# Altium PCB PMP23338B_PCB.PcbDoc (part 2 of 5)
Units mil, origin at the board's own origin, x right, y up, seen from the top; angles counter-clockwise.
Board outline 5708.66 x 4330.71 mil, 6 copper layers (Top Layer, Signal Layer 1, Signal Layer 2, Signal Layer 3, Signal Layer 4, Bottom Layer), stack 65.8 mil thick; 209 components, 108 nets, 629 pads, 390 vias.

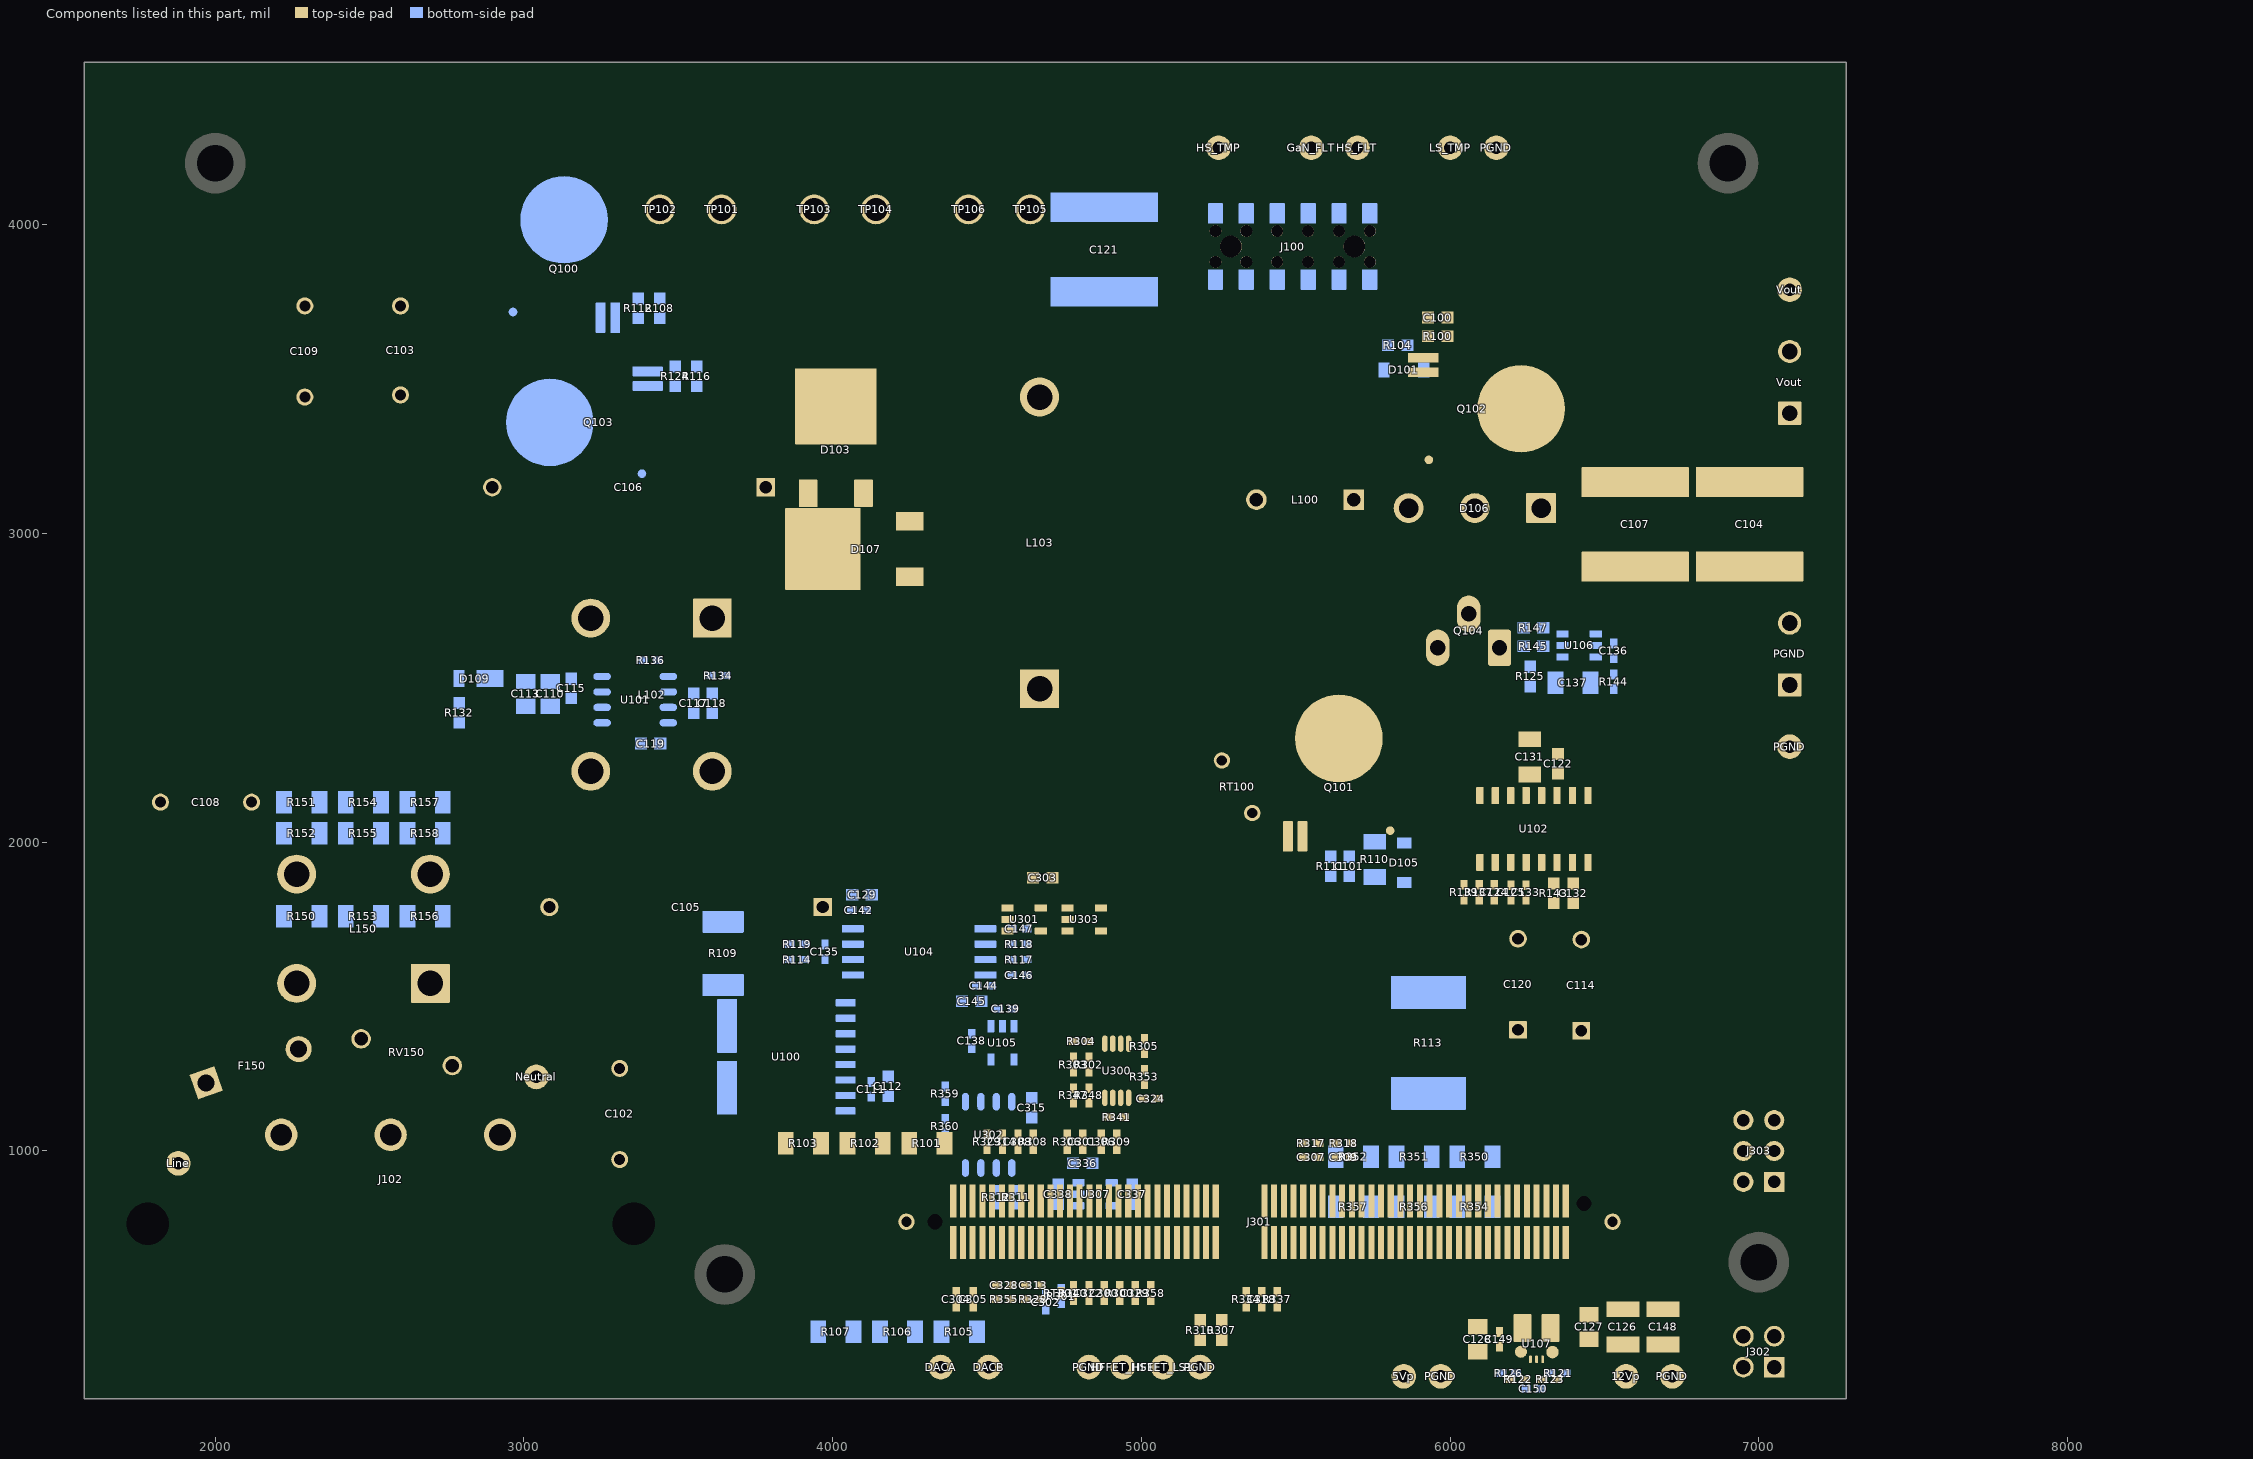
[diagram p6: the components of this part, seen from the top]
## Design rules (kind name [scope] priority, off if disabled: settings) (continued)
PolygonConnect PolygonConnect_38 [All vs IsNamedPolygon('SWNODE') Or  IsNamedPolygon('D403_2') Or  IsNamedPolygon('D403_2') Or  IsNamedPolygon('PGND') Or  IsNamedPolygon('BOTTOM_LAYER_NETC106_2_P030') Or  IsNamedPolygon('C102_1') Or  IsNamedPolygon('SGND') Or  IsNamedPolygon('TOP_LAYER_54V1_P046') Or  IsNamedPolygon('TOP_LAYER_54V2_P048') Or  IsNamedPolygon('TOP_LAYER_54V2_P048') Or  IsNamedPolygon('C108_1') Or  IsNamedPolygon('C108_1') Or  IsNamedPolygon('C108_1') Or  IsNamedPolygon('C108_1') Or  IsNamedPolygon('C108_1') Or  IsNamedPolygon('C108_1') Or  IsNamedPolygon('PGND') Or  IsNamedPolygon('ZCD') Or  IsNamedPolygon('Line') Or  IsNamedPolygon('5Vp') Or  IsNamedPolygon('12Vp') Or  IsNamedPolygon('T200_4') Or  IsNamedPolygon('T200_6') Or  IsNamedPolygon('SWNODE3') Or  IsNamedPolygon('T200_4') Or  IsNamedPolygon('T200_6') Or  IsNamedPolygon('SWNODE4') Or  IsNamedPolygon('VSR') Or  IsNamedPolygon('Iout_SNS') Or  IsNamedPolygon('SIGNAL_LAYER_2_VBB_P094') Or  IsNamedPolygon('Vbulk1') Or  IsNamedPolygon('VBB') Or  IsNamedPolygon('SIGNAL_LAYER_1_VBULK1_P106') Or  IsNamedPolygon('Line') Or  IsNamedPolygon('Line') Or  IsNamedPolygon('Line') Or  IsNamedPolygon('D404_2') Or  IsNamedPolygon('VBB') Or  IsNamedPolygon('D400_2') Or  IsNamedPolygon('SGND') Or  IsNamedPolygon('PGND') Or  IsNamedPolygon('TOP_LAYER_12VS_P126') Or  IsNamedPolygon('BOTTOM_LAYER_54V1_P128') Or  IsNamedPolygon('LEG3_HS_DRV') Or  IsNamedPolygon('LEG4_LS_DRV') Or  IsNamedPolygon('LEG4_HS_DRV') Or  IsNamedPolygon('SWNODE4') Or  IsNamedPolygon('SWNODE3') Or  IsNamedPolygon('T200_6') Or  IsNamedPolygon('T200_4') Or  IsNamedPolygon('VBB') Or  IsNamedPolygon('5Vs') Or  IsNamedPolygon('SGND') Or  IsNamedPolygon('Iout_SNS') Or  IsNamedPolygon('SGND') Or  IsNamedPolygon('SWNODE3') Or  IsNamedPolygon('SWNODE3') Or  IsNamedPolygon('SWNODE3') Or  IsNamedPolygon('SWNODE3') Or  IsNamedPolygon('SGND') Or  IsNamedPolygon('SGND') Or  IsNamedPolygon('SGND') Or  IsNamedPolygon('SWNODE4') Or  IsNamedPolygon('SWNODE4') Or  IsNamedPolygon('SWNODE4') Or  IsNamedPolygon('VSR') Or  IsNamedPolygon('SWNODE3') Or  IsNamedPolygon('SGND') Or  IsNamedPolygon('SGND') Or  IsNamedPolygon('SGND') Or  IsNamedPolygon('SGND') Or  IsNamedPolygon('SGND') Or  IsNamedPolygon('SGND') Or  IsNamedPolygon('BOTTOM_LAYER_54V1_P128') Or  IsNamedPolygon('SGND') Or  IsNamedPolygon('VSR') Or  IsNamedPolygon('C102_1') Or  IsNamedPolygon('C102_1') Or  IsNamedPolygon('C102_1') Or  IsNamedPolygon('C102_1') Or  IsNamedPolygon('C102_1') Or  IsNamedPolygon('ZCD') Or  IsNamedPolygon('PGND') Or  IsNamedPolygon('PGND') Or  IsNamedPolygon('Vbulk1') Or  IsNamedPolygon('VBB') Or  IsNamedPolygon('Vbulk1') Or  IsNamedPolygon('Vbulk1') Or  IsNamedPolygon('ZCD') Or  IsNamedPolygon('Neutral') Or  IsNamedPolygon('Neutral')] p22: connectstyle=Direct reliefconductorwidth=10 reliefentries=4 polygonreliefangle="90 Angle" airgapwidth=10
PolygonConnect PolygonConnect_37 [All vs IsNamedPolygon('SGND') Or  IsNamedPolygon('SWNODE4') Or  IsNamedPolygon('5Vp') Or  IsNamedPolygon('SWNODE4') Or  IsNamedPolygon('VBB') Or  IsNamedPolygon('Line') Or  IsNamedPolygon('SGND') Or  IsNamedPolygon('SIGNAL_LAYER_2_C102_1_P032') Or  IsNamedPolygon('TOP_LAYER_54V2_P048') Or  IsNamedPolygon('ZCD') Or  IsNamedPolygon('PGND') Or  IsNamedPolygon('SIGNAL_LAYER_2_VBB_P094') Or  IsNamedPolygon('Line') Or  IsNamedPolygon('Line') Or  IsNamedPolygon('D404_2') Or  IsNamedPolygon('PGND') Or  IsNamedPolygon('SIGNAL_LAYER_1_ZCD_P108') Or  IsNamedPolygon('SWNODE3') Or  IsNamedPolygon('SIGNAL_LAYER_4_C102_1_P038') Or  IsNamedPolygon('SWNODE3') Or  IsNamedPolygon('LEG4_HS_DRV') Or  IsNamedPolygon('SWNODE4') Or  IsNamedPolygon('5Vs') Or  IsNamedPolygon('VBB') Or  IsNamedPolygon('TOP_LAYER_54V2_P048') Or  IsNamedPolygon('C102_1') Or  IsNamedPolygon('LEG4_LS_DRV') Or  IsNamedPolygon('T200_4') Or  IsNamedPolygon('SWNODE3') Or  IsNamedPolygon('Line') Or  IsNamedPolygon('SGND') Or  IsNamedPolygon('SGND') Or  IsNamedPolygon('SWNODE4') Or  IsNamedPolygon('12Vp') Or  IsNamedPolygon('BOTTOM_LAYER_NETC106_2_P030') Or  IsNamedPolygon('T200_4') Or  IsNamedPolygon('Vbulk1') Or  IsNamedPolygon('C108_1') Or  IsNamedPolygon('BOTTOM_LAYER_54V1_P128') Or  IsNamedPolygon('BOTTOM_LAYER_54V1_P128') Or  IsNamedPolygon('SWNODE') Or  IsNamedPolygon('Iout_SNS') Or  IsNamedPolygon('VSR') Or  IsNamedPolygon('D400_2') Or  IsNamedPolygon('D403_2') Or  IsNamedPolygon('SWNODE3') Or  IsNamedPolygon('T200_6') Or  IsNamedPolygon('SWNODE3') Or  IsNamedPolygon('C108_1') Or  IsNamedPolygon('PGND') Or  IsNamedPolygon('BOTTOM_LAYER_VBULK1_P096') Or  IsNamedPolygon('BOTTOM_LAYER_54V1_P128') Or  IsNamedPolygon('TOP_LAYER_12VS_P126') Or  IsNamedPolygon('SIGNAL_LAYER_1_VBULK1_P106') Or  IsNamedPolygon('T200_4') Or  IsNamedPolygon('SGND') Or  IsNamedPolygon('C108_1') Or  IsNamedPolygon('SWNODE3') Or  IsNamedPolygon('T200_6') Or  IsNamedPolygon('T200_6') Or  IsNamedPolygon('T200_6') Or  IsNamedPolygon('SGND') Or  IsNamedPolygon('C108_1') Or  IsNamedPolygon('SGND') Or  IsNamedPolygon('VBB') Or  IsNamedPolygon('T200_4') Or  IsNamedPolygon('LEG3_HS_DRV') Or  IsNamedPolygon('C108_1') Or  IsNamedPolygon('D403_2') Or  IsNamedPolygon('Iout_SNS') Or  IsNamedPolygon('C108_1') Or  IsNamedPolygon('SWNODE4')] p23: connectstyle=Direct reliefconductorwidth=10 reliefentries=4 polygonreliefangle="90 Angle" airgapwidth=10
PolygonConnect PolygonConnect_36 [All vs IsNamedPolygon('PGND') Or  IsNamedPolygon('BOTTOM_LAYER_54V1_P128') Or  IsNamedPolygon('SGND') Or  IsNamedPolygon('LEG4_LS_DRV') Or  IsNamedPolygon('TOP_LAYER_12VS_P126') Or  IsNamedPolygon('LEG4_HS_DRV') Or  IsNamedPolygon('LEG3_HS_DRV') Or  IsNamedPolygon('SGND') Or  IsNamedPolygon('C108_1') Or  IsNamedPolygon('12Vp') Or  IsNamedPolygon('D403_2') Or  IsNamedPolygon('SIGNAL_LAYER_1_ZCD_P108') Or  IsNamedPolygon('C108_1') Or  IsNamedPolygon('BOTTOM_LAYER_VBULK1_P096') Or  IsNamedPolygon('SWNODE') Or  IsNamedPolygon('T200_4') Or  IsNamedPolygon('D400_2') Or  IsNamedPolygon('C102_1') Or  IsNamedPolygon('Line') Or  IsNamedPolygon('VBB') Or  IsNamedPolygon('Line') Or  IsNamedPolygon('TOP_LAYER_54V2_P048') Or  IsNamedPolygon('BOTTOM_LAYER_NETC106_2_P030') Or  IsNamedPolygon('SIGNAL_LAYER_1_VBULK1_P106') Or  IsNamedPolygon('Line') Or  IsNamedPolygon('5Vp') Or  IsNamedPolygon('BOTTOM_LAYER_54V1_P128') Or  IsNamedPolygon('D404_2') Or  IsNamedPolygon('C108_1') Or  IsNamedPolygon('VSR') Or  IsNamedPolygon('T200_6') Or  IsNamedPolygon('VBB') Or  IsNamedPolygon('C108_1') Or  IsNamedPolygon('SIGNAL_LAYER_2_C102_1_P032') Or  IsNamedPolygon('SGND') Or  IsNamedPolygon('PGND') Or  IsNamedPolygon('SIGNAL_LAYER_4_C102_1_P038') Or  IsNamedPolygon('Vbulk1') Or  IsNamedPolygon('TOP_LAYER_54V2_P048') Or  IsNamedPolygon('Iout_SNS') Or  IsNamedPolygon('PGND') Or  IsNamedPolygon('T200_4') Or  IsNamedPolygon('ZCD') Or  IsNamedPolygon('Line') Or  IsNamedPolygon('C108_1') Or  IsNamedPolygon('D403_2') Or  IsNamedPolygon('SIGNAL_LAYER_2_VBB_P094') Or  IsNamedPolygon('SGND') Or  IsNamedPolygon('C108_1') Or  IsNamedPolygon('SIGNAL_LAYER_1_IOUT_SNS_P044') Or  IsNamedPolygon('BOTTOM_LAYER_54V1_P128') Or  IsNamedPolygon('T200_6')] p24: connectstyle=Direct reliefconductorwidth=10 reliefentries=4 polygonreliefangle="90 Angle" airgapwidth=10
PolygonConnect PolygonConnect_35 [All vs IsNamedPolygon('SWNODE') Or  IsNamedPolygon('D403_2') Or  IsNamedPolygon('D403_2') Or  IsNamedPolygon('PGND') Or  IsNamedPolygon('BOTTOM_LAYER_NETC106_2_P030') Or  IsNamedPolygon('SIGNAL_LAYER_2_C102_1_P032') Or  IsNamedPolygon('C102_1') Or  IsNamedPolygon('SIGNAL_LAYER_4_C102_1_P038') Or  IsNamedPolygon('SGND') Or  IsNamedPolygon('SIGNAL_LAYER_1_IOUT_SNS_P044') Or  IsNamedPolygon('BOTTOM_LAYER_54V1_P128') Or  IsNamedPolygon('TOP_LAYER_54V2_P048') Or  IsNamedPolygon('BOTTOM_LAYER_54V1_P128') Or  IsNamedPolygon('TOP_LAYER_54V2_P048') Or  IsNamedPolygon('C108_1') Or  IsNamedPolygon('C108_1') Or  IsNamedPolygon('C108_1') Or  IsNamedPolygon('C108_1') Or  IsNamedPolygon('C108_1') Or  IsNamedPolygon('C108_1') Or  IsNamedPolygon('PGND') Or  IsNamedPolygon('ZCD') Or  IsNamedPolygon('Line') Or  IsNamedPolygon('5Vp') Or  IsNamedPolygon('12Vp') Or  IsNamedPolygon('T200_4') Or  IsNamedPolygon('T200_6') Or  IsNamedPolygon('SGND') Or  IsNamedPolygon('T200_4') Or  IsNamedPolygon('T200_6') Or  IsNamedPolygon('SGND') Or  IsNamedPolygon('VSR') Or  IsNamedPolygon('Iout_SNS') Or  IsNamedPolygon('SIGNAL_LAYER_2_VBB_P094') Or  IsNamedPolygon('BOTTOM_LAYER_VBULK1_P096') Or  IsNamedPolygon('Vbulk1') Or  IsNamedPolygon('VBB') Or  IsNamedPolygon('SIGNAL_LAYER_1_VBULK1_P106') Or  IsNamedPolygon('SIGNAL_LAYER_1_ZCD_P108') Or  IsNamedPolygon('Line') Or  IsNamedPolygon('Line') Or  IsNamedPolygon('Line') Or  IsNamedPolygon('D404_2') Or  IsNamedPolygon('VBB') Or  IsNamedPolygon('D400_2') Or  IsNamedPolygon('SGND') Or  IsNamedPolygon('PGND') Or  IsNamedPolygon('TOP_LAYER_12VS_P126') Or  IsNamedPolygon('BOTTOM_LAYER_54V1_P128') Or  IsNamedPolygon('LEG3_HS_DRV')] p25: connectstyle=Direct reliefconductorwidth=10 reliefentries=4 polygonreliefangle="90 Angle" airgapwidth=10
PolygonConnect PolygonConnect_34 [All vs IsNamedPolygon('SWNODE') Or  IsNamedPolygon('D403_2') Or  IsNamedPolygon('D403_2') Or  IsNamedPolygon('PGND') Or  IsNamedPolygon('BOTTOM_LAYER_NETC106_2_P030') Or  IsNamedPolygon('SIGNAL_LAYER_2_C102_1_P032') Or  IsNamedPolygon('C102_1') Or  IsNamedPolygon('SIGNAL_LAYER_4_C102_1_P038') Or  IsNamedPolygon('SGND') Or  IsNamedPolygon('SIGNAL_LAYER_1_IOUT_SNS_P044') Or  IsNamedPolygon('BOTTOM_LAYER_54V1_P128') Or  IsNamedPolygon('TOP_LAYER_54V2_P048') Or  IsNamedPolygon('BOTTOM_LAYER_54V1_P128') Or  IsNamedPolygon('TOP_LAYER_54V2_P048') Or  IsNamedPolygon('C108_1') Or  IsNamedPolygon('C108_1') Or  IsNamedPolygon('C108_1') Or  IsNamedPolygon('C108_1') Or  IsNamedPolygon('C108_1') Or  IsNamedPolygon('C108_1') Or  IsNamedPolygon('PGND') Or  IsNamedPolygon('ZCD') Or  IsNamedPolygon('Line') Or  IsNamedPolygon('5Vp') Or  IsNamedPolygon('12Vp') Or  IsNamedPolygon('T200_4') Or  IsNamedPolygon('T200_6') Or  IsNamedPolygon('SGND') Or  IsNamedPolygon('T200_4') Or  IsNamedPolygon('T200_6') Or  IsNamedPolygon('SGND') Or  IsNamedPolygon('VSR') Or  IsNamedPolygon('Iout_SNS') Or  IsNamedPolygon('SIGNAL_LAYER_2_VBB_P094') Or  IsNamedPolygon('BOTTOM_LAYER_VBULK1_P096') Or  IsNamedPolygon('Vbulk1') Or  IsNamedPolygon('VBB') Or  IsNamedPolygon('SIGNAL_LAYER_1_VBULK1_P106') Or  IsNamedPolygon('SIGNAL_LAYER_1_ZCD_P108') Or  IsNamedPolygon('Line') Or  IsNamedPolygon('Line') Or  IsNamedPolygon('Line') Or  IsNamedPolygon('D404_2') Or  IsNamedPolygon('VBB') Or  IsNamedPolygon('D400_2') Or  IsNamedPolygon('SGND')] p26: connectstyle=Direct reliefconductorwidth=10 reliefentries=4 polygonreliefangle="90 Angle" airgapwidth=10
PolygonConnect PolygonConnect_33 [All vs IsNamedPolygon('SIGNAL_LAYER_1_VBULK1_P106')] p27: connectstyle=Direct reliefconductorwidth=10 reliefentries=4 polygonreliefangle="90 Angle" airgapwidth=10
PolygonConnect PolygonConnect_32 [All vs IsNamedPolygon('SIGNAL_LAYER_1_VBULK1_P106')] p28: connectstyle=Direct reliefconductorwidth=10 reliefentries=4 polygonreliefangle="90 Angle" airgapwidth=10
PolygonConnect PolygonConnect_31 [All vs IsNamedPolygon('SIGNAL_LAYER_1_VBULK1_P106')] p29: connectstyle=Direct reliefconductorwidth=10 reliefentries=4 polygonreliefangle="90 Angle" airgapwidth=10
PolygonConnect PolygonConnect_30 [All vs IsNamedPolygon('VBB')] p30: connectstyle=Direct reliefconductorwidth=10 reliefentries=4 polygonreliefangle="90 Angle" airgapwidth=10
PolygonConnect PolygonConnect_29 [All vs IsNamedPolygon('SGND')] p31: connectstyle=Direct reliefconductorwidth=10 reliefentries=4 polygonreliefangle="90 Angle" airgapwidth=10
PolygonConnect PolygonConnect_28 [All vs IsNamedPolygon('Vbulk1')] p32: connectstyle=Direct reliefconductorwidth=10 reliefentries=4 polygonreliefangle="90 Angle" airgapwidth=10
PolygonConnect PolygonConnect_27 [All vs IsNamedPolygon('BOTTOM_LAYER_VBULK1_P096')] p33: connectstyle=Direct reliefconductorwidth=10 reliefentries=4 polygonreliefangle="90 Angle" airgapwidth=10
PolygonConnect PolygonConnect_26 [All vs IsNamedPolygon('SIGNAL_LAYER_2_VBB_P094')] p34: connectstyle=Direct reliefconductorwidth=10 reliefentries=4 polygonreliefangle="90 Angle" airgapwidth=10
PolygonConnect PolygonConnect_25 [All vs IsNamedPolygon('C108_1')] p35: connectstyle=Direct reliefconductorwidth=10 reliefentries=4 polygonreliefangle="90 Angle" airgapwidth=10
PolygonConnect PolygonConnect_24 [All vs IsNamedPolygon('BOTTOM_LAYER_EARTH_P100')] p36: connectstyle=Direct reliefconductorwidth=10 reliefentries=4 polygonreliefangle="90 Angle" airgapwidth=10
PolygonConnect PolygonConnect_23 [All vs IsNamedPolygon('BOTTOM_LAYER_54V1_P128')] p37: connectstyle=Direct reliefconductorwidth=10 reliefentries=4 polygonreliefangle="90 Angle" airgapwidth=10
PolygonConnect PolygonConnect_22 [All vs IsNamedPolygon('BOTTOM_LAYER_VBULK1_P096')] p38: connectstyle=Direct reliefconductorwidth=10 reliefentries=4 polygonreliefangle="90 Angle" airgapwidth=10
PolygonConnect PolygonConnect_21 [All vs IsNamedPolygon('SIGNAL_LAYER_2_VBB_P094')] p39: connectstyle=Direct reliefconductorwidth=10 reliefentries=4 polygonreliefangle="90 Angle" airgapwidth=10
PolygonConnect PolygonConnect_20 [All vs IsNamedPolygon('Iout_SNS')] p40: connectstyle=Direct reliefconductorwidth=10 reliefentries=4 polygonreliefangle="90 Angle" airgapwidth=10
PolygonConnect PolygonConnect_19 [All vs IsNamedPolygon('C108_1') Or  IsNamedPolygon('BOTTOM_LAYER_NETC106_2_P030') Or  IsNamedPolygon('D403_2') Or  IsNamedPolygon('C102_1') Or  IsNamedPolygon('SWNODE') Or  IsNamedPolygon('D403_2') Or  IsNamedPolygon('SIGNAL_LAYER_4_C102_1_P038') Or  IsNamedPolygon('PGND') Or  IsNamedPolygon('SIGNAL_LAYER_2_C102_1_P032') Or  IsNamedPolygon('SIGNAL_LAYER_1_IOUT_SNS_P044') Or  IsNamedPolygon('SGND') Or  IsNamedPolygon('C108_1') Or  IsNamedPolygon('BOTTOM_LAYER_54V1_P128') Or  IsNamedPolygon('C108_1') Or  IsNamedPolygon('C108_1') Or  IsNamedPolygon('TOP_LAYER_54V2_P048') Or  IsNamedPolygon('BOTTOM_LAYER_54V1_P128') Or  IsNamedPolygon('TOP_LAYER_54V2_P048') Or  IsNamedPolygon('C108_1') Or  IsNamedPolygon('C108_1') Or  IsNamedPolygon('12Vp') Or  IsNamedPolygon('5Vp') Or  IsNamedPolygon('Line') Or  IsNamedPolygon('T200_4') Or  IsNamedPolygon('SGND') Or  IsNamedPolygon('VSR') Or  IsNamedPolygon('ZCD') Or  IsNamedPolygon('PGND') Or  IsNamedPolygon('T200_6') Or  IsNamedPolygon('Neutral') Or  IsNamedPolygon('T200_4') Or  IsNamedPolygon('SGND') Or  IsNamedPolygon('T200_6')] p41: connectstyle=Direct reliefconductorwidth=10 reliefentries=4 polygonreliefangle="90 Angle" airgapwidth=10
PolygonConnect PolygonConnect_18 [All vs IsNamedPolygon('SWNODE') Or  IsNamedPolygon('D403_2') Or  IsNamedPolygon('D403_2') Or  IsNamedPolygon('PGND') Or  IsNamedPolygon('BOTTOM_LAYER_NETC106_2_P030') Or  IsNamedPolygon('SIGNAL_LAYER_2_C102_1_P032') Or  IsNamedPolygon('C102_1') Or  IsNamedPolygon('SIGNAL_LAYER_4_C102_1_P038') Or  IsNamedPolygon('SGND') Or  IsNamedPolygon('SIGNAL_LAYER_1_IOUT_SNS_P044') Or  IsNamedPolygon('BOTTOM_LAYER_54V1_P128') Or  IsNamedPolygon('TOP_LAYER_54V2_P048') Or  IsNamedPolygon('BOTTOM_LAYER_54V1_P128') Or  IsNamedPolygon('TOP_LAYER_54V2_P048') Or  IsNamedPolygon('C108_1') Or  IsNamedPolygon('C108_1') Or  IsNamedPolygon('C108_1') Or  IsNamedPolygon('C108_1') Or  IsNamedPolygon('C108_1') Or  IsNamedPolygon('C108_1') Or  IsNamedPolygon('Neutral') Or  IsNamedPolygon('PGND') Or  IsNamedPolygon('ZCD') Or  IsNamedPolygon('Line') Or  IsNamedPolygon('5Vp') Or  IsNamedPolygon('12Vp') Or  IsNamedPolygon('T200_4') Or  IsNamedPolygon('T200_6') Or  IsNamedPolygon('SGND') Or  IsNamedPolygon('T200_4') Or  IsNamedPolygon('T200_6') Or  IsNamedPolygon('SGND')] p42: connectstyle=Direct reliefconductorwidth=10 reliefentries=4 polygonreliefangle="90 Angle" airgapwidth=10
PolygonConnect PolygonConnect_17 [All vs IsNamedPolygon('12Vp') Or  IsNamedPolygon('T200_4') Or  IsNamedPolygon('T200_6') Or  IsNamedPolygon('SGND') Or  IsNamedPolygon('TOP_LAYER_54V2_P048') Or  IsNamedPolygon('SIGNAL_LAYER_1_IOUT_SNS_P044') Or  IsNamedPolygon('BOTTOM_LAYER_54V1_P128') Or  IsNamedPolygon('SGND') Or  IsNamedPolygon('C102_1') Or  IsNamedPolygon('SIGNAL_LAYER_4_C102_1_P038') Or  IsNamedPolygon('Neutral') Or  IsNamedPolygon('C108_1') Or  IsNamedPolygon('C108_1') Or  IsNamedPolygon('C108_1') Or  IsNamedPolygon('BOTTOM_LAYER_54V1_P128') Or  IsNamedPolygon('TOP_LAYER_54V2_P048') Or  IsNamedPolygon('SIGNAL_LAYER_2_C102_1_P032') Or  IsNamedPolygon('SWNODE') Or  IsNamedPolygon('C108_1') Or  IsNamedPolygon('C108_1') Or  IsNamedPolygon('C108_1') Or  IsNamedPolygon('D403_2') Or  IsNamedPolygon('BOTTOM_LAYER_NETC106_2_P030') Or  IsNamedPolygon('PGND') Or  IsNamedPolygon('D403_2') Or  IsNamedPolygon('5Vp') Or  IsNamedPolygon('PGND') Or  IsNamedPolygon('ZCD') Or  IsNamedPolygon('Line')] p43: connectstyle=Direct reliefconductorwidth=10 reliefentries=4 polygonreliefangle="90 Angle" airgapwidth=10
PolygonConnect PolygonConnect_16 [All vs IsNamedPolygon('D403_2') Or  IsNamedPolygon('C102_1') Or  IsNamedPolygon('C108_1') Or  IsNamedPolygon('SWNODE') Or  IsNamedPolygon('BOTTOM_LAYER_54V1_P128') Or  IsNamedPolygon('SGND') Or  IsNamedPolygon('Line') Or  IsNamedPolygon('ZCD') Or  IsNamedPolygon('SIGNAL_LAYER_1_IOUT_SNS_P044') Or  IsNamedPolygon('Neutral') Or  IsNamedPolygon('PGND') Or  IsNamedPolygon('12Vp') Or  IsNamedPolygon('C108_1') Or  IsNamedPolygon('C108_1') Or  IsNamedPolygon('TOP_LAYER_54V2_P048') Or  IsNamedPolygon('C108_1') Or  IsNamedPolygon('TOP_LAYER_54V2_P048') Or  IsNamedPolygon('T200_4') Or  IsNamedPolygon('T200_6') Or  IsNamedPolygon('D403_2') Or  IsNamedPolygon('C108_1') Or  IsNamedPolygon('C108_1') Or  IsNamedPolygon('SIGNAL_LAYER_4_C102_1_P038') Or  IsNamedPolygon('SIGNAL_LAYER_2_C102_1_P032') Or  IsNamedPolygon('PGND') Or  IsNamedPolygon('BOTTOM_LAYER_NETC106_2_P030') Or  IsNamedPolygon('5Vp') Or  IsNamedPolygon('BOTTOM_LAYER_54V1_P128')] p44: connectstyle=Direct reliefconductorwidth=10 reliefentries=4 polygonreliefangle="90 Angle" airgapwidth=10
PolygonConnect PolygonConnect_15 [All vs IsNamedPolygon('SWNODE') Or  IsNamedPolygon('D403_2') Or  IsNamedPolygon('D403_2') Or  IsNamedPolygon('SIGNAL_LAYER_1_PGND_P018') Or  IsNamedPolygon('PGND') Or  IsNamedPolygon('BOTTOM_LAYER_NETC106_2_P030') Or  IsNamedPolygon('SIGNAL_LAYER_2_C102_1_P032') Or  IsNamedPolygon('C102_1') Or  IsNamedPolygon('SIGNAL_LAYER_4_C102_1_P038') Or  IsNamedPolygon('SGND') Or  IsNamedPolygon('SIGNAL_LAYER_1_IOUT_SNS_P044') Or  IsNamedPolygon('BOTTOM_LAYER_54V1_P128') Or  IsNamedPolygon('TOP_LAYER_54V2_P048') Or  IsNamedPolygon('BOTTOM_LAYER_54V1_P128') Or  IsNamedPolygon('TOP_LAYER_54V2_P048') Or  IsNamedPolygon('C108_1') Or  IsNamedPolygon('C108_1') Or  IsNamedPolygon('C108_1') Or  IsNamedPolygon('C108_1') Or  IsNamedPolygon('C108_1') Or  IsNamedPolygon('C108_1') Or  IsNamedPolygon('Neutral') Or  IsNamedPolygon('PGND') Or  IsNamedPolygon('ZCD') Or  IsNamedPolygon('Line') Or  IsNamedPolygon('5Vp') Or  IsNamedPolygon('12Vp')] p45: connectstyle=Direct reliefconductorwidth=10 reliefentries=4 polygonreliefangle="90 Angle" airgapwidth=10
PolygonConnect PolygonConnect_14 [All vs IsNamedPolygon('TOP_LAYER_54V2_P048') Or  IsNamedPolygon('C108_1') Or  IsNamedPolygon('C108_1') Or  IsNamedPolygon('SIGNAL_LAYER_4_C102_1_P038') Or  IsNamedPolygon('C102_1') Or  IsNamedPolygon('SIGNAL_LAYER_2_C102_1_P032') Or  IsNamedPolygon('SIGNAL_LAYER_1_PGND_P018') Or  IsNamedPolygon('SIGNAL_LAYER_1_IOUT_SNS_P044') Or  IsNamedPolygon('SGND') Or  IsNamedPolygon('C108_1') Or  IsNamedPolygon('ZCD') Or  IsNamedPolygon('PGND') Or  IsNamedPolygon('TOP_LAYER_54V2_P048') Or  IsNamedPolygon('BOTTOM_LAYER_NETC106_2_P030') Or  IsNamedPolygon('PGND') Or  IsNamedPolygon('C108_1') Or  IsNamedPolygon('C108_1') Or  IsNamedPolygon('D403_2') Or  IsNamedPolygon('Line') Or  IsNamedPolygon('C108_1') Or  IsNamedPolygon('Neutral') Or  IsNamedPolygon('SWNODE') Or  IsNamedPolygon('D403_2') Or  IsNamedPolygon('BOTTOM_LAYER_54V1_P128') Or  IsNamedPolygon('BOTTOM_LAYER_54V1_P128')] p46: connectstyle=Direct reliefconductorwidth=10 reliefentries=4 polygonreliefangle="90 Angle" airgapwidth=10
PolygonConnect PolygonConnect_13 [All vs IsNamedPolygon('PGND') Or  IsNamedPolygon('D403_2') Or  IsNamedPolygon('SIGNAL_LAYER_1_PGND_P018') Or  IsNamedPolygon('D403_2') Or  IsNamedPolygon('SWNODE') Or  IsNamedPolygon('SGND') Or  IsNamedPolygon('BOTTOM_LAYER_54V1_P128') Or  IsNamedPolygon('C108_1') Or  IsNamedPolygon('SIGNAL_LAYER_4_C102_1_P038') Or  IsNamedPolygon('C108_1') Or  IsNamedPolygon('TOP_LAYER_54V2_P048') Or  IsNamedPolygon('TOP_LAYER_54V2_P048') Or  IsNamedPolygon('C108_1') Or  IsNamedPolygon('C108_1') Or  IsNamedPolygon('C108_1') Or  IsNamedPolygon('BOTTOM_LAYER_NETC106_2_P030') Or  IsNamedPolygon('SIGNAL_LAYER_1_IOUT_SNS_P044') Or  IsNamedPolygon('C108_1') Or  IsNamedPolygon('C102_1') Or  IsNamedPolygon('SIGNAL_LAYER_2_C102_1_P032') Or  IsNamedPolygon('BOTTOM_LAYER_54V1_P128')] p47: connectstyle=Direct reliefconductorwidth=10 reliefentries=4 polygonreliefangle="90 Angle" airgapwidth=10
PolygonConnect PolygonConnect_12 [All vs IsNamedPolygon('TOP_LAYER_54V2_P048')] p48: connectstyle=Direct reliefconductorwidth=10 reliefentries=4 polygonreliefangle="90 Angle" airgapwidth=10
PolygonConnect PolygonConnect_11 [All vs IsNamedPolygon('BOTTOM_LAYER_54V1_P128')] p49: connectstyle=Direct reliefconductorwidth=10 reliefentries=4 polygonreliefangle="90 Angle" airgapwidth=10
PolygonConnect PolygonConnect_10 [All vs IsNamedPolygon('SIGNAL_LAYER_1_IOUT_SNS_P044')] p50: thpad.connectstyle=Direct thpad.reliefconductorwidth=10 thpad.reliefentries=4 thpad.polygonreliefangle="90 Angle" thpad.airgapwidth=10 smdpad.connectstyle=Relief smdpad.reliefconductorwidth=10 smdpad.reliefentries=4 smdpad.polygonreliefangle="90 Angle" smdpad.airgapwidth=10 via.connectstyle=Direct via.reliefconductorwidth=10 via.reliefentries=4 via.polygonreliefangle="90 Angle" via.airgapwidth=10
PolygonConnect PolygonConnect_9 [All vs IsNamedPolygon('SGND')] p51: thpad.connectstyle=Direct thpad.reliefconductorwidth=10 thpad.reliefentries=4 thpad.polygonreliefangle="90 Angle" thpad.airgapwidth=10 smdpad.connectstyle=Relief smdpad.reliefconductorwidth=10 smdpad.reliefentries=4 smdpad.polygonreliefangle="90 Angle" smdpad.airgapwidth=10 via.connectstyle=Direct via.reliefconductorwidth=10 via.reliefentries=4 via.polygonreliefangle="90 Angle" via.airgapwidth=10
PolygonConnect PolygonConnect_8 [All vs IsNamedPolygon('SGND')] p52: thpad.connectstyle=Direct thpad.reliefconductorwidth=10 thpad.reliefentries=4 thpad.polygonreliefangle="90 Angle" thpad.airgapwidth=10 smdpad.connectstyle=Relief smdpad.reliefconductorwidth=10 smdpad.reliefentries=4 smdpad.polygonreliefangle="90 Angle" smdpad.airgapwidth=10 via.connectstyle=Direct via.reliefconductorwidth=10 via.reliefentries=4 via.polygonreliefangle="90 Angle" via.airgapwidth=10
PolygonConnect PolygonConnect_7 [All vs IsNamedPolygon('SGND')] p53: thpad.connectstyle=Relief thpad.reliefconductorwidth=0 thpad.reliefentries=4 thpad.polygonreliefangle="90 Angle" thpad.airgapwidth=0 smdpad.connectstyle=Relief smdpad.reliefconductorwidth=10 smdpad.reliefentries=4 smdpad.polygonreliefangle="90 Angle" smdpad.airgapwidth=10 via.connectstyle=Relief via.reliefconductorwidth=10 via.reliefentries=4 via.polygonreliefangle="90 Angle" via.airgapwidth=10
PolygonConnect PolygonConnect_6 [All vs IsNamedPolygon('SGND')] p54: thpad.connectstyle=Direct thpad.reliefconductorwidth=10 thpad.reliefentries=4 thpad.polygonreliefangle="90 Angle" thpad.airgapwidth=10 smdpad.connectstyle=Relief smdpad.reliefconductorwidth=10 smdpad.reliefentries=4 smdpad.polygonreliefangle="90 Angle" smdpad.airgapwidth=10 via.connectstyle=Relief via.reliefconductorwidth=10 via.reliefentries=4 via.polygonreliefangle="90 Angle" via.airgapwidth=10
PolygonConnect PolygonConnect_5 [All vs IsNamedPolygon('SGND')] p55: thpad.connectstyle=Direct thpad.reliefconductorwidth=10 thpad.reliefentries=4 thpad.polygonreliefangle="90 Angle" thpad.airgapwidth=10 smdpad.connectstyle=Relief smdpad.reliefconductorwidth=10 smdpad.reliefentries=4 smdpad.polygonreliefangle="90 Angle" smdpad.airgapwidth=10 via.connectstyle=Relief via.reliefconductorwidth=10 via.reliefentries=4 via.polygonreliefangle="90 Angle" via.airgapwidth=10
PolygonConnect PolygonConnect_4 [All vs IsNamedPolygon('SIGNAL_LAYER_1_PGND_P018') Or  IsNamedPolygon('SWNODE') Or  IsNamedPolygon('D403_2') Or  IsNamedPolygon('SIGNAL_LAYER_4_C102_1_P038') Or  IsNamedPolygon('D403_2') Or  IsNamedPolygon('BOTTOM_LAYER_NETC106_2_P030') Or  IsNamedPolygon('C102_1') Or  IsNamedPolygon('PGND') Or  IsNamedPolygon('SIGNAL_LAYER_2_C102_1_P032')] p56: connectstyle=Direct reliefconductorwidth=10 reliefentries=4 polygonreliefangle="90 Angle" airgapwidth=10
PolygonConnect PolygonConnect_3 [All vs IsNamedPolygon('SWNODE') Or  IsNamedPolygon('D403_2') Or  IsNamedPolygon('Neutral') Or  IsNamedPolygon('C106_2') Or  IsNamedPolygon('D403_2') Or  IsNamedPolygon('Neutral') Or  IsNamedPolygon('Neutral')] p57: connectstyle=Direct reliefconductorwidth=10 reliefentries=4 polygonreliefangle="90 Angle" airgapwidth=10
PolygonConnect PolygonConnect_2 [All vs IsNamedPolygon('Neutral') Or  IsNamedPolygon('Neutral') Or  IsNamedPolygon('C106_2') Or  IsNamedPolygon('SWNODE') Or  IsNamedPolygon('Neutral')] p58: connectstyle=Direct reliefconductorwidth=10 reliefentries=4 polygonreliefangle="90 Angle" airgapwidth=10
PolygonConnect PolygonConnect_1 [All vs IsNamedPolygon('Neutral') Or  IsNamedPolygon('Neutral')] p59: connectstyle=Direct reliefconductorwidth=10 reliefentries=4 polygonreliefangle="90 Angle" airgapwidth=10
PolygonConnect [All] p60: connectstyle=Direct reliefconductorwidth=10 reliefentries=4 polygonreliefangle="90 Angle" airgapwidth=10
RoutingVias ThermalPadVias [IsVia and InAnyComponent] p1: holewidth=7.87 width=19.68 viastyle="Through Hole" minholewidth=7.87 minwidth=19.68 maxholewidth=12.99 maxwidth=23.62
RoutingVias [All] p2: holewidth=16 width=34 viastyle="Through Hole" minholewidth=7.87 minwidth=20 maxholewidth=40 maxwidth=65
SilkToBoardRegionClearance [Not ((IsComment or IsDesignator) And (Hide <> 'False')) and not InRegion(1000,500,4000,800)] p1:
SilkToSilkClearance SilkToSilkClearance_Pb-FreeLogo [(HasFootprint('Pb-Free_Overlay_Medium') OR HasFootprint('Pb-Free_Overlay_Small')) vs (HasFootprint('Pb-Free_Overlay_Medium') OR HasFootprint('Pb-Free_Overlay_Small'))] p1: silktosilkclearance=0
SilkToSilkClearance [All] p2: silktosilkclearance=4
SilkToSolderMaskClearance SilkToComponentPadClearance [(IsPad or IsFill or IsRegion) and InAnycomponent] p1: minsilkscreentomaskgap=5 clearancetoexposedcopper=TRUE
SilkToSolderMaskClearance "Silk to Solder Mask Opening" [All] p2: minsilkscreentomaskgap=4 clearancetoexposedcopper=FALSE
SolderMaskExpansion [All] p1: expansion=1.97 istentingtop=FALSE
Width [All] p1: maxlimit=100 minlimit=6 preferedwidth=10 checkconnectedcopper=TRUE
13 further rules are at their usual default settings.

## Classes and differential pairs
component class PMP23338B_Controller: 12Vp C300 C301 C302 C303 C304 C305 C306 C307 C308 C309 C313 C314 C315 C318 C322 C324 C328 C329 C336 C337 C338 DACA DACB HFFET_HS1 HFFET_LS1 J301 J302 J303 J305 J306 PGND R300 R301 R302 R303 R304 R305 R306 R307 R308 R309 R310 R311 R312 R317 R318 R328 R329 R334 R337 R340 R341 R347 R348 R350 R351 R352 R353 R354 R355 R356 R357 R358 R359 R360 RT301 U300 U301 U302 U303 U307
net class HV: 5Vs 12V1 +BRDG_N AINN AINP BB_BYPAS DRV_Relay Line NetC100_1 NetC101_2 NetC102_1 NetC103_1 NetC105_2 NetC110_1 NetC135_1 NetC135_2 NetD106_1 NetF150_1 NetF150_2 NetJ102_2 NetQ100_1 NetR350_1 NetR354_1 SWNODE VBB Vbulk Vbulk1
net class MV: NetR101_2 NetR102_2 NetR105_2 NetR106_2 NetR351_1 NetR356_1
component class PMP23338B_PFC: 5Vp !PCB100 C100 C101 C102 C103 C104 C105 C106 C107 C108 C109 C110 C111 C112 C113 C114 C115 C117 C118 C119 C120 C121 C122 C124 C125 C126 C127 C128 C129 C131 C132 C133 C135 C136 C137 C138 C139 C142 C144 C145 C146 C147 C148 C149 C150 D101 D103 D105 D106 D107 D109 F150 GaN_FLT HS_FLT HS_TMP J100 J102 L100 L102 L103 L150 Line LOGO100 LOGO101 Logo102 Logo103 LS_TMP Neutral PGND Q100 Q101 Q102 Q103 Q104 Q? R100 R101 R102 R103 R104 R105 R106 R107 R108 R109 R110 R111 R112 R113 R114 R116 R117 R118 R119 R121 R122 R123 R124 R125 R126 R132 R134 R136 R137 R139 R143 R144 R145 R147 R150 R151 R152 R153 R154 R155 R156 R157 R158 RT100 RV150 TP101 TP102 TP103 TP104 TP105 TP106 U100 U101 U102 U104 U105 U106 U107 Vout
component class Header: J302 J303

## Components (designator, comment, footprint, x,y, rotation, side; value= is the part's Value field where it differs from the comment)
5Vp "5000" Keystone5000 5850,270 r0 top
12Vp "5000" Keystone5000 6570,270 r90 top
C100 "06033C104JAT2A" 0603 5960,3700 r0 top value=0.1uF
C101 "06033C104JAT2A" 0603 5673.15,1921.89 r270 bottom value=0.1uF
C102 "DE6E3KJ222MN3A" E_900x700x900#1 3310,1120 r270 top value=2200pF
C103 "DE6E3KJ222MN3A" E_900x700x900#2 2600,3590 r90 top value=2200pF
C104 "B58031U5105M062" FP-B58031U5105M062_SMD2-MFG 6970,3030 r90 top value=1µF
C105 "B32923H3474K000" B32923_16.5mm_10.5 3525,1790 r180 top value=0.47uF
C106 "B32923H3155K000" B32923_29.5mm 3340,3150 r180 top value=1.5uF
C107 "B58031U5105M062" FP-B58031U5105M062_SMD2-MFG 6600,3030 r90 top value=1µF
C108 "DE6E3KJ222MN3A" E_900x700x900#1 1970,2130 r0 top value=2200pF
C109 "DE6E3KJ222MN3A" E_900x700x900#1 2290,3590 r270 top value=2200pF
C110 "0805YD106MAT2A" 0805_HV 3084.65,2480.79 r270 bottom value=10uF
C111 "GRM155R70J104KA01D" 0402 4125,1200 r90 bottom value=0.1uF
C112 "GRM185R60J105KE26D" 0603 4180,1210 r90 bottom value=1uF
C113 "0805YD106MAT2A" 0805_HV 3005.91,2480.79 r270 bottom value=10uF
C114 "450HXW180MEFR16X50" FP-450HXW180MEFR16X50_RADIAL-MFG 6425,1537.36 r90 top value=180µF
C115 "C1608X7R1E105K080AB" 0603 3153.54,2498.5 r90 bottom value=1uF
C117 "06035A102KAT2A" 0603 3550,2450 r270 bottom value=1000pF
C118 "06035A102KAT2A" 0603 3610,2450 r270 bottom value=1000pF
C119 "C0603X103K5RACTU" 0603 3410,2320 r0 bottom value=0.01uF
C120 "450HXW180MEFR16X50" FP-450HXW180MEFR16X50_RADIAL-MFG 6220,1540 r90 top value=180µF
C121 "B58031U5105M062" FP-B58031U5105M062_SMD2-MFG 4880,3920 r270 bottom value=1µF
C122 "06033C104JAT2A" 0603 6349.52,2254.44 r270 top value=0.1uF
C124 "0402YC101KAT2A" 0402 6143.46,1838.43 r270 top value=100pF
C125 "0402YC101KAT2A" 0402 6197.6,1837.44 r270 top value=100pF
C126 "GRM32ER61C476KE15L" 1210_270 6560,430 r270 top value=47uF
C127 "C0805C105K3RACTU" 0805_HV 6450,430 r90 top value=1uF
C128 "CL21A226KQQNNNE" 0805_HV 6090,390 r270 top value=22uF
C129 "GCM188R70J225KE22D" 0603 4095,1830 r180 bottom value=2.2uF
C131 "C3216X7R1E105K085AA" 1206 6257.72,2276.42 r90 top value=1uF
C132 "GRM188R71E102KA01D" 0603 6398.39,1834.49 r270 top value=1000pF
C133 "0402YC104KAT2A" 0402 6245.83,1837.44 r270 top value=0.1uF
C135 "GRM155R60J103KA01D" 0402 3975,1645 r90 bottom value=0.01uF
C136 "0402YC101KAT2A" 0402 6530,2620 r90 bottom value=100pF
C137 "C3216X7R1E105K085AA" 1206 6398.03,2517.48 r0 bottom value=1uF
C138 "GRM155R70J104KA01D" 0402 4450,1356.38 r90 bottom value=0.1uF
C139 "GRM155R70J104KA01D" 0402 4560,1460 r180 bottom value=0.1uF
C142 "550L104KCAT" 0402_065 4085,1780 r180 bottom value=0.1uF
C144 "550L104KCAT" 0402_065 4490,1535 r180 bottom value=0.1uF
C145 "GCM188R70J225KE22D" 0603 4450,1485 r180 bottom value=2.2uF
C146 "C0402C100C8GACTU" 0402 4605,1570 r0 bottom value=10pF
C147 "C0402C100C8GACTU" 0402 4605,1720 r0 bottom value=10pF
C148 "GRM32ER61C476KE15L" 1210_270 6690,430 r90 top value=47uF
C149 "550L104KCAT" 0402_065 6160,390 r270 top value=0.1uF
C150 "C0402C103K4RACTU" 0402 6270,230 r180 bottom value=0.01uF
C300 "GRM155R60J104KA01D" 0402 4880,540 r90 top value=0.1uF
C301 "04025U100CAT2A" 0402 4810,1030 r90 top value=10pF
C302 "GRM155R60J104KA01D" 0402 4690,510 r90 bottom value=0.1uF
C303 "C1608X7R1E105K080AB" 0603 4680,1885 r0 top value=1uF
C304 "04025U100CAT2A" 0402 4400,520 r270 top value=10pF
C305 "04025U100CAT2A" 0402 4455,520 r270 top value=10pF
C306 "04025U100CAT2A" 0402 4870,1030 r90 top value=10pF
C307 "C0402C100C8GACTU" 0402 5550,980 r180 top value=10pF
C308 "GRM155R61H472KA01D" 0402 4600,1030 r90 top value=4700pF
C309 "C0402C100C8GACTU" 0402 5655,980 r0 top value=10pF
C313 "CGA2B2X7R1H471K050BA" 0402 4650,565 r0 top value=470pF
C314 "CGA2B2X7R1H471K050BA" 0402 4550,1030 r90 top value=470pF
C315 "C1608X7R1E105K080AB" 0603 4645,1140 r270 bottom value=1uF
C318 "GRM155R70J103KA01D" 0402 5390,520 r270 top value=0.01uF
C322 "CGA2B2X7R1H471K050BA" 0402 4830,540 r270 top value=470pF
C324 "CC0402MRX5R6BB105" 0402 5030,1170 r0 top value=1uF
C328 "CGA2B2X7R1H471K050BA" 0402 4555,565 r180 top value=470pF
C329 "CGA2B2X7R1H471K050BA" 0402 4980,540 r270 top value=470pF
C336 "06033C104JAT2A" 0603 4810,960 r0 bottom value=0.1uF
C337 "06033C104JAT2A" 0603 4970,860 r270 bottom value=0.1uF
C338 "06033C104JAT2A" 0603 4730,860 r270 bottom value=0.1uF
D101 "MBR140SFT1G" SOD-123FL 5850,3530 r0 bottom value=40V
D103 "VS-15EVL06-M3/I" "FP-VS-15AWL06FN-M3_D-PAK (TO-252AA)-MFG" 4010,3310 r0 top
D105 "MBR140SFT1G" SOD-123FL 5851.3,1933.7 r270 bottom value=40V
D106 "FFA60UA60DN" FP-FFA60UA60DN_SC-65-MFG 6080,3070 r270 top
D107 "VS-15EVL06-M3/I" "FP-VS-15AWL06FN-M3_D-PAK (TO-252AA)-MFG" 4070,2950 r90 top
D109 "DFLR1600-7" PowerDI123 2840,2530 r180 bottom value=600V
DACA "5003" Keystone5003 4350,300 r90 top
DACB "5003" Keystone5003 4505,300 r90 top
F150 "0525025.MXEP_vm" FP-0525025.MXEP_vm_AXIAL-MFG 1970.61,1221.03 r20 top
GaN_FLT "5003" Keystone5003 5550,4250 r90 top
HFFET_HS1 "5004" Keystone5004 4940,300 r90 top
HFFET_LS1 "5004" Keystone5004 5070,300 r90 top
HS_FLT "5003" Keystone5003 5700,4250 r90 top
HS_TMP "5003" Keystone5003 5250,4250 r90 top
J100 "HLE-106-02-G-DV-BE-A" FP-HLE-106-02-G-DV-BE-A_HDR12-MFG 5490,3930 r180 bottom locked
J102 "703W-00/54" CONN_QUALTEK-703W-0054 2567.91,657.48 r180 top
J301 "HSEC8-160-01-L-DV-A-BL" controlCARD-120HSEC 5310,770 r0 top
J302 "PBC02DAAN" Sullins_PxC02DAAN 7000,350 r180 top locked
J303 "PBC03DAAN" Sullins_PBC03DAAN 7000,1000 r180 top locked
L100 "PAL6598.223NL" FP-PAL6281.104NL_PTH_20MM5_11MM0-MFG 5530,3110 r270 top value=22uH
L102 "PAC6596NL" FP-PAC6270NL_PTH_TRANSFORMER_30MM0_19MM0-MFG 3413.15,2478.03 r180 top
L103 "PAL6585.254NL" FP-PAL6269NL_PTH_32MM0_27MM8-MFG 4670,2970 r180 top value=250uH
L150 "PAC6597NL" FP-PAC6280NL_PTH_25MM0_12MM5-MFG 2480,1720 r0 top value=8.3mH
Line "L" Keystone5000 1880,960 r90 top value=Red
LOGO100 "CAUTION HOT SURFACE" IEC_HotSurface_Small 2080,3160 r0 top
LOGO101 "DANGER HIGH VOLTAGE" IEC_HighVoltage_Small 2080,2870 r0 top
Logo102 "FCC disclaimer" FCC_disclaimer 2530,3130 r270 top
Logo103 "WEEE logo" WEEE_Minimum 2080,2600 r0 top
LS_TMP "5003" Keystone5003 6000,4250 r90 top
Neutral "N" Keystone5001 3040,1240 r90 top value=Black
PGND "5001" Keystone5001 5970,270 r90 top
PGND "N" Keystone5001 7100,2310 r90 top value=Black
PGND "1715721" PhoenixContact_1715721 7100,2610 r90 top
PGND "5001" Keystone5001 4830,300 r90 top
PGND "5001" Keystone5001 5190,300 r90 top
PGND "5001" Keystone5001 6720,270 r180 top
PGND "5001" Keystone5001 6150,4250 r90 top
Q100 "IPT60R022S7XTMA1" FP-IPT60R080G7XTMA1_HSOF-8-MFG 3130,3910 r180 bottom
Q101 "IPT60R022S7XTMA1" FP-IPT60R080G7XTMA1_HSOF-8-MFG 5640,2230 r0 top
Q102 "IPT60R022S7XTMA1" FP-IPT60R080G7XTMA1_HSOF-8-MFG 6123.5,3404.33 r270 top
Q103 "IPT60R022S7XTMA1" FP-IPT60R080G7XTMA1_HSOF-8-MFG 3190,3360 r270 bottom
Q104 "IPP60R060P7XKSA1" TO-220AB 6060,2630 r180 top
R100 "CRCW060310K0FKEA" 0603 5960,3640 r180 top value=10.0k
R101 "RC1206FR-07348KL" 1206 4305,1025 r180 top value=348k
R102 "RC1206FR-07348KL" 1206 4105,1025 r180 top value=348k
R103 "RC1206FR-07348KL" 1206 3905,1025 r180 top value=348k
R104 "CRCW06035R11FKEA" 0603 5830,3610 r180 bottom value=5.11
R105 "RC1206FR-07348KL" 1206 4410,415 r180 bottom value=348k
R106 "RC1206FR-07348KL" 1206 4210,415 r180 bottom value=348k
R107 "RC1206FR-07348KL" 1206 4010,415 r180 bottom value=348k
R108 "CRCW060310R0FKEA" 0603 3440,3730 r90 bottom value=10.0
R109 "CSS2H-2512K-2L30F" FP-CSS2H-2512K-2L30F_2512-MFG 3645,1640 r90 bottom value=2.3m
R110 "CRCW12065R11FKEA" 1206 5755.83,1944.53 r270 bottom value=5.11
R111 "CRCW060310K0FKEA" 0603 5614.09,1921.89 r90 bottom value=10.0k
R112 "CRCW060310K0FKEA" 0603 3370,3730 r90 bottom value=10.0k
R113 "WSLP39212L500FEA" FP-WSLP3921L1000FEA_3921-MFG 5930,1350 r90 bottom value=2.5m
R114 "CRCW040210R0JNED" 0402 3885,1620 r0 bottom value=10
R116 "CRCW060310R0FKEA" 0603 3560,3510 r90 bottom value=10.0
R117 "CRCW04020000Z0ED" 0402 4605,1620 r0 bottom value=0
R118 "CRCW040249R9FKED" 0402 4605,1670 r0 bottom value=49.9
R119 "CRCW040210R0JNED" 0402 3885,1670 r0 bottom value=10
R121 "CRCW040249K9FKED" 0402 6350,280 r0 bottom value=49.9k
R122 "RC0402FR-07220KL" 0402 6220,260 r180 top value=220k
R123 "CRCW040230K0FKED" 0402 6323.62,260 r180 top value=30.0k
R124 "CRCW060310K0FKEA" 0603 3490,3510 r90 bottom value=10.0k
R125 "CRCW060310K0FKEA" 0603 6260.24,2537.17 r90 bottom value=10.0k
R126 "CRCW040230K0FKED" 0402 6190,280 r0 bottom value=30.0k
R132 "CRCW0603200RFKEA" 0603 2790,2420 r270 bottom value=200
R134 "CRCW04021K00JNED" 0402 3630,2540 r180 bottom value=1.0k
R136 "CRCW04021K00JNED" 0402 3410,2590 r180 bottom value=1.0k
R137 "CRCW04020000Z0ED" 0402 6094.25,1838.43 r90 top value=0
R139 "CRCW04020000Z0ED" 0402 6045.04,1838.43 r90 top value=0
R143 "CRCW06030000Z0EA" 0603 6336.38,1834.49 r90 top value=0
R144 "CRCW04020000Z0ED" 0402 6530,2520 r90 bottom value=0
R145 "CRCW060310R0JNEAHP" 0603 6270.08,2635.59 r0 bottom value=10
R147 "CRCW06030000Z0EA" 0603 6270.08,2694.65 r180 bottom value=0
R150 "CRCW1206330KJNEA" 1206 2280,1760 r180 bottom value=330k
R151 "CRCW1206330KJNEA" 1206 2280,2130 r180 bottom value=330k
R152 "CRCW1206330KJNEA" 1206 2280,2030 r180 bottom value=330k
R153 "CRCW1206330KJNEA" 1206 2480,1760 r180 bottom value=330k
R154 "CRCW1206330KJNEA" 1206 2480,2130 r180 bottom value=330k
R155 "CRCW1206330KJNEA" 1206 2480,2030 r180 bottom value=330k
R156 "CRCW1206330KJNEA" 1206 2680,1760 r180 bottom value=330k
R157 "CRCW1206330KJNEA" 1206 2680,2130 r180 bottom value=330k
R158 "CRCW1206330KJNEA" 1206 2680,2030 r180 bottom value=330k
R300 "CRCW040210K0JNED" 0402 4930,540 r90 top value=10k
R301 "CRCW040210K0JNED" 0402 4740,530 r90 bottom value=10k
R302 "CRCW040278K7FKED" 0402 4830,1280 r270 top value=78.7k
R303 "ERJPA2F1002X" 0402 4780,1280 r90 top value=10.0k
R304 "CRCW040278K7FKED" 0402 4805,1355 r0 top value=78.7k
R305 "ERJPA2F1002X" 0402 5010,1340 r90 top value=10.0k
R306 "CRCW040256R2FKED" 0402 4760,1030 r90 top value=56.2
R307 "CRCW060310K0FKEA" 0603 5260,420 r90 top value=10.0k
R308 "CRCW040233R2FKED" 0402 4650,1030 r270 top value=33.2
R309 "CRCW040256R2FKED" 0402 4920,1030 r270 top value=56.2
R310 "CRCW060310K0FKEA" 0603 5190,420 r90 top value=10.0k
R311 "CRCW040212K7FKED" 0402 4595,850 r90 bottom value=12.7k
R312 "ERJ-2RKF1002X" 0402 4530,850 r270 bottom value=10.0k
R317 "CRCW040246R4FKED" 0402 5550,1025 r180 top value=46.4
R318 "CRCW04020000Z0ED" 0402 5655,1025 r0 top value=0
R328 "CRCW04027K50FKED" 0402 4650,520 r180 top value=7.50k
R329 "CRCW04027K50FKED" 0402 4500,1030 r270 top value=7.50k
R334 "CRCW04024K99FKED" 0402 5340,520 r90 top value=4.99k
R337 "CRCW04029K31FKED" 0402 5440,520 r90 top value=9.31k
R340 "CRCW040210K0FKED" 0402 4780,540 r90 top value=10.0k
R341 "CRCW04021M00FKED" 0402 4920,1110 r0 top value=1.00Meg
R347 "ERJPA2F1002X" 0402 4780,1180 r270 top value=10.0k
R348 "CRCW04021M00FKED" 0402 4830,1180 r90 top value=1.00Meg
R350 "RC1206FR-07348KL" 1206 6080.16,981.26 r0 bottom value=348k
R351 "RC1206FR-07348KL" 1206 5883.31,981.26 r0 bottom value=348k
R352 "RC1206FR-07348KL" 1206 5686.46,981.26 r0 bottom value=348k
R353 "ERJPA2F1002X" 0402 5010,1240 r270 top value=10.0k
R354 "RC1206FR-07348KL" 1206 6080.16,819.29 r0 bottom value=348k
R355 "CRCW04027K50FKED" 0402 4555,520 r0 top value=7.50k
R356 "RC1206FR-07348KL" 1206 5883.31,819.29 r0 bottom value=348k
R357 "RC1206FR-07348KL" 1206 5686.46,819.29 r0 bottom value=348k
R358 "CRCW04027K50FKED" 0402 5030,540 r90 top value=7.50k
R359 "ERJ-2RKF1002X" 0402 4365,1185 r90 bottom value=10.0k
R360 "ERJ-2RKF1002X" 0402 4365,1080 r90 bottom value=10.0k
RT100 "B59751B0120A070" TDK_B751 5310,2180 r210 top value="50 ohm"
RT301 "TMP6131DECR" DEC0002A 4740,540 r90 top
RV150 "S10K275E2" VAR_S10K275E2 2620,1320 r0 top
TP101 "Suggest using a net name here" Mill-Max_0312-0-15-15-34-27-10-0 3640,4050 r0 top locked
TP102 "Suggest using a net name here" Mill-Max_0312-0-15-15-34-27-10-0 3440,4050 r0 top locked
TP103 "Suggest using a net name here" Mill-Max_0312-0-15-15-34-27-10-0 3940,4050 r0 top locked
TP104 "Suggest using a net name here" Mill-Max_0312-0-15-15-34-27-10-0 4140,4050 r0 top locked
TP105 "Suggest using a net name here" Mill-Max_0312-0-15-15-34-27-10-0 4640,4050 r0 top locked
TP106 "Suggest using a net name here" Mill-Max_0312-0-15-15-34-27-10-0 4440,4050 r0 top locked
U100 "TMCS1133B8A" DVG0010A-MFG 3850,1305 r0 bottom
U101 "UCC27712DR" D0008A_N 3360.24,2462.09 r180 bottom
U102 "UCC21220DR" D0016B 6271.42,2043.15 r90 top
U104 "AMC1306M05DWV" DWV0008A 4280,1645 r0 bottom
U105 "TLV71333PQDBVRQ1" DBV0005A_N 4550,1350 r270 bottom
U106 "UCC27511DBVR" DBV0006A_N 6417.72,2637.56 r0 bottom
U107 "TPSM863252RDX" RDX0007A-MFG 6280,400 r180 top
U300 "LMV797MM/NOPB" DGK0008A_N 4920,1260 r270 top
U301 "SN74LV1T125DBVR" DBV0005A_N 4620,1750 r0 top
U302 "OPA2376AID" D0008A_N 4505,1052.28 r90 bottom
U303 "SN74LV1T125DBVR" DBV0005A_N 4815,1750 r0 top
U307 "REF2033AIDDCR" DDC0005A_N 4850,860 r0 bottom
Vout "L" Keystone5000 7100,3790 r90 top value=Red
Vout "1715721" PhoenixContact_1715721 7100,3490 r90 top

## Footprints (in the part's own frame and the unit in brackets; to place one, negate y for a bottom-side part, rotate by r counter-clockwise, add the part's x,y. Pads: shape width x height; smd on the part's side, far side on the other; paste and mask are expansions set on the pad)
0402 [mm] "0402 from SM-752 data"
  rect 0.8x0.6 smd: 1(-0.6,0) 2(0.6,0)
  silkscreen extent -1.22,-0.52 1.22,0.52, body extent -0.55,-0.3 0.55,0.3, height 0.6
0402_065 [mm] "0402"
  rect 0.8x0.6 smd: 1(-0.6,0) 2(0.6,0)
  silkscreen extent -1.22,-0.52 1.22,0.52, body extent -0.55,-0.3 0.55,0.3, height 0.65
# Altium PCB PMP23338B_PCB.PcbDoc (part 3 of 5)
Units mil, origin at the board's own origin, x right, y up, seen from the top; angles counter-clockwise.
Board outline 5708.66 x 4330.71 mil, 6 copper layers (Top Layer, Signal Layer 1, Signal Layer 2, Signal Layer 3, Signal Layer 4, Bottom Layer), stack 65.8 mil thick; 209 components, 108 nets, 629 pads, 390 vias.

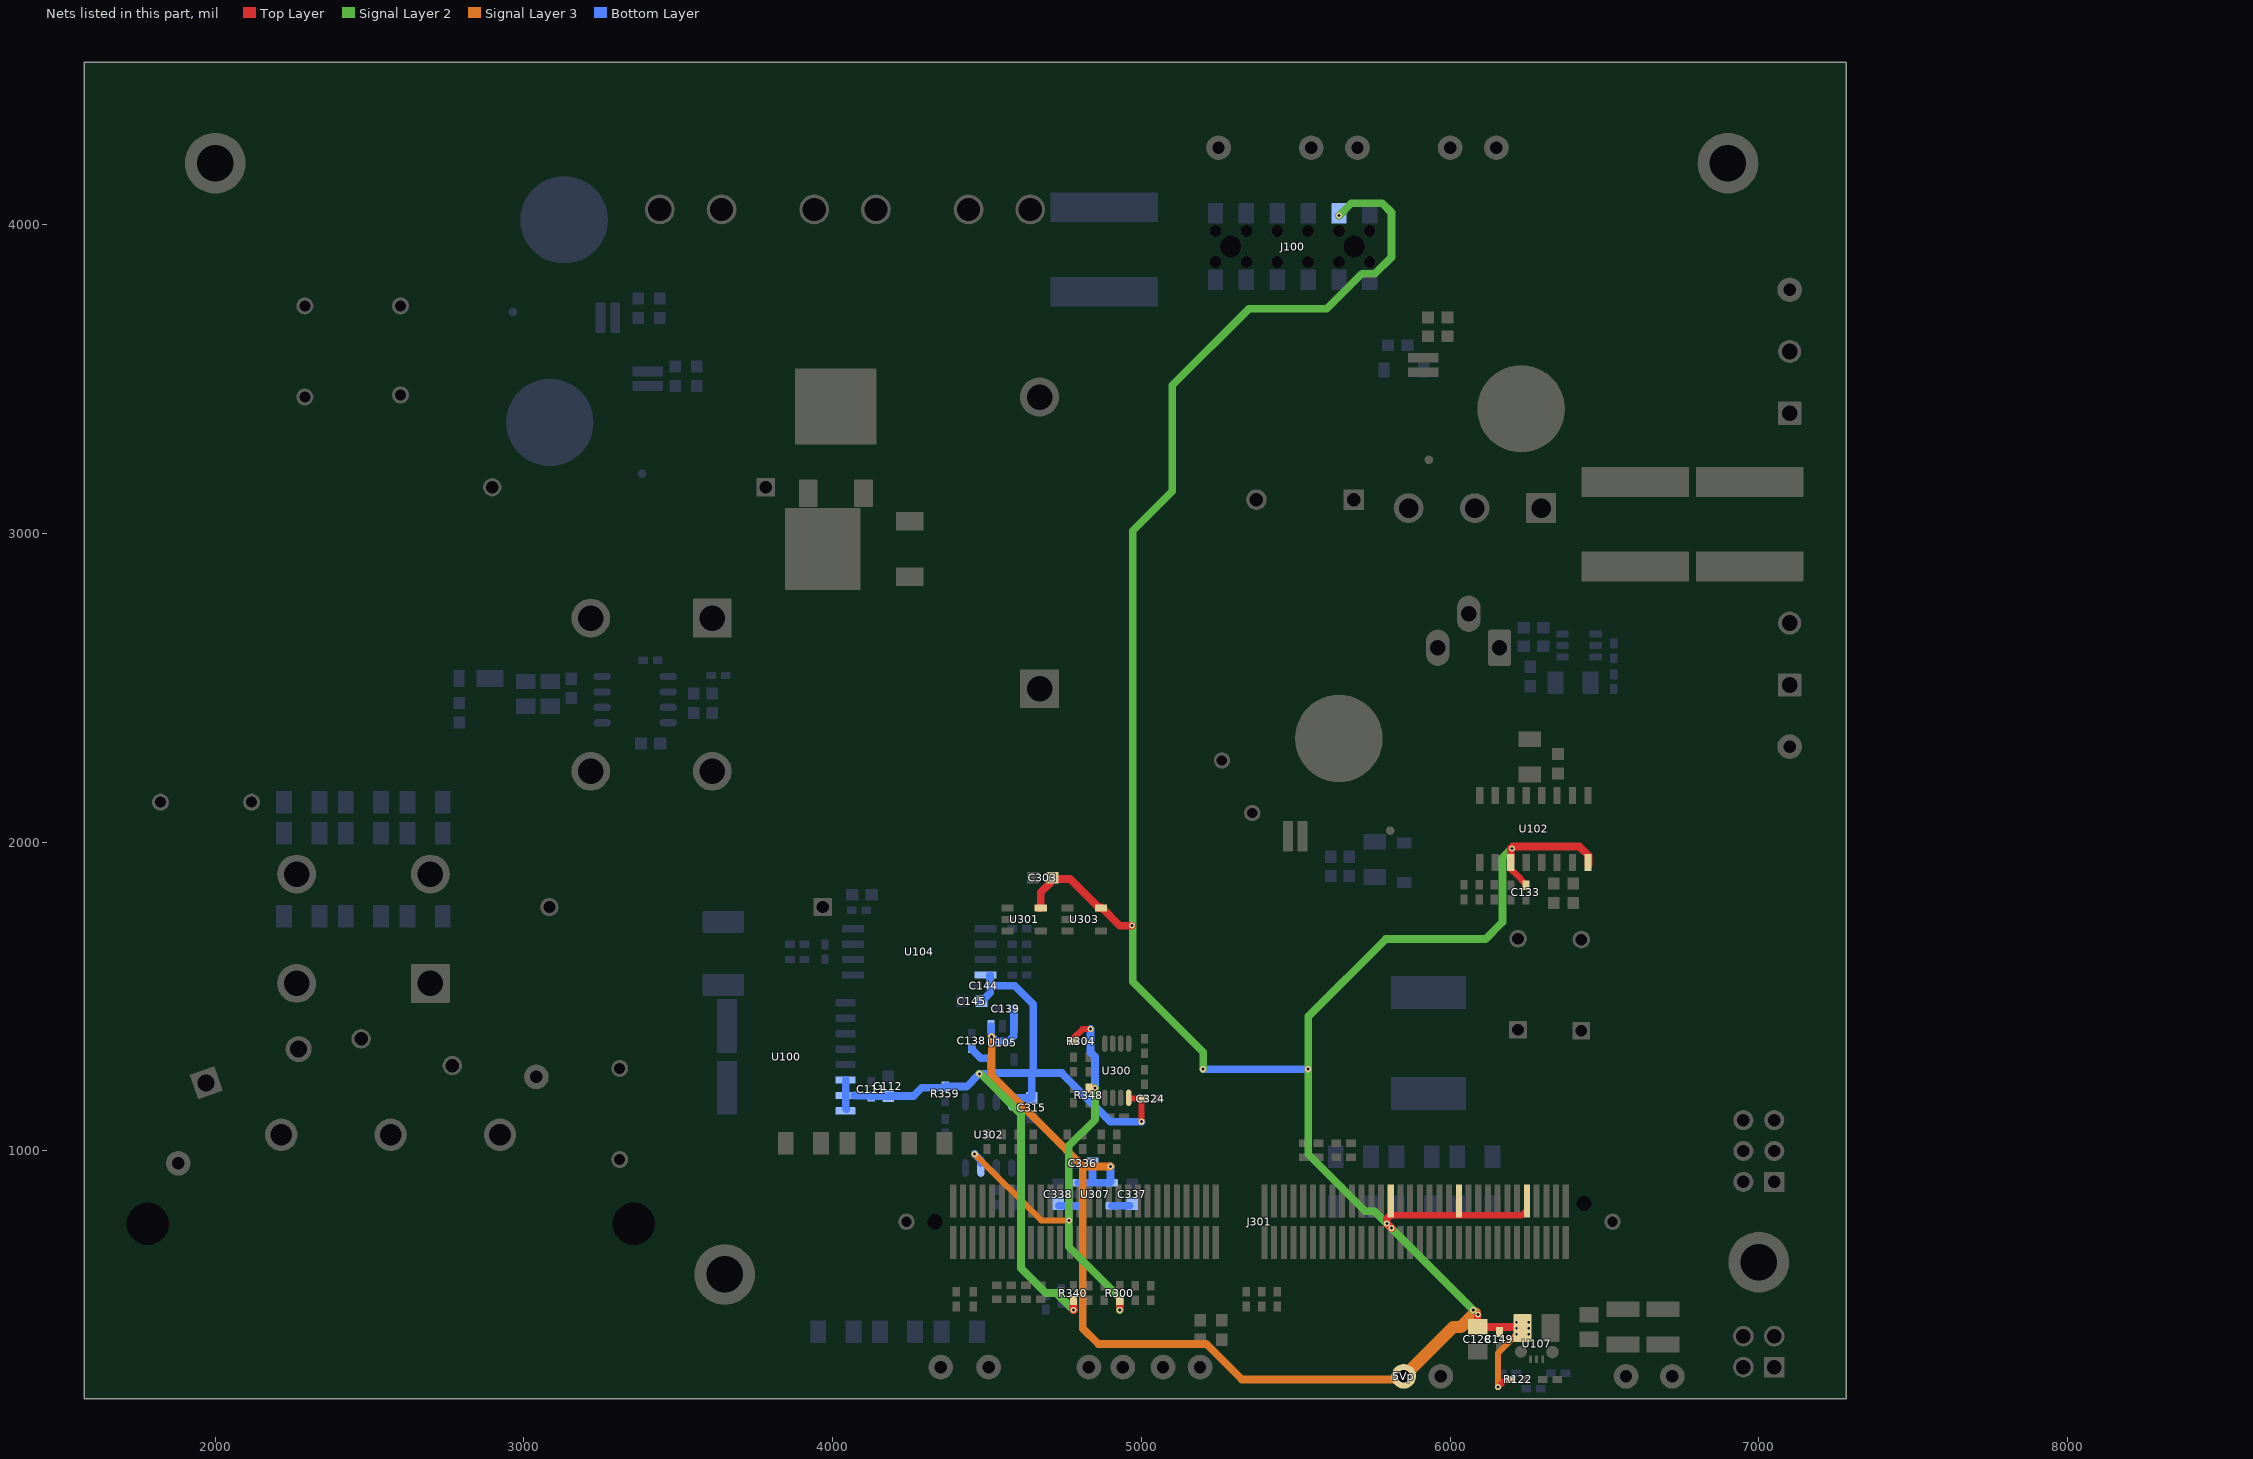
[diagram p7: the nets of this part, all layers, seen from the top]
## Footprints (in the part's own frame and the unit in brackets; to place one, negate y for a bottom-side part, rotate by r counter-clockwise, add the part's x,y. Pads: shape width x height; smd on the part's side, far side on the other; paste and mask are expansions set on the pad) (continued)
0603 [mm] "0603 from SM-752 data"
  rect 1x0.95 smd: 1(-0.8,0) 2(0.8,0)
  silkscreen extent -1.52,-0.69 1.52,0.69, body extent -0.87,-0.47 0.87,0.47, height 1
0805_HV [mil] "0805 with 30mil clearance between pads"
  rect 50x63 smd: 1(-40,0) 2(40,0)
  silkscreen extent -74,-40 74,40, body extent -43,-29 43,29, height 57
1206 [mm] "1206 from SM-752 data"
  rect 1.3x1.85 smd: 1(-1.45,0) 2(1.45,0)
  silkscreen extent -2.4,-1.21 2.4,1.21, body extent -1.7,-0.9 1.7,0.9, height 1.35
1210_270 [mm] "1210"
  rect 1.3x2.7 smd: 1(-1.45,0) 2(1.45,0)
  silkscreen extent -2.32,-1.57 2.32,1.57, body extent -1.7,-1.35 1.7,1.35, height 2.7
B32923_16.5mm_10.5 [mm] "Epcos film capacitors, 22.5mm spacing"
  rect 1.5x1.5 hole 1: 1(-11.25,0)
  round 1.5 hole 1: 2(11.25,0)
  silkscreen extent -13.25,-5.25 13.25,5.25, body extent -13.25,-5.25 13.25,5.25, height 16.5
B32923_29.5mm [mm] "Epcos film capacitors, 22.5mm spacing"
  rect 1.5x1.5 hole 1: 1(-11.25,0)
  round 1.5 hole 1: 2(11.25,0)
  silkscreen extent -13.25,-7.25 13.25,7.25, body extent -13.25,-7.25 13.25,7.25, height 29.5
CONN_QUALTEK-703W-0054 [mil] "AC Receptacle"
  round 105 hole 70: 1(354.33,-395) 2(-354.33,-395) 3(0,-395)
  round 39.37 hole 137.8 unplated: MH1(-787.4,-107.36) MH2(787.4,-107.36)
  silkscreen extent -972,-380 981,452, body extent -972,-477 981,452, height 1130
controlCARD-120HSEC [mm] "Pads are not numbered according to Samtec datasheet."
  rect 0.5x2.724 smd: 1(-23.357,-1.678) 2(-23.357,1.722) 3(-22.557,-1.678) 4(-22.557,1.722) 5(-21.757,-1.678) 6(-21.757,1.722) 7(-20.957,-1.678) 8(-20.957,1.722) 9(-20.157,-1.678) 10(-20.157,1.722) 11(-19.357,-1.678) 12(-19.357,1.722) 13(-18.557,-1.678) 14(-18.557,1.722) 15(-17.757,-1.678) 16(-17.757,1.722) 17(-16.957,-1.678) 18(-16.957,1.722) 19(-16.157,-1.678) 20(-16.157,1.722) 21(-15.357,-1.678) 22(-15.357,1.722) 23(-14.557,-1.678) 24(-14.557,1.722) 25(-13.757,-1.678) 26(-13.757,1.722) 27(-12.957,-1.678) 28(-12.957,1.722) 29(-12.157,-1.678) 30(-12.157,1.722) 31(-11.357,-1.678) 32(-11.357,1.722) 33(-10.557,-1.678) 34(-10.557,1.722) 35(-9.757,-1.678) 36(-9.757,1.722) 37(-8.957,-1.678) 38(-8.957,1.722) 39(-8.157,-1.678) 40(-8.157,1.722) 41(-7.357,-1.678) 42(-7.357,1.722) 43(-6.557,-1.678) 44(-6.557,1.722) 45(-5.757,-1.678) 46(-5.757,1.722) 47(-4.957,-1.678) 48(-4.957,1.722) 49(-4.157,-1.678) 50(-4.157,1.722) 51(-3.357,-1.678) 52(-3.357,1.722) 53(-2.557,-1.678) 54(-2.557,1.722) 55(-1.757,-1.678) 56(-1.757,1.722) 57(2.243,-1.678) 58(2.243,1.722) 59(3.043,-1.678) 60(3.043,1.722) 61(3.843,-1.678) 62(3.843,1.722) 63(4.643,-1.678) 64(4.643,1.722) 65(5.443,-1.678) 66(5.443,1.722) 67(6.243,-1.678) 68(6.243,1.722) 69(7.043,-1.678) 70(7.043,1.722) 71(7.843,-1.678) 72(7.843,1.722) 73(8.643,-1.678) 74(8.643,1.722) 75(9.443,-1.678) 76(9.443,1.722) 77(10.243,-1.678) 78(10.243,1.722) 79(11.043,-1.678) 80(11.043,1.722) 81(11.843,-1.678) 82(11.843,1.722) 83(12.643,-1.678) 84(12.643,1.722) 85(13.443,-1.678) 86(13.443,1.722) 87(14.243,-1.678) 88(14.243,1.722) 89(15.043,-1.678) 90(15.043,1.722) 91(15.843,-1.678) 92(15.843,1.722) 93(16.643,-1.678) 94(16.643,1.722) 95(17.443,-1.678) 96(17.443,1.722) 97(18.243,-1.678) 98(18.243,1.722) 99(19.043,-1.678) 100(19.043,1.722) 101(19.843,-1.678) 102(19.843,1.722) 103(20.643,-1.678) 104(20.643,1.722) 105(21.443,-1.678) 106(21.443,1.722) 107(22.243,-1.678) 108(22.243,1.722) 109(23.043,-1.678) 110(23.043,1.722) 111(23.843,-1.678) 112(23.843,1.722) 113(24.643,-1.678) 114(24.643,1.722) 115(25.443,-1.678) 116(25.443,1.722) 117(26.243,-1.678) 118(26.243,1.722) 119(27.043,-1.678) 120(27.043,1.722)
  round 0.025 hole 1.27 unplated mask+0.876: 181(-24.857,0.022) 182(28.543,1.522)
  round 1.348 hole 0.84: 185(-27.207,0.022) 186(30.893,0.022)
  silkscreen extent -32.11,-3.86 35.8,3.9, body extent -31.75,-3.48 35.3,3.52, height 12.35
D0008A_N [mm] "SOIC, 8-Leads, Body 4.9x3.9mm, Pitch 1.27mm, IPC Medium Density"
  oval 1.45x0.6 smd: 1(-2.725,1.905) 2(-2.725,0.635) 3(-2.725,-0.635) 4(-2.725,-1.905) 5(2.725,-1.905) 6(2.725,-0.635) 7(2.725,0.635) 8(2.725,1.905)
  silkscreen extent -3.3,-2.5 0.9,2.5, body extent -3,-2.45 3,2.45, height 1.63
D0016B [mm] "SOIC-16"
  rrect17% 1.4x0.6 smd: 1(-2.75,4.445) 2(-2.75,3.175) 3(-2.75,1.905) 4(-2.75,0.635) 5(-2.75,-0.635) 6(-2.75,-1.905) 7(-2.75,-3.175) 8(-2.75,-4.445) 9(2.75,-4.445) 10(2.75,-3.175) 11(2.75,-1.905) 12(2.75,-0.635) 13(2.75,0.635) 14(2.75,1.905) 15(2.75,3.175) 16(2.75,4.445)
  body extent -3.01,-4.95 3.01,4.95, height 1.75
DBV0005A_N [mm] "SOT23, 5-Leads, Body 2.9x1.6mm, Pitch 0.95mm, Lead Span 2.8mm, IPC Medium Density"
  rrect17% 1x0.6 smd: 1(-1.375,0.95) 2(-1.375,0) 3(-1.375,-0.95) 4(1.375,-0.95) 5(1.375,0.95)
  silkscreen extent -1.63,-1.55 0.38,1.55, body extent -1.42,-1.46 1.42,1.46, height 1.09
DBV0006A_N [mm] "SOT23, 6-Leads, Body 2.9x1.6mm, Pitch 0.95mm, Lead Span 2.8mm, IPC Medium Density"
  rrect17% 1x0.6 smd: 1(-1.375,0.95) 2(-1.375,0) 3(-1.375,-0.95) 4(1.375,-0.95) 5(1.375,0) 6(1.375,0.95)
  silkscreen extent -1.68,-1.55 0.5,1.55, body extent -1.42,-1.46 1.42,1.46, height 1.12
DDC0005A_N [mm]
  rrect17% 1x0.6 smd: 1(-1.375,0.95) 2(-1.375,0) 3(-1.375,-0.95) 4(1.375,-0.95) 5(1.375,0.95)
  silkscreen extent -1.25,-1.52 0.88,1.57, body extent -1.41,-1.45 1.41,1.45, height 1.1
DEC0002A [mm] "X1SON-2"
  rrect57% 0.35x0.6 smd paste-0.5 mask-0.05: 1(-0.325,0) 2(0.325,0)
  rrect33% 0.3x0.5 on Top Paste: 1S(-0.35,0) 2S(0.35,0)
  body extent -0.5,-0.3 0.5,0.3, height 0.5
DGK0008A_N [mm] "TSOP, 8-Leads, Body 3x3mm, Pitch 0.65mm, IPC Medium Density"
  oval 1.35x0.45 smd: 1(-2.225,0.975) 2(-2.225,0.325) 3(-2.225,-0.325) 4(-2.225,-0.975) 5(2.225,-0.975) 6(2.225,-0.325) 7(2.225,0.325) 8(2.225,0.975)
  silkscreen extent -2.75,-1.55 0.95,1.55, body extent -2.45,-1.5 2.45,1.5, height 0.96
DVG0010A-MFG [mm]
  rrect6% 1.65x4.41 smd paste+0 mask+0: 1(-4.875,2.54) 2(-4.875,-2.54)
  rrect17% 1.65x0.6 smd paste+0 mask+0: 3(4.875,-4.445) 4(4.875,-3.175) 5(4.875,-1.905) 6(4.875,-0.635) 7(4.875,0.635) 8(4.875,1.905) 9(4.875,3.175) 10(4.875,4.445)
  silkscreen extent -6.37,-5.25 3.67,5.25, body extent -5.15,-5.15 5.15,5.15, height 2.65
DWV0008A [mm] "SOIC, 8-Leads, Body 5.95x7.6mm (max), Pitch 1.27mm"
  rrect17% 1.8x0.6 smd: 1(-5.45,1.905) 2(-5.45,0.635) 3(-5.45,-0.635) 4(-5.45,-1.905) 5(5.45,-1.905) 6(5.45,-0.635) 7(5.45,0.635) 8(5.45,1.905)
  silkscreen extent -6.25,-2.95 2.98,2.95, body extent -5.77,-2.92 5.77,2.93, height 2.67
E_900x700x900#1 [mm] "TH, 2- Leads, Body 9x7mm, Pin Spacing 7.5mm"
  round 1.4 hole 0.9: 1(-3.75,0) 2(3.75,0)
  silkscreen extent -4.5,-3.5 4.5,3.5, body extent -4.49,-3.5 4.49,3.5, height 11.96
E_900x700x900#2 [mm] "TH, 2- Leads, Body 9x7mm, Pin Spacing 7.5mm"
  round 1.4 hole 0.9: 1(-3.575,0) 2(3.75,0)
  silkscreen extent -4.5,-3.5 4.5,3.5, body extent -4.49,-3.5 4.49,3.5, height 11.96
FCC_disclaimer [mil]
FP-450HXW180MEFR16X50_RADIAL-MFG [mm]
  rrect7% 1.45x1.45 hole 0.95 paste-1000 mask+0: 1(-3.75,0)
  round 1.45 hole 0.95 paste-1000 mask+0: 2(3.75,0)
  silkscreen extent -8.25,-8.25 8.25,8.25, body extent -8,-52 8,4, height 16.38
FP-0525025.MXEP_vm_AXIAL-MFG [mm]
  rrect5% 2.15x2.15 hole 1.4 paste-1000 mask+0: 1(0,0)
  round 2.15 hole 1.4 paste-1000 mask+0: 2(8.092,0)
  silkscreen extent -3.64,-3.64 3.64,3.64, body extent -3.49,-3.49 8.69,3.49, height 34.52
FP-B58031U5105M062_SMD2-MFG [mm]
  rrect4% 2.45x8.85 smd paste+0 mask+0: 1(-3.475,0) 2(3.475,0)
  silkscreen extent -1.88,-4.18 1.88,4.18, body extent -4.8,-4.52 4.8,4.52, height 0.25
FP-CSS2H-2512K-2L30F_2512-MFG [mm]
  rrect6% 1.8x3.4 smd paste+0 mask+0: 1(-2.6,0) 2(2.6,0)
  silkscreen extent -1.33,-1.63 1.33,1.63, body extent -3.25,-1.53 3.25,1.53, height 1.09
FP-FFA60UA60DN_SC-65-MFG [mm]
  rrect4% 2.45x2.45 hole 1.6 paste-1000 mask+0: 1(-0.325,5.45)
  round 2.45 hole 1.6 paste-1000 mask+0: 2(-0.325,0) 3(-0.325,-5.45)
  silkscreen extent -2.5,-8.1 2.5,8.83, body extent -2.6,-8.2 2.6,8.2, height 0.25
FP-HLE-106-02-G-DV-BE-A_HDR12-MFG [mm]
  rrect8% 1.27x1.68 smd paste+0 mask+0: 1(6.35,-2.72) 2(6.35,2.72) 3(3.81,-2.72) 4(3.81,2.72) 5(1.27,-2.72) 6(1.27,2.72) 7(-1.27,-2.72) 8(-1.27,2.72) 9(-3.81,-2.72) 10(-3.81,2.72) 11(-6.35,-2.72) 12(-6.35,2.72)
  round 0.97 hole 0.97 unplated paste-1000 mask+0: ""(-6.35,-1.27) ""(-6.35,1.27) ""(-3.81,-1.27) ""(-3.81,1.27) ""(-1.27,-1.27) ""(-1.27,1.27) ""(1.27,-1.27) ""(1.27,1.27) ""(3.81,-1.27) ""(3.81,1.27) ""(6.35,-1.27) ""(6.35,1.27)
  round 1.78 hole 1.78 unplated paste-1000 mask+0: ""(-5.08,0) ""(5.08,0)
  silkscreen extent -7.72,-4.4 7.72,2.61, body extent -7.62,-3.29 7.62,3.29, height 3.79
FP-IPT60R080G7XTMA1_HSOF-8-MFG [mm]
  rrect13% 0.8x2.5 smd paste-1000 mask+0: 1(-4.2,-5.35) 2(-3,-5.35)
  round 0.709 smd paste-1000 mask+0: 3-4-5-6-7-8(4.206,-4.881)
  round 7.2 smd paste-1000 mask+0: 9(0,2.7)
  Top Layer region: -4.85,-1.3 4.85,-1.3 4.85,2.4 4.35,2.4 4.35,5.2 5.05,5.2 5.05,6.7 -5.05,6.7 -5.05,5.2 -4.35,5.2 -4.35,2.4 -4.85,2.4
  Top Layer region: -2.2,-4.1 4.6,-4.1 4.6,-6.6 3.8,-6.6 3.8,-4.6 3.4,-4.6 3.4,-6.6 2.6,-6.6 2.6,-4.6 2.2,-4.6 2.2,-6.6 1.4,-6.6 1.4,-4.6 1,-4.6 1,-6.6 0.2,-6.6 0.2,-4.6 -0.2,-4.6 -0.2,-6.6 -1,-6.6 -1,-4.6 -1.4,-4.6 -1.4,-6.6 -2.2,-6.6 -2.2,-4.1
  body extent -4.95,-5.79 4.95,5.89, height 2.31
FP-PAC6270NL_PTH_TRANSFORMER_30MM0_19MM0-MFG [mm]
  rrect3% 3.2x3.2 hole 2.1 paste-1000 mask+0: 1(-5,-6.3)
  round 3.2 hole 2.1 paste-1000 mask+0: 2(5,-6.3) 3(5,6.3) 4(-5,6.3)
  silkscreen extent -15,-10.12 15,9.5, body extent -15.1,-9.6 15.1,9.6, height 0.25
FP-PAC6280NL_PTH_25MM0_12MM5-MFG [mm]
  rrect4% 3.2x3.2 hole 2.1 paste-1000 mask+0: 1(5.5,-4.5)
  round 3.2 hole 2.1 paste-1000 mask+0: 2(-5.5,-4.5) 3(-5.5,4.5) 4(5.5,4.5)
  silkscreen extent -12.5,-7 12.5,6.25, body extent -12.6,-6.35 12.6,6.35, height 0.25
FP-PAL6269NL_PTH_32MM0_27MM8-MFG [mm]
  rrect4% 3.2x3.2 hole 2.1 paste-1000 mask+0: 1(0,12)
  round 3.2 hole 2.1 paste-1000 mask+0: 2(0,-12)
  silkscreen extent -16,-13.9 16,14.67, body extent -16.1,-14 16.1,14, height 0.25
FP-PAL6281.104NL_PTH_20MM5_11MM0-MFG [mm]
  rrect6% 1.7x1.7 hole 1.1 paste-1000 mask+0: 1(0,4)
  round 1.7 hole 1.1 paste-1000 mask+0: 2(0,-4)
  silkscreen extent -10.25,-5.5 10.25,6.13, body extent -10.35,-5.6 10.35,5.6, height 0.25
"FP-VS-15AWL06FN-M3_D-PAK (TO-252AA)-MFG" [mm]
  rrect7% 1.524x2.28 smd paste+0 mask+0: 1(-2.28,-4.56) 3(2.28,-4.56)
  rrect2% 6.74x6.23 smd paste+0 mask+0: 4(0,2.585)
  body extent -3.27,-4.98 3.27,4.93, height 2.53
FP-WSLP3921L1000FEA_3921-MFG [mm]
  rrect4% 2.7x6.2 smd paste+0 mask+0: 1(-4.15,0) 2(4.15,0)
  silkscreen extent -2.42,-2.79 2.42,2.79, body extent -5,-2.6 5,2.6, height 0.88
IEC_HighVoltage_Small [mil]
  silkscreen extent -107,-88 107,97
IEC_HotSurface_Small [mil]
  silkscreen extent -107,-93 107,92
Keystone5000 [mil] "For Keystone 500x miniature loop terminals"
  round 80 hole 40: 1(0,0)
  silkscreen extent -52,-52 52,52, body extent -49,-49 49,49, height 182
Keystone5001 [mil] "For Keystone 500x miniature loop terminals"
  round 80 hole 40: 1(0,0)
  silkscreen extent -52,-52 52,52, body extent -49,-49 49,49, height 182
Keystone5003 [mil] "For Keystone 500x miniature loop terminals"
  round 80 hole 40: 1(0,0)
  silkscreen extent -52,-52 52,52, body extent -49,-49 49,49, height 182
Keystone5004 [mil] "For Keystone 500x miniature loop terminals"
  round 80 hole 40: 1(0,0)
  silkscreen extent -52,-52 52,52, body extent -49,-49 49,49, height 182
Mill-Max_0312-0-15-15-34-27-10-0 [mm] "Pin Receptacle, .032-.046\" .075\" Dia, Gold, TH"
  round 2.45 hole 1.905: 1(0,0)
  silkscreen extent -1.52,-1.52 1.52,1.52, body extent -1.15,-1.15 1.16,1.15, height 0.46
PhoenixContact_1715721 [mm] "Phoenix Contact 1715721 used on LM3445 design from Longmont"
  rrect5% 1.905x1.905 hole 1.3: 1(-2.54,0)
  round 1.9 hole 1.3: 2(2.54,0)
  silkscreen extent -5.82,-5.25 5.08,5.2, body extent -5.82,-4.6 5.08,5.2, height 14.2
PowerDI123 [mm] "Diodes Inc recommended land pattern, document number DS30628 Rev. 6-2"
  rect 2.2x1.4 smd: 1(-1.275,0)
  rect 0.9x1.4 smd: 2(1.275,0)
  silkscreen extent -3.1,-1.09 1.76,1.09, body extent -2.37,-0.96 1.53,0.97, height 1
RDX0007A-MFG [mm]
  round 1.025 smd paste-1000 mask-1000: 1(-1.312,1.312)
  rrect13% 1.5x2.3 smd paste-1000 mask-1000: 2(-1.15,-0.675) 3(1.15,-0.675)
  round 0.991 smd paste-1000 mask-1000: 4(1.281,1.276)
  rrect45% 0.22x0.6 smd paste+0 mask-1000: 5(0.5,1.9) 6(0,1.9) 7(-0.5,1.9)
  Top Layer region: 1.9,1.8 1.892,1.838 1.871,1.871 1.838,1.892 1.8,1.9 1.8,1.9 0.925,1.9 0.887,1.892 0.854,1.871 0.833,1.838 0.825,1.8 0.825,1.8 0.825,1.634 0.818,1.596 0.796,1.563 0.796,1.563 0.507,1.274 0.474,1.252 0.436,1.245 0.436,1.245 0.39,1.245 0.352,1.237 0.319,1.216 0.298,1.183 0.29,1.145 0.29,1.145 0.29,0.825 0.298,0.787 0.319,0.754 0.352,0.733 0.39,0.725 0.39,0.725 1.8,0.725 1.838,0.733 1.871,0.754 1.892,0.787 1.9,0.825 1.9,0.825
  Top Layer region: -1.9,1.8 -1.887,1.85 -1.85,1.887 -1.8,1.9 -1.8,1.9 -0.925,1.9 -0.887,1.892 -0.854,1.871 -0.833,1.838 -0.825,1.8 -0.825,1.8 -0.825,1.634 -0.818,1.596 -0.796,1.563 -0.796,1.563 -0.507,1.274 -0.474,1.252 -0.436,1.245 -0.436,1.245 -0.39,1.245 -0.34,1.232 -0.303,1.195 -0.29,1.145 -0.29,1.145 -0.29,0.825 -0.298,0.787 -0.319,0.754 -0.352,0.733 -0.39,0.725 -0.39,0.725 -1.8,0.725 -1.838,0.733 -1.871,0.754 -1.892,0.787 -1.9,0.825 -1.9,0.825
  Keep-Out Layer region: -0.2,0.675 0.2,0.675 0.2,1.295 -0.2,1.295
  silkscreen extent -2.53,-2.17 2.07,2.37, body extent -2,-2.1 2,2.3, height 0.25
SOD-123FL [mm] "Copied from SOD-123"
  rect 0.915x1.22 smd: 1(-1.637,0) 2(1.637,0)
  silkscreen extent -2.74,-1.16 1.68,1.16, body extent -1.9,-0.9 1.9,0.9, height 1
Sullins_PBC03DAAN [mm] "Sullins 100mil, 2x3, 230 mil above insulator"
  rect 1.65x1.65 hole 1.016: 1(-1.27,2.54)
  round 1.65 hole 1.016: 2(1.27,2.54) 3(-1.27,0) 4(1.27,0) 5(-1.27,-2.54) 6(1.27,-2.54)
  silkscreen extent -2.67,-3.81 2.54,4.58, body extent -2.54,-3.81 2.54,3.81, height 8.38
Sullins_PxC02DAAN [mm] "Header, 2.54mm, 2x2, TH"
  rect 1.7x1.7 hole 1.2: 1(-1.27,1.27)
  round 1.7 hole 1.2: 2(1.27,1.27) 3(-1.27,-1.27) 4(1.27,-1.27)
  silkscreen extent -2.61,-2.8 2.61,3.2, body extent -2.61,-2.8 2.61,2.8, height 8.58
TDK_B751 [mm] "TH, 2-Leads, Dia 12.5mm, Pin Spacing 5mm"
  round 1.35 hole 0.85: 1(0,2.5) 2(0,-2.5)
  silkscreen extent -3.5,-6.25 3.5,6.25, body extent -3.48,-6.2 3.48,6.25, height 16.49
TO-220AB [mil] "Copied from Altium's version of TO3B"
  rrect25% 76x118.11 hole 50: 1(-100,0)
  oval 76x118.11 hole 50: 2(0,-110) 3(100,0)
  silkscreen extent -221,-59 221,126, body extent -221,-59 221,126, height 765
VAR_S10K275E2 [mm] "EPCOS"
  round 1.6 hole 1.1: 1(-3.75,1.1) 2(3.75,-1.1)
  silkscreen extent -6,-2.7 6,2.7, body extent -5.98,-2.7 5.98,2.7, height 14.99
WEEE_Minimum [mil] "WEEElie bin"
  silkscreen extent -95,-172 99,104

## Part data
5Vp 12Vp: "Test Point, Miniature, Red, TH", Color=Red, Manufacturer=Keystone, Supplier Part Number 1=36-5000-ND
C100 C101 C122 C336 C337 C338: "CAP, CERM, 0.1uF, 25V, +/-5%, X7R, 0603", Cap_Case=0603, Manufacturer=AVX, Supplier Part Number 1=478-3713-1-ND, TempCo=X7R, Tolerance_%=5, Value1="0.05 ohm", Value2=25V, ValueDisplayed=0.1µF
C102 C103 C108 C109: "CAP, CERM, 2200 pF, 300 V, +/- 20%, E, TH, 2- Leads, Body 9x7mm, Pin Spacing 7.5mm", Cap_Case=9x7x9mm, Manufacturer=MuRata, Supplier Part Number 1=DE6E3KJ222MN3A-ND, TempCo=E, Tolerance_%=20, Value1=Unknown, Value2=300V, ValueDisplayed=2200pF
C104 C107 C121: library part CMP-0091050-1, "TDK 1µF Multilayer Ceramic Capacitor MLCC 500V dc ±20% SMD", Digikey Part Number=495-75234-1-ND, Manufacturer=TDK, Mouser Part Number=871-B58031U5105M062, Operating Temperature Range="-40°C to +150°C", Tolerance_%=20%, ValueDisplayed=1uF
C105: library part CMP-0012429-3, "CAP FILM 0.47UF 10% 630VDC RAD", Manufacturer=TDK, Tolerance_%=20%, Value1=Unknown, Value2=305VAC, ValueDisplayed=0.47uF
C106: library part CMP-0012424-1, "CAP FILM 1.5UF 10% 630VDC RADIAL", Manufacturer=TDK, Tolerance_%=20%, Value1=Unknown, Value2=305VAC, ValueDisplayed=1.5uF
C110 C113: "CAP, CERM, 10uF, 16V, +/-20%, X5R, 0805", Cap_Case=0805, Manufacturer=AVX, Supplier Part Number 1=1582704, TempCo=X5R, Tolerance_%=20, Value1=Unknown, Value2=16V, ValueDisplayed=10uF
C111 C138 C139: "CAP, CERM, 0.1uF, 6.3V, +/-10%, X7R, 0402", Cap_Case=0402, Manufacturer=MuRata, Supplier Part Number 1=GRM155R70J104KA01D-ND, TempCo=X7R, Tolerance_%=10, Value1=Unknown, Value2=6.3V, ValueDisplayed=0.1uF
C112: "CAP, CERM, 1uF, 6.3V, +/-10%, X5R, 0603", Cap_Case=0603, Manufacturer=MuRata, Supplier Part Number 1=81-GRM185R60J105KE26, TempCo=X5R, Tolerance_%=10, Value1=Unknown, Value2=6.3V, ValueDisplayed=1µF
C114 C120: library part CMP-0098127-1, "180 µF 450 V Aluminum Electrolytic Capacitors Radial, Can 3000 Hrs @ 105°C", Digikey Part Number=1189-450HXW180MEFR16X50-ND, Leakage Current=853.8uA, Manufacturer=Rubycon, Mouser Part Number=232-450HXW180MEFR16X, Operating Temperature Range="-40°C to +105°C", Tolerance_%=20%, ValueDisplayed=180uF
C115 C303: "CAP, CERM, 1uF, 25V, +/-10%, X7R, 0603", Cap_Case=0603, Manufacturer=TDK, Supplier Part Number 1=445-5956-1-ND, TempCo=X7R, Tolerance_%=10, Value1=Unknown, Value2=25V, ValueDisplayed=1uF
C117 C118: "CAP, CERM, 1000 pF, 50 V, +/- 10%, C0G/NP0, 0603", Cap_Case=0603, Manufacturer=AVX, Supplier Part Number 1=478-3718-1-ND, TempCo=C0G/NP0, Tolerance_%=10, Value1="0.048 ohm", Value2=50V, ValueDisplayed=1000pF
C119: "CAP, CERM, 0.01uF, 50V, +/-10%, X7R, 0603", Cap_Case=0603, Manufacturer=Kemet, Supplier Part Number 1=399-5346-1-ND, TempCo=X7R, Tolerance_%=10, Value1=Unknown, Value2=50V, ValueDisplayed=0.01µF
C124 C125 C136: "CAP, CERM, 100 pF, 16 V,+/- 10%, X7R, 0402", Cap_Case=0402, Manufacturer=AVX, Supplier Part Number 1=478-7887-1-ND, TempCo=X7R, Tolerance_%=10, Value2=16V, ValueDisplayed=100pF
C126: "CAP, CERM, 47 µF, 16 V, +/- 10%, X5R, 1210", Cap_Case=1210, Manufacturer=MuRata, Supplier Part Number 1=GRM32ER61C476KE15L-ND, TempCo=X5R, Tolerance_%=10, Value1=Unknown, ValueDisplayed=47µF
C127: library part CMP-0007728-2, "CAP, CERM, 1 uF, 25 V, +/- 10%, X7R, 0805", Cap_Case=0805, Manufacturer=Kemet, Supplier Part Number 1=399-8004-1-ND, TempCo=X7R, Tolerance_%=10%, Value1=Unknown, Value2=25V, ValueDisplayed=1uF
C128: library part CMP-0007989-2, "CAP, CERM, 22 uF, 6.3 V, +/- 10%, X5R, 0805", Cap_Case=0805, Manufacturer="Samsung Electro-Mechanics", TempCo=X5R, Tolerance_%=10%, Value1=Unknown, Value2=6.3V, ValueDisplayed=22uF
C129 C145: library part CMP-0007134-5, "CAP, CERM, 2.2 uF, 6.3 V, +/- 10%, X7R, AEC-Q200 Grade 1, 0603", Cap_Case=0603, Manufacturer=MuRata, Supplier Part Number 1=490-5316-1-ND, TempCo=X7R, Tolerance_%=10%, Value1=Unknown, Value2=6.3V, ValueDisplayed=2.2uF
C131 C137: "CAP, CERM, 1 µF, 25 V,+/- 10%, X7R, 1206", Cap_Case=1206, Manufacturer=TDK, Supplier Part Number 1=445-1592-1-ND, TempCo=X7R, Tolerance_%=10, Value1="0.01 ohm", Value2=25V, ValueDisplayed=1µF
C132: library part CMP-0007402-1, "CAP, CERM, 1000 pF, 25 V, +/- 10%, X7R, 0603", Cap_Case=0603, Manufacturer=MuRata, Supplier Part Number 1=GRM188R71E102KA01D-ND, TempCo=X7R, Tolerance_%=10%, Value1=Unknown, Value2=25V, ValueDisplayed=1000pF
C133: "CAP, CERM, 0.1 µF, 16 V,+/- 10%, X7R, 0402", Cap_Case=0402, Manufacturer=AVX, Supplier Part Number 1=478-7888-1-ND, TempCo=X7R, Tolerance_%=10, Value2=16V, ValueDisplayed=0.1µF
C135: library part CMP-0006530-2, "CAP, CERM, 0.01 uF, 6.3 V, +/- 10%, X5R, 0402", Cap_Case=0402, Manufacturer=MuRata, Supplier Part Number 1=GRM155R60J103KA01D-ND, TempCo=X5R, Tolerance_%=10%, Value1=Unknown, Value2=6.3V, ValueDisplayed=0.01uF
C142 C144 C149: library part CMP-0006211-1, "CAP, CERM, 0.1 uF, 16 V, +/- 10%, Unknown, 0402", Cap_Case=0402, Manufacturer="AT Ceramics", Supplier Part Number 1=1284-1000-1-ND, TempCo=Unknown, Tolerance_%=10%, Value2=16V, ValueDisplayed=0.1uF
C146 C147 C307 C309: library part CMP-0064914-1, "CAP, CERM, 10 pF, 10 V,+/- 2.5%, C0G/NP0, 0402", Cap_Case=0402, Manufacturer=Kemet, Supplier Part Number 1=399-8939-1-ND, TempCo=C0G/NP0, Tolerance_%=2.5%, Value1=Unknown, Value2=10V, ValueDisplayed=10pF
C148: library part CMP-0009211-1, "CAP, CERM, 47 uF, 16 V, +/- 10%, X5R, 1210", Cap_Case=1210, Manufacturer=MuRata, Supplier Part Number 1=GRM32ER61C476KE15L-ND, TempCo=X5R, Tolerance_%=10%, Value1=Unknown, Value2=16V, ValueDisplayed=47uF
C150: library part CMP-0078218-1, "CAP, CERM, 0.01 µF, 16 V,+/- 10%, X7R, 0402", Cap_Case=0402, Manufacturer=Kemet, Supplier Part Number 1=399-1038-1-ND, TempCo=X7R, Tolerance_%=10%, Value2=16V, ValueDisplayed=0.01µF
C300 C302: "CAP, CERM, 0.1uF, 6.3V, +/-10%, X5R, 0402", Cap_Case=0402, Manufacturer=MuRata, Supplier Part Number 1=GRM155R60J104KA01D-ND, TempCo=X5R, Tolerance_%=10, Value1=Unknown, Value2=6.3V, ValueDisplayed=0.1µF
C301 C304 C305 C306: library part CMP-0064911-2, "CAP, CERM, 10 pF, 50 V,+/- 2.5%, C0G/NP0, AEC-Q200 Grade 1, 0402", Cap_Case=0402, Manufacturer=AVX, Supplier Part Number 1=478-5991-1-ND, TempCo=C0G/NP0, Tolerance_%=2.5%, Value1=Unknown, Value2=50V, ValueDisplayed=10pF
C308: library part CMP-0006616-2, "CAP, CERM, 4700 pF, 50 V, +/- 10%, X5R, 0402", Cap_Case=0402, Manufacturer=MuRata, Supplier Part Number 1=GRM155R61H472KA01D-ND, TempCo=X5R, Tolerance_%=10%, Value1=Unknown, Value2=50V, ValueDisplayed=4700pF
C313 C314 C322 C328 C329: library part CMP-0006320-2, "CAP, CERM, 470 pF, 50 V, +/- 10%, X7R, AEC-Q200 Grade 1, 0402", Cap_Case=0402, Manufacturer=TDK, Supplier Part Number 1=445-6888-1-ND, TempCo=X7R, Tolerance_%=10%, Value1="4.96489 ohm", Value2=50V, ValueDisplayed=470pF
C315: library part CMP-0007040-4, "CAP, CERM, 1 uF, 25 V, +/- 10%, X7R, 0603", Cap_Case=0603, Manufacturer=TDK, Supplier Part Number 1=445-5956-1-ND, TempCo=X7R, Tolerance_%=10%, Value1=Unknown, Value2=25V, ValueDisplayed=1uF
C318: "CAP, CERM, 0.01uF, 6.3V, +/-10%, X7R, 0402", Cap_Case=0402, Manufacturer=MuRata, Supplier Part Number 1=GRM155R70J103KA01D-ND, TempCo=X7R, Tolerance_%=10, Value1=Unknown, Value2=6.3V, ValueDisplayed=0.01uF
C324: library part CMP-0081457-1, "CAP, CERM, 1 µF, 10 V,+/- 20%, X5R, 0402", Cap_Case=0402, Manufacturer="Yageo America", TempCo=X5R, Tolerance_%=20%, Value2=10V, ValueDisplayed=1µF
D101 D105: library part CMP-0028548-2, "Diode, Schottky, 40 V, 1 A, SOD-123FL", Manufacturer="ON Semiconductor", Value1=1A, Value2=0.55V
D103 D107: library part CMP-0086603-1, "DIODE GEN PURPOSE 600V SLIMDPAK", Manufacturer=Vishay
D106: library part CMP-0090872-1, "Diode Array 1 Pair Common Cathode Standard 600V 30A Through Hole TO-3P-3, SC-65-3", Digikey Part Number=FFA60UA60DN-ND, Forward Current=30A, Manufacturer="ON Semiconductor", Max Surge Forward Current=180A, Mouser Part Number=512-FFA60UA60DN, Operating Temperature Range="-65°C to +175°C", Peak Reverse Current=100uA
D109: library part CMP-0076978-2, "Diode, Standard Recovery Rectifier, 600 V, 1 A, PowerDI123", Manufacturer="Diodes Inc.", Value1=1A, Value2=1.1V
DACA DACB: library part CMP-0055140-2, "Test Point, Miniature, Orange, TH", Color=Orange, Manufacturer="Keystone Electronics", Supplier Part Number 1=36-5003-ND
F150: library part CMP-4956-0000-1, "25A AC 450V DC Fuse Cartridge, Ceramic Through Hole 3AB, 3AG, 1/4\" x 1-1/4\" (Axial)", Digikey Part Number=F10249-ND, Fuse Current=25A, Fuse Interrupt Dc Current=10000A, Manufacturer=Littelfuse, Mouser Part Number=576-0525025.MXEP, Operating Temperature Range="-55°C to +125°C"
GaN_FLT HS_FLT HS_TMP LS_TMP: "Test Point, Miniature, Orange, TH", Color=Orange, Manufacturer=Keystone, Supplier Part Number 1=36-5003-ND
HFFET_HS1 HFFET_LS1: library part CMP-0055141-1, "Test Point, Miniature, Yellow, TH", Color=Yellow, Manufacturer=Keystone, Supplier Part Number 1=36-5004-ND
J100: library part CMP-0089984-1, "12 Position Receptacle, Bottom Entry Connector  Surface Mount", Current_A=4.1A, Digikey Part Number=HLE-106-02-G-DV-BE-A-ND, Manufacturer=Samtec, Mouser Part Number=200-HLE10602GDVBEA, Operating Temperature Range="-55°C to +125°C", Voltage_V=400V
J102: "AC Receptacle, 10A 250VAC", Manufacturer="Qualtek Electronics Corporation", Supplier Part Number 1=Q220-ND
J301: library part controlCARD-120HSEC, "C2000 controlCARD-120HSEC connector, SMT", Manufacturer=Samtec
J302: "Header, 2.54mm, 2x2, Gold, TH", Manufacturer="Sullins Connector Solutions", Supplier Part Number 1=S2011E-02-ND
J303: "Header, 100mil, 3x2, Gold, TH", Manufacturer="Sullins Connector Solutions", Supplier Part Number 1=S2011E-03-ND
L100: library part CMP-0091020-1, "Inductor Buck/Boost, Toroid, TH, 22uH 15% 8A", Manufacturer="Pulse Electronics", Operating Temperature Range="-40°C to +125°C", Test Frequency=100kHz, Tolerance_%=15%
L102: library part CMP-0091106-1, "IND, CUR-SENSE, 4MH, 20A, TOR, TH", Manufacturer="Pulse Electronics", Operating Temperature Range="-40°C to +125°C", Voltage_Isolation_Vrms=1500VDC
L103: library part CMP-0091118-1, "Inductor Power 250uH T27 THT", Manufacturer="Pulse Electronics", Operating Temperature Range="-40°C to +125°C", Test Frequency=100kHz, Tolerance_%=15%
L150: library part CMP-0091125-1, "INDUCTOR CUR-SENSE 8.3mH TOR TH", Manufacturer="Pulse Electronics", Operating Temperature Range="-40°C to +125°C", Test Frequency=10kHz, Tolerance_%=30%
Line Vout: library part 5000, "Test Point, Miniature, Red, TH", Manufacturer=Keystone, Supplier Part Number 1=36-5000-ND
LOGO100: library part CMP-0074837-1, "IEC 61010-1 Hot Surface Warning"
LOGO101: library part CMP-0074835-1, "IEC 61010-1 High Voltage Warning"
Logo102: library part CMP-0074847-1, "FCC_disclaimer"
Logo103: library part CMP-0074769-1
Neutral PGND: library part 5001, "Test Point, Miniature, Black, TH", Manufacturer=Keystone, Supplier Part Number 1=36-5001-ND
PGND PGND PGND PGND PGND: "Test Point, Miniature, Black, TH", Color=Black, Manufacturer=Keystone, Supplier Part Number 1=36-5001-ND
PGND Vout: library part CMP-0055471-1, "Terminal Block, 5.08 mm, 2x1, TH", Color=Green, Current_A=17.5A, Manufacturer="Phoenix Contact", Supplier Part Number 1=277-1263-ND, Voltage_V=400V
Q100 Q101 Q102 Q103: library part CMP-0086487-1, "N-Channel 600V 23A (Tc) 390W (Tc) Surface Mount PG-HSOF-8-2", Manufacturer=Infineon
Q104: library part CMP-0001223-3, "MOSFET N-CH 600V 48A TO220-3", Alternate Manufacturer=None, Manufacturer="Infineon Technologies"
R100 R111 R112 R124 R125: "RES, 10.0 k, 1%, 0.1 W, 0603", Manufacturer=Vishay-Dale, Power_W=0.1, Supplier Part Number 1=541-10.0KHCT-ND, TempCo="100 ppm/C", Tolerance_%=1, Value1=1%, Value2=0.1W, Value_Code=10k0, ValueDisplayed=10.0k
R101 R102 R103 R105 R106 R107 R350 R351 R352 R354 R356 R357: library part CMP-0018215-2, "RES, 348 k, 1%, 0.25 W, 1206", Manufacturer="Yageo America", Power_W=250mW, Supplier Part Number 1=311-348KFRCT-ND, TempCo="100 ppm/C", Tolerance_%=1%, Value2=0.25W, Value_Code=348k
R104: "RES, 5.11, 1%, 0.1 W, 0603", Manufacturer=Vishay-Dale, Power_W=0.1, Supplier Part Number 1=541-5.11HHCT-ND, TempCo="100 ppm/C", Tolerance_%=1, Value1=1%, Value2=0.1W, Value_Code=5R11, ValueDisplayed=5.11
R108 R116: "RES, 10.0, 1%, 0.1 W, 0603", Manufacturer=Vishay-Dale, Power_W=0.1, Supplier Part Number 1=541-10.0HCT-ND, TempCo="100 ppm/C", Tolerance_%=1, Value1=1%, Value2=0.1W, Value_Code=10R0, ValueDisplayed=10.0
R109: library part CMP-21571-0000-1, "Res Metal Strip 2512 2.3MilliOhm 1% 5W ±75ppm/°C Molded T/R", Digikey Part Number=118-CSS2H-2512K-2L30FTR-ND, Manufacturer=Bourns, Mouser Part Number=652-CSS2H-2512K2L30F, Operating Temperature Range="-55°C to +170°C", Power_W=5W, TempCo=75ppm/°C, Tolerance_%=1%
R110: "RES, 5.11, 1%, 0.25 W, 1206", Manufacturer=Vishay-Dale, Power_W=0.25, Supplier Part Number 1=541-5.11FFCT-ND, TempCo="100 ppm/C", Tolerance_%=1, Value1=1%, Value2=0.25W, Value_Code=5R11, ValueDisplayed=5.11
R113: library part CMP-0092403-1, "RES 0.0025 OHM 1% 5W 3921", Manufacturer=Vishay, Mouser Part Number=71-WSLP3921L500FEA, Operating Temperature Range="-65°C to +170°C", Power_W=5W, TempCo=350ppm/°C, Tolerance_%=1%
R114 R119: library part CMP-0026827-3, "RES, 10, 5%, 0.063 W, AEC-Q200 Grade 0, 0402", Manufacturer=Vishay-Dale, Power_W=63mW, Supplier Part Number 1=541-10JCT-ND, TempCo="200 ppm/C", Tolerance_%=5%, Value2=0.063W, Value_Code=10R0, ValueDisplayed=10
R117 R318: library part CMP-0026822-3, "RES, 0, 5%, 0.063 W, AEC-Q200 Grade 0, 0402", Manufacturer=Vishay-Dale, Power_W=63mW, Supplier Part Number 1=541-0.0JCT-ND, TempCo="200 ppm/C", Tolerance_%=5%, Value2=0.063W, Value_Code=0000, ValueDisplayed=0
R118: library part CMP-0026404-1, "RES, 49.9, 1%, 0.063 W, 0402", Manufacturer=Vishay-Dale, Power_W=63mW, Supplier Part Number 1=541-49.9LCT-ND, TempCo="100 ppm/C", Tolerance_%=1%, Value2=0.063W, Value_Code=49R9, ValueDisplayed=49.9
R121: library part CMP-0026403-2, "RES, 49.9 k, 1%, 0.063 W, AEC-Q200 Grade 0, 0402", Manufacturer=Vishay-Dale, Power_W=63mW, Supplier Part Number 1=541-49.9KLCT-ND, TempCo="100 ppm/C", Tolerance_%=1%, Value2=0.063W, Value_Code=49k9, ValueDisplayed=49.9k
R122: library part CMP-0026728-1, "RES, 220 k, 1%, 0.0625 W, 0402", Manufacturer="Yageo America", Power_W=62.5mW, Supplier Part Number 1=311-220KLRCT-ND, TempCo="100 ppm/C", Tolerance_%=1%, Value2=0.0625W, Value_Code=220k
R123 R126: library part CMP-0078244-2, "RES, 30.0 k, 1%, 0.063 W, AEC-Q200 Grade 0, 0402", Manufacturer=Vishay-Dale, Power_W=63mW, Supplier Part Number 1=541-30.0KLCT-ND, TempCo="100 ppm/C", Tolerance_%=1%, Value2=0.063W, Value_Code=30k0, ValueDisplayed=30.0k
R132: "RES, 200 ohm, 1%, 0.1W, 0603", Manufacturer=Vishay-Dale, Power_W=0.1, Supplier Part Number 1=541-200HCT-ND, TempCo="100 ppm/C", Tolerance_%=1, Value1=1%, Value2=0.1W, Value_Code=200R
R134 R136: "RES, 1.0k ohm, 5%, 0.063W, 0402", Manufacturer=Vishay-Dale, Power_W=0.063, Supplier Part Number 1=541-1.0KJCT-ND, TempCo="200 ppm/C", Tolerance_%=5, Value1=5%, Value2=0.063W, Value_Code=1k00
R137 R139 R144: "RES, 0, 5%, 0.063 W, 0402", Manufacturer=Vishay-Dale, Power_W=0.063, Supplier Part Number 1=541-0.0JCT-ND, TempCo="200 ppm/C", Tolerance_%=5, Value1=5%, Value2=0.063W, Value_Code=0000, ValueDisplayed=0
R143 R147: "RES, 0, 5%, 0.1 W, 0603", Manufacturer=Vishay-Dale, Power_W=0.1, Supplier Part Number 1=541-0.0GCT-ND, TempCo="200 ppm/C", Tolerance_%=5, Value1=5%, Value2=0.1W, Value_Code=0000, ValueDisplayed=0
R145: "RES, 10, 5%, 0.25 W, 0603", Manufacturer=Vishay-Dale, Power_W=0.25, Supplier Part Number 1=541-10SACT-ND, TempCo="200 ppm/C", Tolerance_%=5, Value1=5%, Value2=0.25W, Value_Code=10R0, ValueDisplayed=10
R150 R151 R152 R153 R154 R155 R156 R157 R158: "RES, 330 k, 5%, 0.25 W, 1206", Manufacturer=Vishay-Dale, Power_W=0.25, Supplier Part Number 1=541-330KECT-ND, TempCo="200 ppm/C", Tolerance_%=5, Value1=5%, Value2=0.25W, Value_Code=330k
R300 R301: "RES, 10k ohm, 5%, 0.063W, 0402", Manufacturer=Vishay-Dale, Power_W=0.063, Supplier Part Number 1=541-10KJCT-ND, TempCo="200 ppm/C", Tolerance_%=5, Value1=5%, Value2=0.063W, Value_Code=10k0
R302 R304: library part CMP-0026551-2, "RES, 78.7 k, 1%, 0.063 W, AEC-Q200 Grade 0, 0402", Manufacturer=Vishay-Dale, Power_W=63mW, Supplier Part Number 1=541-78.7KLCT-ND, TempCo="100 ppm/C", Tolerance_%=1%, Value2=0.063W, Value_Code=78k7, ValueDisplayed=78.7k
R303 R305 R347 R353: library part CMP-0078779-1, "RES, 10.0 k, 1%, 0.2 W, AEC-Q200 Grade 0, 0402", Manufacturer=Panasonic, Power_W=200mW, Supplier Part Number 1=P17230CT-ND, TempCo="100 ppm/C", Tolerance_%=1%, Value2=0.2W, Value_Code=10k0, ValueDisplayed=10.0k
R306 R309: library part CMP-0026454-2, "RES, 56.2, 1%, 0.063 W, AEC-Q200 Grade 0, 0402", Manufacturer=Vishay-Dale, Power_W=63mW, Supplier Part Number 1=541-56.2LCT-ND, TempCo="100 ppm/C", Tolerance_%=1%, Value2=0.063W, Value_Code=56R2, ValueDisplayed=56.2
R307 R310: library part CMP-0021998-4, "RES, 10.0 k, 1%, 0.1 W, AEC-Q200 Grade 0, 0603", Manufacturer=Vishay-Dale, Power_W=100mW, Supplier Part Number 1=541-10.0KHCT-ND, TempCo="100 ppm/C", Tolerance_%=1%, Value2=0.1W, Value_Code=10k0, ValueDisplayed=10.0k
R308: library part CMP-0026299-2, "RES, 33.2, 1%, 0.063 W, AEC-Q200 Grade 0, 0402", Manufacturer=Vishay-Dale, Power_W=63mW, Supplier Part Number 1=541-33.2LCT-ND, TempCo="100 ppm/C", Tolerance_%=1%, Value2=0.063W, Value_Code=33R2, ValueDisplayed=33.2
R311: library part CMP-0025993-3, "RES, 12.7 k, 1%, 0.063 W, AEC-Q200 Grade 0, 0402", Manufacturer=Vishay-Dale, Power_W=63mW, Supplier Part Number 1=541-12.7KLCT-ND, TempCo="100 ppm/C", Tolerance_%=1%, Value2=0.063W, Value_Code=12k7, ValueDisplayed=12.7k
R312 R359 R360: library part CMP-0026658-1, "RES, 10.0 k, 1%, 0.1 W, 0402", Manufacturer=Panasonic, Power_W=100mW, Supplier Part Number 1=P10.0KLCT-ND, TempCo="100 ppm/C", Tolerance_%=1%, Value2=0.1W, Value_Code=10k0, ValueDisplayed=10.0k
R317: library part CMP-0026392-2, "RES, 46.4, 1%, 0.063 W, AEC-Q200 Grade 0, 0402", Manufacturer=Vishay-Dale, Power_W=63mW, Supplier Part Number 1=541-46.4LCT-ND, TempCo="100 ppm/C", Tolerance_%=1%, Value2=0.063W, Value_Code=46R4, ValueDisplayed=46.4
R328 R329 R355 R358: "RES, 7.50 k, 1%, 0.063 W, 0402", Manufacturer=Vishay-Dale, Power_W=0.063, Supplier Part Number 1=541-7.50KLCT-ND, TempCo="100 ppm/C", Tolerance_%=1, Value1=1%, Value2=0.063W, Value_Code=7k50, ValueDisplayed=7.50k
R334: "RES, 4.99 k, 1%, 0.063 W, 0402", Manufacturer=Vishay-Dale, Power_W=0.063, Supplier Part Number 1=541-4.99KLCT-ND, TempCo="100 ppm/C", Tolerance_%=1, Value1=1%, Value2=0.063W, Value_Code=4k99, ValueDisplayed=4.99k
R337: "RES, 9.31 k, 1%, 0.063 W, 0402", Manufacturer=Vishay-Dale, Power_W=0.063, Supplier Part Number 1=541-9.31KLCT-ND, TempCo="100 ppm/C", Tolerance_%=1, Value1=1%, Value2=0.063W, Value_Code=9k31, ValueDisplayed=9.31k
R340: "RES, 10.0 k, 1%, 0.063 W, 0402", Manufacturer=Vishay-Dale, Power_W=0.063, Supplier Part Number 1=541-10.0KLCT-ND, TempCo="100 ppm/C", Tolerance_%=1, Value1=1%, Value2=0.063W, Value_Code=10k0, ValueDisplayed=10.0k
R341 R348: library part CMP-0026100-2, "RES, 1.00 M, 1%, 0.063 W, AEC-Q200 Grade 0, 0402", Manufacturer=Vishay-Dale, Power_W=63mW, Supplier Part Number 1=541-1.00MLCT-ND, TempCo="100 ppm/C", Tolerance_%=1%, Value2=0.063W, Value_Code=1M00, ValueDisplayed=1.00M
RT100: "Thermistor PTC, 50 ohm, 25%, D12.5xH16.5mm", Manufacturer=TDK, Supplier Part Number 1=495-3880-ND, Tolerance_%=25
RT301: library part CMP-0084566-1, "Thermistor, DEC0002A (X1SON-2)", Alternate Manufacturer="Texas Instruments", Alternate PartNumber=TMP6131DECT
RV150: "Varistor 275V RMS 10MM Radial, TH", Manufacturer="EPCOS Inc", Supplier Part Number 1=495-1433-ND
TP101 TP102 TP103 TP104 TP105 TP106: library part 0312-0-15-15-34-27-10-0, "Pin Receptacle, .032-.046\" .075\" Dia, Gold, TH", Manufacturer=Mill-Max, Supplier Part Number 1=0312-015153427100-ND
U100: library part CMP-0097984-1, Manufacturer="Texas Instruments", Operating Temperature Range=to, Part Number=TMCS1133B1QDVGR
U101: library part CMP-0013005-2, "620-V High-Side Low-Side Gate Driver with 2.5A Peak Output and RobustDrive, D0008A (SOIC-8)", Alternate Manufacturer="Texas Instruments", Alternate PartNumber=UCC27712D
U102: library part CMP-0077646-2, "4-A, 6-A, 3.0-kVRMS Isolated Dual-Channel Gate Driver, D0016B (SOIC-16)", Alternate Manufacturer="Texas Instruments", Alternate PartNumber=UCC21220D, Operating Temperature Range="-40 to 125 C", Rating=Catalog
U104: library part CMP-0085668-1, "Small Reinforced Isolated Modulator With +/-50mV Input and CMOS Interface, DWV0008A (SOIC-8)", Alternate Manufacturer="Texas Instruments", Alternate PartNumber=AMC1306M05DWVR, Operating Temperature Range="-40 to 125 C", Rating=Catalog
U105: "Capacitor-Free, 150-mA, Low-Dropout Regulator with Foldback Current Limit for Portable Devices, DBV0005A", Alternate Manufacturer="Texas Instruments"
U106: "Single-Channel High-Speed Low-Side Gate Driver (with 4-A Peak Source and 8-A Peak Sink), DBV0006A", Alternate Manufacturer="Texas Instruments", Alternate PartNumber=UCC27511DBVT
U107: library part CMP-0097277-1, "3V to 16 V Input, 3-A Synchronous Step-Down Voltage Regulator Module, QFN-FCMOD7", Manufacturer="Texas Instruments", Max Supply Voltage=16V, Min Supply Voltage=3V, Nominal Supply Current=120-400uA, Operating Temperature Range="-40°C to +125°C", Output Voltage=0.6-7V, Switching Frequency=1400/2000kHz
U300: library part CMP-0068783-2, "17 MHz, Low Noise, CMOS Input, 1.8V Operational Amplifiers, DGK0008A (VSSOP-8)", Manufacturer="Texas Instruments", Package Reference=DGK0008A
U301 U303: library part CMP-0051320-2, "Single Power Supply, Single BUFFER GATE w/ 3-State Output (active low enable), DBV0005A (SOT-23-5)", F @ Nom Voltage(Max)(Mhz)=50, Generic Part Number=SN74LV1T125, ICC @ Nom Voltage(Max)(mA)=0.01, Manufacturer="Texas Instruments", Operating Temperature Range="-40 to 125 C", Rating=Catalog, tpd @ Nom Voltage(Max)(ns)=14.5,9.5,8.0,6.5, Voltage(Nom)(V)=1.8,2.5,3.3,5.5
U302: library part CMP-0040811-1, "Precision, Low Noise, Low Quiescent Current Operational Amplifier, 2 to 5.5 V, -40 to 125 degC, 8-pin SOIC (D8), Green (RoHS & no Sb/Br)", Manufacturer="Texas Instruments", Total Supply Voltage(Max)(+5V is 5, +/-5V is 10)=5.5, Total Supply Voltage(Min)(+5V is 5, +/-5V is 10)=2
U307: library part CMP-0066190-1, "Low-Drift, Low-Power, Dual-Output VREF and VREF/2 Voltage Reference, DDC0005A (SOT-23-T-5)", Alternate Manufacturer="Texas Instruments", Alternate PartNumber=REF2033AIDDCT

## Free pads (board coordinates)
  round 196.85 hole 118.11: 1(2000,4200) 1(3650,600) 1(6900,4200) 1(7000,640)

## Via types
v1: diameter 20, hole 10, Top Layer to Bottom Layer, 378 vias
v2: diameter 19.68, hole 7.87, Top Layer to Bottom Layer, 12 vias

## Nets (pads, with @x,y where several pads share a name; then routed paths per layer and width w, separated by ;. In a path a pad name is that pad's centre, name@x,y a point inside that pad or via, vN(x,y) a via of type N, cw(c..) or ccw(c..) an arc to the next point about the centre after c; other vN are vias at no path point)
1V65: C338.2 R300.1 R304.1 R348.2 U302.3 U307.1 | length 1677.4
  Top Layer w20: R304.1@4780,1365 4810,1395 v1(4835,1395) ; R348.2@4830,1205 4830.68,1204.32 v1(4849.32,1204.32) ; v1(4930,485) R300.1@4930,515
  Signal Layer 2 w25: v1@4850,1205 4850,1101.72 4765,1016.72 v1(4765,775) 4765,690 4930,525 v1(4930,485)
  Signal Layer 3 w20: v1(4460,990) 4675,775 v1(4765,775)
  Bottom Layer w25: v1(4460,990) 4480,970 U302.3@4480,960 ; C338.2@4732.6,822.6 U307.1@4795.87,822.6 ; v1(4765,775) 4765,820 ; v1(4835,1395) 4835,1320 4850,1305 v1@4850,1205
3V3: C111.1 C112.1 C138.1 C144.1 C145.1 C315.1 C324.1 R340.1 R359.2 U100.8 U100.9 U100.10 U104.8 U105.5 U300.8 U302.8 | length 2916.6
  Top Layer w20: U300.8@4960,1170 C324.1@5006.38,1170 ; v1(5000,1095) C324.1@5000,1165
  Top Layer w25: v1(4780,485) R340.1@4780,515
  Signal Layer 2 w25: v1(4475,1250) 4480,1250 4610,1120 4610,620 4690,540 4725,540 v1(4780,485)
  Bottom Layer w25: U100.9@4041.93,1180 4041.93,1138.07 U100.10@4045,1135 ; U100.9@4041.93,1188.07 U100.8@4041.93,1230 ; U100.9@4070,1180 4121.38,1180 4121.75,1179.63 C111.1@4124.31,1179.63 ; C111.1@4125,1176.38 4125,1176.75 4125.69,1177.44 C112.1@4177.44,1177.44 ; C112.1@4180,1178.5 4262.35,1178.5 4288.85,1205 R359.2@4365,1205 ; R359.2@4365,1208.62 4433.62,1208.62 v1(4475,1250) 4515,1250 4512.6,1252.4 ; C138.1@4450,1332.76 4450,1330.2 4480.2,1300 U105.5@4510,1300 ; C145.1@4481.5,1485 4482.48,1485 4510,1512.52 C144.1@4510,1530 ; U104.8@4509.69,1569.31 4509.69,1535 4590,1535 4650,1475 4650,1255 ; U105.5@4512.6,1295.87 4512.6,1252.4 ; U302.8@4580.69,1171.5 C315.1@4645,1171.5 4645,1252.4 ; 4642.4,1252.4 4512.6,1252.4 ; 4645,1255 4645,1252.4 ; v1(5000,1095) 4900,1095 4742.6,1252.4 4645,1252.4
3V3ref: C337.2 U307.5 | length 58.5
  Bottom Layer w25: U307.5@4904.13,822.6 C337.2@4962.6,822.6
5Vp: 5Vp.1 C128.1 C133.1 C139.1 C149.1 C303.2 C336.2 J100.10 J301.84 J301.98 J301.112 R122.2 U102.3 U102.8 U105.1 U105.3 U107.3 U301.5 U303.5 U307.3 U307.4 | length 11007.3
  Top Layer w20: J301.84@5807.76,837.8 5807.91,837.64 J301.84@5807.91,797.09 ; J301.84@5811.77,791.77 J301.98@6028.23,791.77 ; J301.98@6028.23,837.8 J301.98@6028.23,791.77 ; v1(6155,235) 6180,260 R122.2@6195,260 ; U102.3@6196.42,1934.88 6196.42,1913.43 6212.36,1897.48 ; 6212.57,1897.69 6245.83,1864.44 C133.1@6245.83,1861.06 ; J301.112@6248.7,837.8 6248.7,808.7 6231.77,791.77 J301.98@6028.23,791.77
  Top Layer w25: U301.5@4666.95,1788.09 4667.64,1787.4 U301.5@4674.13,1787.4 4674.13,1838.09 4704.31,1868.27 4704.31,1878.8 4710.51,1885 C303.2@4711.5,1885 C303.2@4715,1885 ; C303.2@4715,1881.36 4768.68,1881.36 4862.64,1787.4 U303.5@4869.13,1787.4 ; U303.5@4870.87,1789.13 4930,1730 v1(4970,1730) ; J301.84@5805,790 5795,780 v1(5795,765) v1(5810,750) ; C128.1@6090,430 U107.3@6240,430 ; C128.1@6090,450 v1(6090,470) ; U102.3@6196.42,1934.88 v1@6196.42,1979.96 ; v1@6202.52,1986.06 6419.06,1986.06 6448.58,1956.54 U102.8@6448.58,1927.01
  Signal Layer 2 w25: v1(5200,1265) 5200.5,1265.5 5200.5,1319.5 4972,1548 4972,3008.75 5100,3136.75 5100,3480 5348.68,3728.68 5600.4,3728.68 5711.72,3840 5715,3840 ; v1(5640,4030) 5680,4070 5780,4070 5810,4040 5810,3895.42 5755.99,3841.41 5715,3841.41 ; v1(6075,485) v1(5810,750) 5755,805 5725.63,805 5540.63,990 5540.63,1435.63 5791.5,1686.5 6114.59,1686.5 6169.5,1741.41 6169.5,1949.5 v1(6200,1980)
  Signal Layer 3 w20: v1(6155,235) 6155,345 v2@6215,405
  Signal Layer 3 w25: v1(4515,1370) 4515,1245 4810,950 ; 4810,700 4810,425 4860,375 5210,375 5325,260 5Vp.1@5845,260 ; 4810,703.03 4810,950 ; v1(4900,950) 4810,950
  Signal Layer 3 w40: 5Vp.1@5850,270 6010,430 6035,430 6080,475
  Bottom Layer w25: U105.1@4512.6,1404.13 4513.29,1403.44 v1@4513.29,1370 ; v1(4515,1370) 4530,1355 4565,1355 ; 4570,1355 4586.71,1371.71 4586.71,1403.44 U105.3@4587.4,1404.13 C139.1@4587.4,1464.11 ; U307.3@4795.87,897.4 U307.4@4897.4,897.4 ; 4841.5,901.5 C336.2@4841.5,960 ; U307.4@4900,900 v1(4900,950) ; v1(5200,1265) v1(5540,1265)
  other v2: 6215.04,406.5 6254.41,406.5 6215.04,426.18 6254.41,426.18 6215.04,445.87 6254.41,445.87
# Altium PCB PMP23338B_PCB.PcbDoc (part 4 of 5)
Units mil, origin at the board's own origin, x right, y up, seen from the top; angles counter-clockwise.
Board outline 5708.66 x 4330.71 mil, 6 copper layers (Top Layer, Signal Layer 1, Signal Layer 2, Signal Layer 3, Signal Layer 4, Bottom Layer), stack 65.8 mil thick; 209 components, 108 nets, 629 pads, 390 vias.

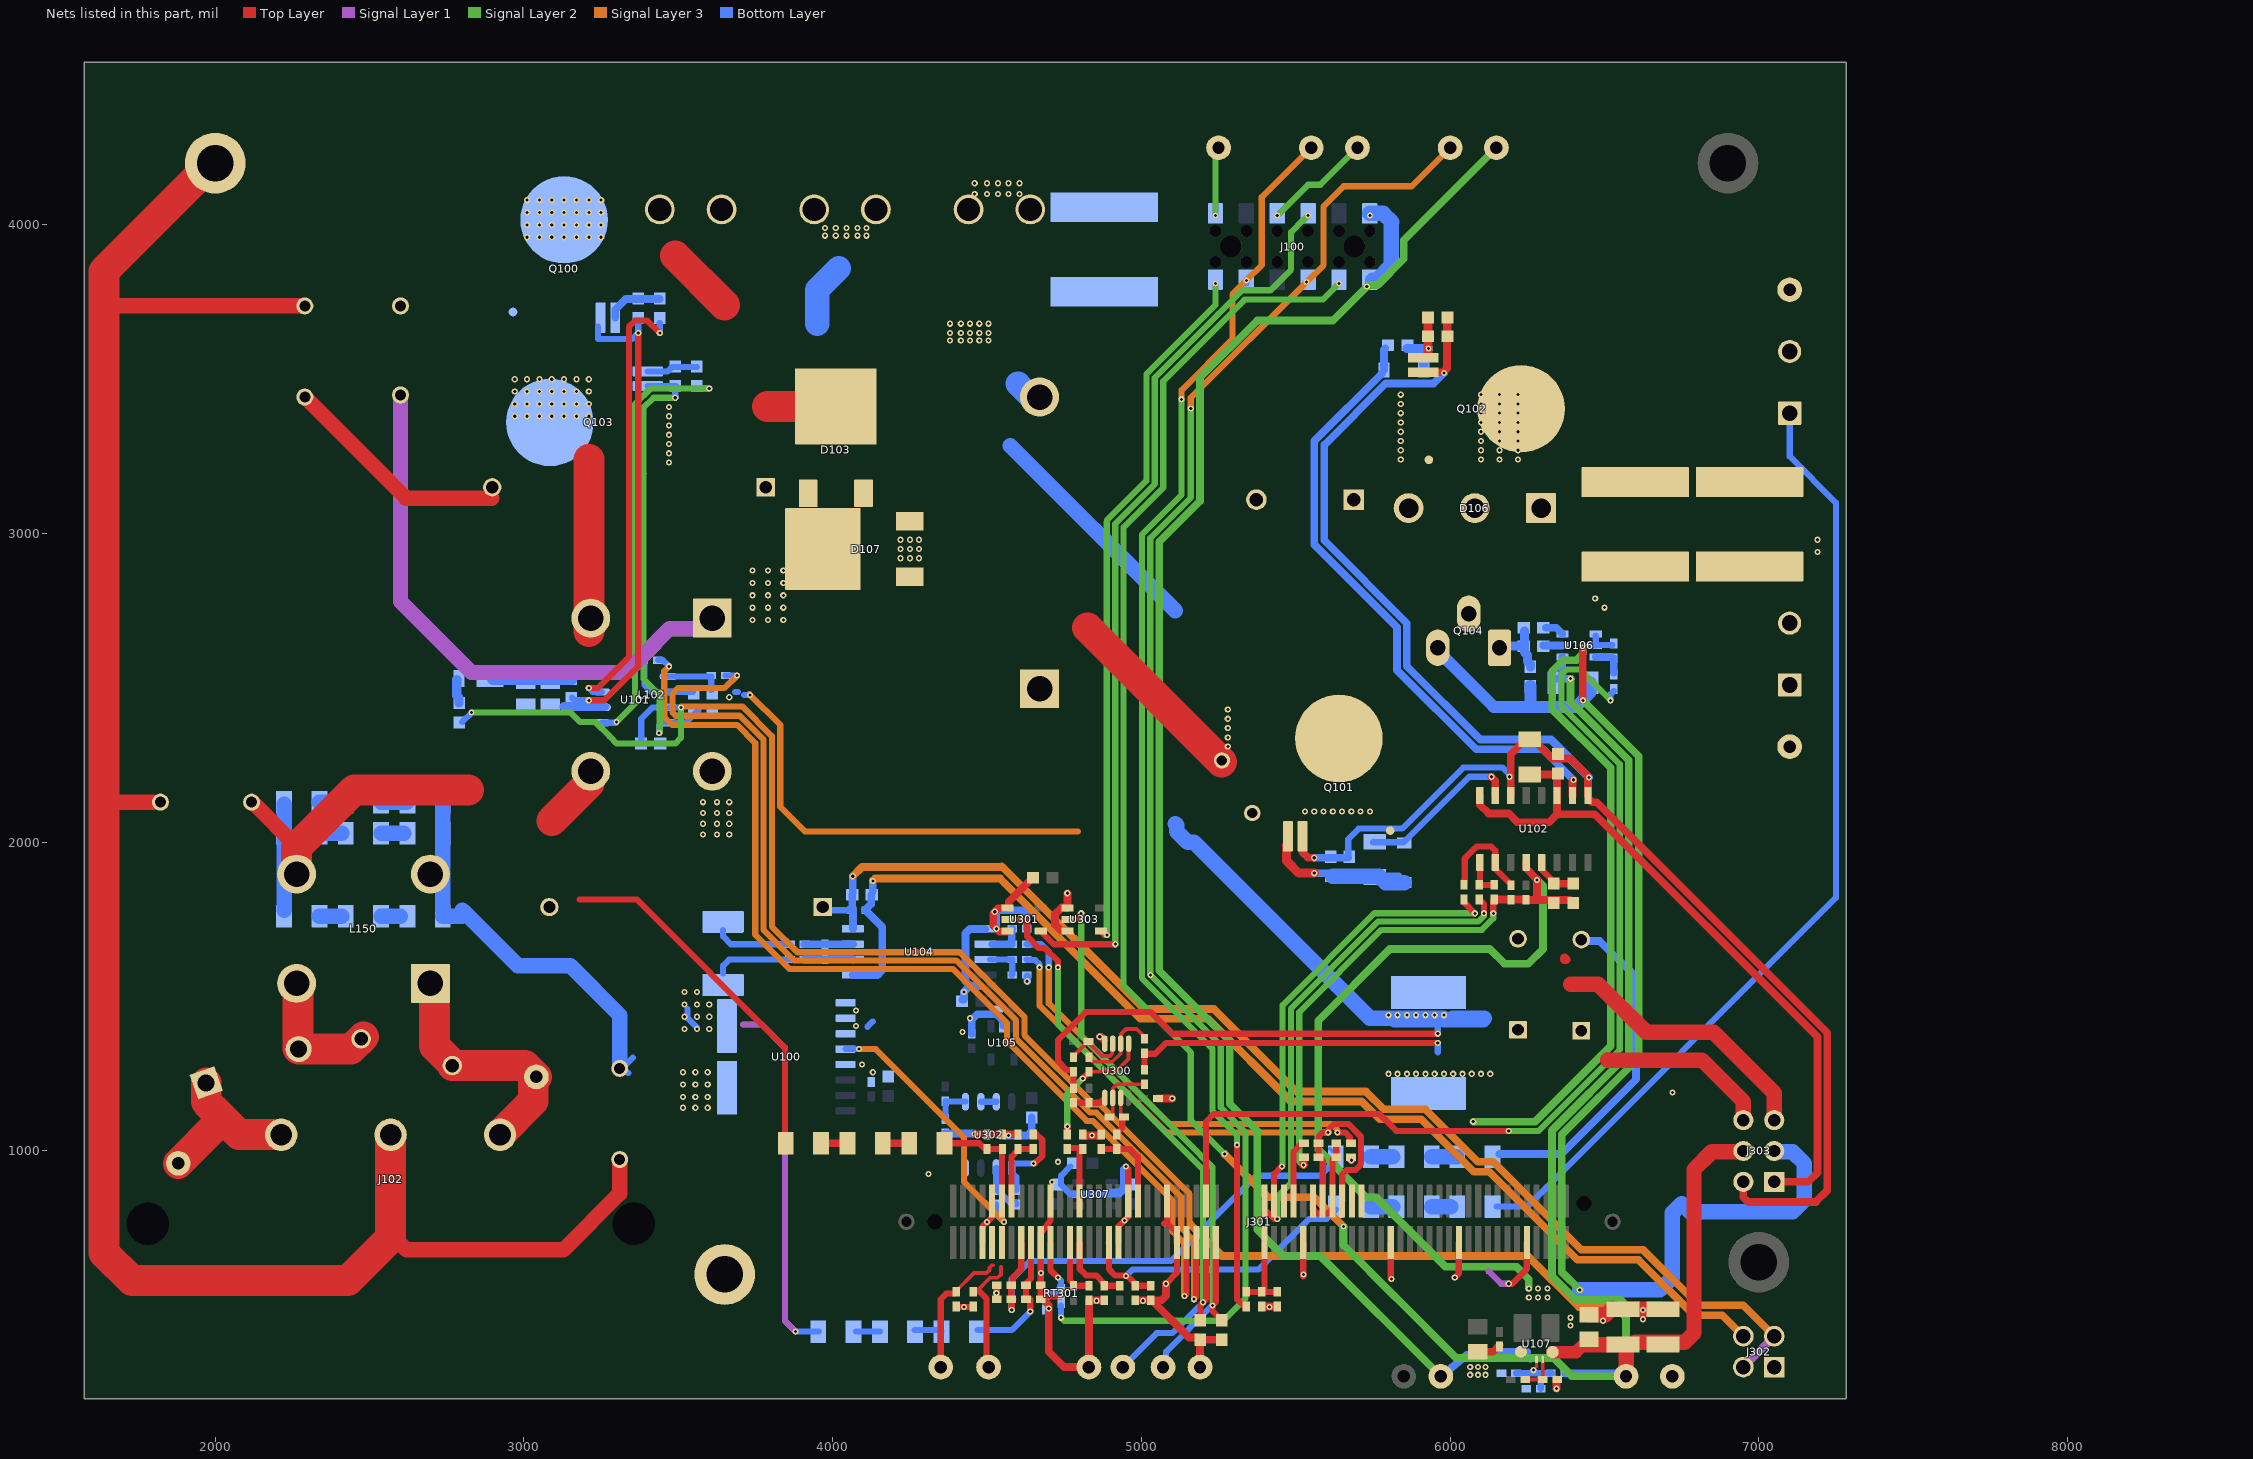
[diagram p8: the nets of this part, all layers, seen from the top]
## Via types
v1: diameter 20, hole 10, Top Layer to Bottom Layer, 378 vias
v2: diameter 19.68, hole 7.87, Top Layer to Bottom Layer, 12 vias

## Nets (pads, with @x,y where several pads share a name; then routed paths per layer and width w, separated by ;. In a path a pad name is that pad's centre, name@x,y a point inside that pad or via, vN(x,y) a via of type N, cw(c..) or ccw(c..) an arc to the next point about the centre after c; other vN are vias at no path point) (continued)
5Vs: C129.1 C142.1 J302.4 U104.1 | length 3849.2
  Signal Layer 3 w25: v1(4130,1875) 4137.37,1882.37 4542.37,1882.37 4996.75,1428 5217,1428 5484.5,1160.5 5714.25,1160.5 5771.75,1103 5906.75,1103 6076.75,933 6126.75,933 6411.75,648 6610,648 6790,468 6882,468 J302.4@6950,400
  Bottom Layer w20: C142.1@4104.69,1780 C142.1@4106.34,1780
  Bottom Layer w25: U104.1@4065.43,1570 4145,1570 4160.87,1585.87 4160.87,1724.13 ; C142.1@4104.69,1780 4125,1800.32 C129.1@4125,1830 ; C142.1@4106.34,1780 4160.67,1725.67 ; C129.1@4130,1840 v1(4130,1875)
12V1: C122.2 C131.1 J303.1 U102.11 U102.16 | length 2273.1
  Top Layer w25: U102.16@6096.42,2151.42 6096.42,2121.69 6124.59,2093.52 6189.59,2093.52 6218.31,2064.8 6320.63,2064.8 6346.42,2090.59 U102.11@6346.42,2151.42 C122.2@6346.42,2218.58 ; C131.1@6252.72,2219.33 C131.1@6257.72,2219.33 C122.2@6344.33,2219.33 ; 6348.72,2091.28 6468.72,2091.28 7190,1370 7190,930 7160,900 J303.1@7050,900 J303.1@7045,905
12Vp: 12Vp.1 C119.1 C126.2 C127.1 C137.1 C148.1 J100.9 J303.4 R121.2 R132.2 U101.3 U106.1 U107.1 | length 14834.6
  Top Layer w40: U107.1@6331.67,348.33 6408.33,348.33 C127.1@6450,390
  Top Layer w50: C127.1@6439.41,373.5 6440,372.91 C126.2@6560,372.91 C126.2@6570,372.91 ; 12Vp.1@6570,270 C126.2@6570,365 ; C126.2@6600,380 C148.1@6700,380 ; C148.1@6710,380 6760,380 6790,410 6790,940 6847.48,997.48 6943.09,997.48 6950,1004.39 J303.4@6950,1005
  Signal Layer 2 w20: v1(2830,2420) 3151.01,2420 3181.01,2390 3230,2390 3277.01,2342.99 3277.24,2342.99 3300.24,2320 3490,2320 3508.46,2338.46 v1(3508.46,2437.09) ; v1(5270,990) 5160,1100 5160,1318.28 5159.14,1319.14 4942.5,1535.78 4942.5,3020.96 5070.5,3148.96 5070.5,3493.82 5330.84,3754.16 ; 5330.68,3754.32 5334.55,3758.18 5588.18,3758.18 v1(5640,3810)
  Signal Layer 2 w25: v1(5655,755) 5655,695 5820,530 ; 5825,525 6020.48,329.52 6335.48,329.52 6395,270 12Vp.1@6570,270 6570,500 6552,518 6406.75,518 6330,594.75 6330,1066.56 6579,1315.56 6579,2265.75 6390,2454.75 v1(6390,2530)
  Signal Layer 3 w20: v1@3508.46,2440 3706.77,2440 3803,2343.77 3803,1727 3886,1644 4411,1644 4415,1640 ; 4415.18,1640.18 4621.09,1434.28 4621.09,1375.28 4844.87,1151.5 4864.87,1151.5 5139.37,877 5140.18,877 5156,861.18 5156,765
  Signal Layer 3 w25: 5158.5,763.22 5260,661.72 5260,660 6251.72,660 6416.72,495 6535,495 6570,460 12Vp.1@6570,270 ; v1(5270,990) 5410,850 5560,850 v1(5655,755)
  Bottom Layer w20: R132.2@2800,2390 v1(2830,2420) ; C119.1@3380,2330 3380,2400 3417.09,2437.09 U101.3@3467.52,2437.09 v1(3508.46,2437.09)
  Bottom Layer w25: v1(5270,990) v1@5271.5,988.5 ; C137.1@6340,2530 C137.1@6351.5,2530 ; U106.1@6363.58,2600.16 6363.58,2542.09 C137.1@6351.5,2530 ; R121.2@6373.62,280 6374.31,279.31 6559.31,279.31 12Vp.1@6560,280 ; v1(6390,2530) C137.1@6351.5,2530
+BRDG_N: R108.1 U101.7 | length 1449.3
  Top Layer w20: v1(3210,2500) 3240,2500 3340,2600 3340,3670 3360,3690 3400,3690 v1(3440,3650)
  Bottom Layer w11.81: U101.7@3250,2487.07 U101.7@3252.95,2487.09
  Bottom Layer w20: v1(3210,2500) 3222.91,2487.09 U101.7@3252.95,2487.09 ; v1(3440,3650) R108.1@3440,3681.81
+BRDG_P: R116.1 U101.5 | length 1403.8
  Signal Layer 2 w20: v1(3300,2390) 3360,2450 3360,3420 3410,3470 v1(3600,3470)
  Bottom Layer w20: U101.5@3252.95,2387.09 3297.09,2387.09 v1(3300,2390) ; R116.1@3560,3470 v1(3600,3470)
AC_CUR_SENSE: R312.2 U100.6 | length 896.7
  Signal Layer 3 w20: v1(4085,1330) 4140,1330 4425,1045 4425,900 v1(4555,770)
  Bottom Layer w20: U100.6@4041.93,1330 v1(4085,1330) ; R312.2@4530,826.38 4530,795 v1(4555,770)
ACL_SENSE: C314.1 J301.12 R101.1 R329.2 | length 366.8
  Top Layer w20: R101.1@4362.09,1025 R101.1@4365,1024.98 ; R101.1@4365,1030 R101.1@4365,1024.98 ; R101.1@4377.68,1006.38 4365,1019.06 R101.1@4365,1024.98 ; R329.2@4495,1005 4475.02,1024.98 R101.1@4365,1024.98 ; R329.2@4500,1006.38 C314.1@4540,1006.38 ; J301.12@4547.91,837.8 C314.1@4547.91,994.53
ACN_SENSE: C313.1 J301.17 R105.1 R328.2 | length 423.6
  Top Layer w20: C313.1@4625,570 4642.4,587.4 J301.17@4642.4,703.94 ; C313.1@4626.38,565 4626.38,521.81 4628.19,520 R328.2@4630,520 ; v1(4640,480) R328.2@4640,520
  Bottom Layer w20: R105.1@4470,420 4580,420 v1(4640,480)
AINN: C105.1 C129.2 C142.2 J302.2 J302.3 L102.4 R109.2 R119.1 U104.4 | length 4542
  Top Layer w25: J302.3@7050,400 J302.3@7050,405
  Signal Layer 1 w25: J302.2@6950,300 J302.3@7050,400
  Signal Layer 2 w25: J302.2@6950,300 7045,395 J302.3@7045,400
  Signal Layer 3 w25: v1(4065,1890) 4095,1920 4550,1920 ; 4547.5,1922.5 5010,1460 5235,1460 5502.5,1192.5 5727.5,1192.5 5785,1135 5920,1135 6090,965 6140,965 6425,680 6625,680 6805,500 6950,500 J302.3@7050,400 J302.2@6950,300
  Bottom Layer w20: R109.2@3645,1715 3645,1695 3670,1670 R119.1@3861.38,1670 ; C105.1@3995,1780 C142.2@4065.31,1780 ; J302.3@7045,400 J302.3@7050,400
  Bottom Layer w25: C142.2@4063.5,1786.5 C129.2@4063.5,1830 ; C129.2@4065,1836.2 v1(4065,1890) ; U104.4@4065.43,1720 C142.2@4065.43,1779.84 ; J302.3@7045,395 J302.3@7045,400
  other v1: 3580,2025 3625,2025 3665,2025 3580,2060 3625,2060 3665,2060 3580,2095 3625,2095 3665,2095 3580,2130 3625,2130 3665,2130
AINP: R107.2 R109.1 R114.1 U100.2 | length 1494.5
  Signal Layer 1 w20: 3710,1410 3770,1410 3845,1335 3845,450 v1(3880,415)
  Bottom Layer w20: 3530,1460 3530,1430 v1@3557.76,1402.24 ; 3645,1575 3645,1600 3665,1620 R114.1@3861.38,1620 ; v1(3880,415) R107.2@3952.91,415 R107.2@3955,415
  other v1: 3520,1395 3560,1395 3600,1395 3520,1435 3560,1435 3600,1435 3520,1475 3560,1475 3600,1475 3520,1515 3560,1515
BB_BYPAS: D101.1 R104.2 U102.10 | length 2007.3
  Top Layer w25: U102.10@6396.42,2151.42 6396.42,2199.65 v1(6399.37,2202.6)
  Bottom Layer w25: D101.1@5780,3520 5560,3300 5560,2964.75 5828,2696.75 5828,2557.43 6084.41,2301.02 6300.94,2301.02 v1(6399.37,2202.6) ; D101.1@5785.53,3530 5785.53,3595.53 R104.2@5790,3600
BB_ONOFF: J301.60 R139.1 | length 1451.2
  Top Layer w20: J301.60@5429.8,837.8 5429.96,837.95 5429.96,924.96 v1(5455,950) ; R139.1@6045.04,1814.8 6045.04,1804.96 v1(6080,1770)
  Signal Layer 2 w20: v1(5455,950) 5457.13,952.13 5457.13,1472.13 5755,1770 v1(6080,1770)
BBDRV: Q104.1 R125.2 R145.1 R147.2 | length 187.3
  Bottom Layer w29.53: Q104.1@6175.59,2635.59 R145.1@6238.58,2635.59 ; R147.2@6240.55,2684.8 6240.55,2615.91 6250.39,2606.06 6250.39,2586.38 6260.24,2576.54 R125.2@6260.24,2568.66
BBFET: J301.54 R144.1 | length 3274.1
  Top Layer w20: J301.54@5209.33,837.8 5209.33,1094.33 5235,1120 5770,1120 5825,1065 v1(6190,1065)
  Signal Layer 2 w20: v1(6190,1065) 6286.72,1065 6549.5,1327.78 6549.5,2253.53 6360.5,2442.53 6360.5,2542.22 6378.28,2560 6420,2560 v1(6520,2460)
  Bottom Layer w20: v1(6520,2460) 6520,2480 R144.1@6530,2490
Bulk_OK: J301.62
CLKIN: C307.1 J301.70 J301.74 R117.2 R317.1 | length 1917.4
  Top Layer w20: R317.1@5573.62,1021.38 C307.1@5573.62,980 5577.56,980 5587.28,970.28 J301.70@5587.28,837.8 J301.70@5587.44,837.64 ; R317.1@5575,1030 5575,1048.28 5586.72,1060 v1(5605,1060) 5605,1068.18 5623.82,1087 5671.18,1087 5711.37,1046.81 5711.37,961.15 5710,959.78 5710,955 5693.42,938.42 5664.89,938.42 5650.43,923.96 5650.43,837.95 J301.74@5650.28,837.8
  Signal Layer 3 w20: v1@4670,1590 4670,1470 5080,1060 v1(5605,1060)
  Bottom Layer w20: R117.2@4628.62,1620 4630.43,1618.19 4656.81,1618.19 4670,1605 v1(4670,1595)
DOUT: R118.2 R318.2 | length 1427.8
  Top Layer w20: v1(5635,1060) 5660,1060 5675,1045 R318.2@5675,1025
  Signal Layer 3 w20: v1(4700,1595) 4700,1478.18 5091.18,1087 5616.18,1087 5635,1068.18 v1(5635,1060)
  Bottom Layer w20: R118.2@4628.62,1670 4675,1670 4700,1645 v1(4700,1595)
DRV_Relay: D105.1 R110.1 U102.15 | length 537.9
  Top Layer w25: v1(6133.62,2212.44) 6146.42,2199.65 U102.15@6146.42,2151.42
  Bottom Layer w20: R110.1@5750,2000 5850,2000 6062.44,2212.44 v1(6133.62,2212.44)
GaN_Fault: GaN_FLT.1 J100.3 R334.1 | length 4133
  Top Layer w20: v1(5310,1020) 5310,520 R334.1@5335,495
  Signal Layer 2 w20: v1(5130,3435) 5129.5,3124.53 5001.5,2996.53 5001.5,1560.22 5230,1331.72 5230,1130 5310,1050 v1(5310,1020)
  Signal Layer 3 w20: v1(5130,3435) 5130,3465 5295,3630 5295,3775 v1(5340,3820) 5390,3870 5390,4090 GaN_FLT.1@5550,4250
  Bottom Layer w20: J100.3@5340,3810 v1(5340,3820) J100.3@5340,3822.91
GaN_TMP: J100.7 LS_TMP.1 R301.1 | length 5057.1
  Signal Layer 2 w20: v1(4740,460) 4750,450 5265,450 5337,522 5337,1061.18 5257,1141.18 5257,1342.9 5028.5,1571.4 5028.5,2985.34 5160,3116.84 v1(5160,3405)
  Signal Layer 3 w20: v1(5160,3405) 5160,3440 v1(5535,3815) 5590,3870 5590,4060 5655,4125 5875,4125 5995,4245 LS_TMP.1@6000,4245
  Bottom Layer w20: v1(4740,460) R301.1@4740,500 ; v1(5030,1570) v1@5030,1571.18
HFFET_HS: J100.8 U301.4 | length 2931.6
  Top Layer w20: U301.4@4674.13,1712.6 4716.73,1670 v1@4915,1670
  Signal Layer 2 w20: v1(4915.5,1670) 4915.5,3032.15 5043.5,3160.15 5043.5,3505 5249.09,3710.59 5249.09,3710.91 5326.68,3788.5 5418.5,3788.5 5485,3855 5485,3976.05 5525.05,4016.09 5526.09,4016.09 v1(5540,4030)
HFFET_HS1: HFFET_HS1.1 J301.53 R310.2 U301.2 | length 2125.2
  Top Layer w20: U301.2@4565.87,1750 4630,1750 4630,1695 4667.5,1657.5 4687.5,1657.5 4730,1615 v1(4730,1595) ; R310.2@5195,450 5191.18,453.82 5191.18,501.18 v1(5200,510) 5209.33,519.33 J301.53@5209.33,703.94
  Signal Layer 2 w20: 4730,1410 v1@4730,1590 ; 4732.5,1407.5 5200,940 v1(5200,510)
  Bottom Layer w20: HFFET_HS1.1@4960,320 5050,410 5100,410 v1(5200,510)
HFFET_LS: J100.1 U303.4 | length 2291.9
  Top Layer w20: U303.4@4859.13,1712.6 4867.01,1712.6 4879.61,1700 v1(4888,1700) v1@4890,1700
  Signal Layer 2 w20: v1(4888,1700) 4888,3038 4888.5,3038.5 4888.5,3043.33 5016.5,3171.33 5016.5,3516.5 5240,3740 v1(5240,3810)
HFFET_LS1: HFFET_LS1.1 J301.55 R307.2 U303.2 | length 2041.4
  Top Layer w20: U303.2@4760.87,1750 4762.68,1751.81 4786.81,1751.81 v1(4805,1770) ; J301.55@5240.83,703.94 5240.83,510.83 v1(5230,500) 5230,482.48 5260,452.48 R307.2@5260,451.5 R307.2@5260,450
  Signal Layer 2 w20: v1(4805,1770) 4805,1373.18 5151.59,1026.59 5230,948.18 v1(5230,500)
  Bottom Layer w20: HFFET_LS1.1@5080,290 5080,350 v1(5230,500)
IAC_SNS1: C308.1 J301.14 R308.2 | length 226.5
  Top Layer w20: J301.14@4579.57,837.64 J301.14@4579.41,837.8 4579.41,981.85 4600,1002.44 4600,1005 4601.38,1006.38 R308.2@4650,1006.38
IAC_SNS2: R302.2 R306.2 U300.1 | length 424.4
  Top Layer w12: v1(4810,1235) v1@4812.56,1235 ; R302.2@4830,1252.44 R302.2@4830,1256.38 ; R302.2@4830,1260 4833.62,1256.38 4916.38,1256.38 4958.39,1298.39 4958.39,1338.39 U300.1@4960,1340 ; U300.1@4957.29,1346.5 U300.1@4958.39,1347.6
  Top Layer w20: R306.2@4760,1053.62 v1(4760,1080) ; v1(4810,1235) R302.2@4827.44,1252.44
  Signal Layer 2 w20: v1(4760,1080) 4760,1185 v1(4810,1235)
LFFET_HS: J301.49 R136.1 | length 3410
  Top Layer w20: v1(5140,530) 5146.34,536.34 J301.49@5146.34,703.94
  Signal Layer 3 w20: v1(3470,2570) 3454.46,2554.46 3454.46,2405.54 3480,2380 3690.4,2380 3749,2321.4 3749,1701 3860,1590 4389,1590 4389.5,1589.5 ; 4390,1589 4565,1414 4565,1355 4822.5,1097.5 4842.5,1097.5 5100,840 5100,740 5137.72,702.28 5137.72,532.28 v1(5140,530)
  Bottom Layer w20: R136.1@3433.62,2590 3450,2590 v1(3470,2570)
LFFET_LS: J301.51 R134.1 | length 3555
  Top Layer w20: v1(5170,520) 5177.83,527.83 J301.51@5177.83,703.94
  Signal Layer 3 w20: v1(3690,2540) 3650,2500 3500,2500 3481.46,2481.46 3481.46,2420 3491.46,2410 3698.59,2410 3776,2332.59 3776,1715.82 3874.82,1617 4399.82,1617 ; 4401.18,1616 4594.09,1423.09 4594.09,1364.09 4833.68,1124.5 4853.68,1124.5 5127,851.18 5127,850 ; 5129,750 5129,850 ; 5130,750 5170,710 v1(5170,520)
  Bottom Layer w20: R134.1@3653.62,2540 v1(3690,2540)
Line: C106.2 C109.2 C110.2 C113.2 C115.1 L102.2 Q100.2 Q100.3-4-5-6-7-8 Q103.9 R112.1 U101.6 | length 3032.7
  Top Layer w20: v1(3210,2460) 3260,2460 3370,2570 v1(3370,3650)
  Top Layer w50: C109.2@2290,3442.36 2617.36,3115 2895,3115
  Top Layer w100: L102.2@3210.63,2683.07 3210.63,3240.63
  Bottom Layer w20: C115.1@3155.51,2468.98 3164.49,2460 v1(3210,2460) 3232.91,2437.09 U101.6@3252.95,2437.09 ; Q100.2@3240,3670 3240,3630 3350,3630 v1(3370,3650) R112.1@3370,3680
  Bottom Layer w29.53: 3130,2440 U101.6@3260,2440
  other v1: 2970,3380 3010,3380 3050,3380 3090,3380 3130,3380 3170,3380 3210,3380 2970,3420 3010,3420 3050,3420 3090,3420 3130,3420 3170,3420 3210,3420 2970,3460 3010,3460 3050,3460 3090,3460 3130,3460 3170,3460 3210,3460 2970,3500 3010,3500 3050,3500 3090,3500 3130,3500 3170,3500 3210,3500
NetC100_1: C100.1 D101.2 Q102.1 R100.2 R104.1 | length 254
  Top Layer w29.53: Q102.1@5928.5,3581.5 C100.1@5928.5,3700
  Bottom Layer w29.53: R104.1@5860,3600 v1(5930,3600) ; D101.2@5914.47,3530 5914.47,3595.53
NetC101_2: C101.2 D105.2 Q101.1 R110.2 R111.1 | length 689.6
  Top Layer w29.53: Q101.1@5470,1990 5470,1940 5510,1900 v1(5560,1900)
  Bottom Layer w25: v1(5560,1900) 5610,1900 R111.1@5620,1890 ; R111.1@5618.03,1898.27 5625.91,1890.39 5832.6,1890.39 D105.2@5840.47,1882.52
  Bottom Layer w50: R111.1@5620,1890 5770,1890 5790.77,1869.23 D105.2@5851.3,1869.23
NetC102_1: C102.1 L150.4 R156.1 R157.1 R158.1 U100.1 | length 1321
  Bottom Layer w20: C102.1@3310,1280 C102.1@3320,1270 ; 3337.76,1252.24 C102.1@3320,1270 ; 3352.24,1302.24 C102.1@3320,1270
  Bottom Layer w50: R156.1@2737.09,1760 2800,1760 ; R156.1@2737.09,1780 R158.1@2737.09,2030 R157.1@2737.09,2130 ; 2800,1780 2980,1600 3150,1600 3310,1440 3310,1280 C102.1@3310,1267.64
  other v1: 3515,1140 3555,1140 3595,1140 3515,1175 3555,1175 3595,1175 3515,1215 3555,1215 3595,1215 3515,1255 3555,1255 3595,1255
NetC103_1: C103.1 C106.1 D103.1 D103.3 D107.4 L102.1 L103.1 | length 1869.2
  Signal Layer 1 w50: C103.1@2600,3449.25 2600,2780 2830,2550 3330,2550 3385,2605 3385,2605.21 3472.01,2692.22 3592.22,2692.22 L102.1@3630,2730
  other v1: 3740,2720 3790,2720 3840,2720 3740,2760 3790,2760 3840,2760 3740,2800 3790,2800 3840,2800 3740,2840 3790,2840 3840,2840 3740,2880 3790,2880 3840,2880
NetC105_2: C105.2 C108.2 L102.3 L150.3 R103.2 R150.2 R151.2 R152.2 | length 2604
  Top Layer w20: 3180,1815 3365,1815 3845,1335 R103.2@3845,1035
  Top Layer w50: C108.2@2117.64,2130 2120,2130 2265,1985
  Top Layer w100: L150.3@2263.46,1897.17 2263.46,1983.46 2265,1985 2450,2170 2820,2170 ; 3090,2070 L102.3@3210,2190
  Bottom Layer w50: R150.2@2222.91,1780 R152.2@2222.91,2030 R151.2@2222.91,2122.91
NetC110_1: C110.1 C113.1 C115.2 D109.1 U101.8 | length 580.3
  Bottom Layer w20: D109.1@2929.13,2530 2936.22,2537.09 U101.8@3252.95,2537.09
  Bottom Layer w39.37: D109.1@2900,2530 2929.13,2530 C115.2@3153.54,2530
NetC117_1: C117.1 R136.2 U101.2 | length 236.6
  Bottom Layer w20: R136.2@3390,2580 3390,2510 3412.91,2487.09 U101.2@3467.52,2487.09 C117.1@3547.09,2487.09
NetC118_1: C118.1 R134.2 U101.1 | length 188.1
  Bottom Layer w20: U101.1@3462.4,2537.09 U101.1@3467.52,2537.09 R134.2@3606.38,2537.09 ; C118.1@3606.38,2493.62 R134.2@3606.38,2537.09 ; R134.2@3607.09,2537.09 R134.2@3606.38,2537.09
NetC124_1: C124.1 R137.2 U102.1 | length 117.9
  Top Layer w20: R137.2@6096.42,1860.28 U102.1@6096.42,1934.88 ; R137.2@6100.16,1862.05 C124.1@6143.46,1862.05
NetC125_1: C125.1 R139.2 U102.2 | length 333.5
  Top Layer w20: R139.2@6045.04,1862.05 6045.04,1878.24 6047.5,1880.7 6047.5,1947.5 6067.61,1967.61 6067.61,1968.31 6078.74,1979.44 6079.44,1979.44 6086.06,1986.06 6133.62,1986.06 6146.42,1973.27 U102.2@6146.42,1934.88 6146.42,1914.21 C125.1@6192.68,1867.95 ; C125.1@6197.6,1861.06 C125.1@6197.6,1863.03
NetC132_1: C132.1 R143.2 U102.5 | length 137.1
  Top Layer w20: U102.5@6296.42,1934.88 6296.42,1911.85 R143.2@6330.47,1877.8
  Top Layer w25: R143.2@6332.44,1865.98 C132.1@6398.39,1865.98
NetC135_1: C135.1 R114.2 U104.2 | length 151.4
  Bottom Layer w25: R114.2@3908.62,1620 C135.1@3970,1620 ; C135.1@3975.69,1620.69 4064.74,1620.69 U104.2@4065.43,1620
NetC135_2: C135.2 R119.2 U104.3 | length 151.1
  Bottom Layer w25: R119.2@3908.62,1670 C135.2@3974.31,1670 ; C135.2@3980,1670 U104.3@4065.43,1670
NetC136_1: C136.1 R144.2 U106.6 | length 94.4
  Bottom Layer w25: U106.6@6471.85,2600.16 C136.1@6519.84,2600.16 ; R144.2@6530,2550 C136.1@6530,2596.38
NetC146_1: C146.1 R117.1 U104.7 | length 121.9
  Bottom Layer w20: U104.7@4510,1620 R117.1@4581.38,1620 4581.38,1571.38 C146.1@4580,1570
NetC147_1: C147.1 R118.1 U104.6 | length 108.5
  Bottom Layer w25: U104.6@4517.5,1670 R118.1@4580,1670 ; R118.1@4580,1675 4580,1719.31 4580.69,1720 C147.1@4581.38,1720
NetC150_1: C150.1 R121.1 R126.2 U107.6 | length 217.2
  Top Layer w10: v1(6270,290) 6270,290.48 6280,300.48 U107.6@6280,325.2
  Bottom Layer w20: R126.2@6213.62,280 6270,280 ; v1(6270,290) 6270,280 ; C150.1@6293.62,230 6293.62,276.38 6290,280 ; R121.1@6330,280 R121.1@6326.38,280 6290,280 ; 6270,280 6290,280
NetC300_2: C300.2 J301.27 R300.2 | length 238.5
  Top Layer w20: J301.27@4799.88,703.94 4800.04,703.78 4800.04,617.77 4820.81,597 4853,597 C300.2@4880,570 ; C300.2@4880,563.62 4928.19,563.62 4930,561.81 R300.2@4930,560
NetC301_1: C301.1 J301.28 R306.1 | length 205.9
  Top Layer w20: R306.1@4766.38,1010 C301.1@4810,1010 ; J301.28@4799.88,837.8 4799.88,992.56 4800,992.68 C301.1@4800,1000
NetC302_2: C302.2 J301.21 R301.2 | length 221.5
  Top Layer w20: J301.21@4705.39,703.94 4705.55,703.78 4705.55,614.45 v1(4730,590)
  Bottom Layer w20: C302.2@4690,533.62 4690,537.56 4691.81,539.37 4719.37,539.37 4740,560 4740,580 v1(4730,590)
NetC304_1: C304.1 DACA.1 J301.9 | length 444
  Top Layer w12: C304.1@4400,543.62 4400,547.56 4457.44,605 4497.83,605 4507.76,614.93 4507.76,621.51 4516.26,630 4520,630
  Top Layer w20: DACA.1@4350,300 4350,520 4367.87,537.87 4398.19,537.87 4400,539.68 C304.1@4400,543.62
NetC305_1: C305.1 DACB.1 J301.11 | length 415.7
  Top Layer w12: C305.1@4465,545 4465.43,545 4510.25,589.81 4534.81,589.81 4545,600 4545,625 ; J301.11@4544.07,700.09 J301.11@4547.91,703.94
  Top Layer w20: C305.1@4453.62,545 C305.1@4455,543.62 4456.38,545 C305.1@4465,545 ; C305.1@4465.43,545 4475,545 4498.63,521.37 4498.63,301.37 4500,300 DACB.1@4500,305
NetC306_1: C306.1 J301.40 R309.2 | length 274.8
  Top Layer w20: C306.1@4870,1002.44 C306.1@4870,1006.38 R309.2@4918.19,1006.38 ; R309.2@4920,1006.38 4963.62,1006.38 4988.86,981.14 J301.40@4988.86,837.8
NetC309_1: C309.1 J301.68 J301.72 R318.1 | length 306
  Top Layer w20: J301.68@5555,830 5555,812.57 5570.4,797.18 5604.17,797.18 5618.62,811.63 5618.62,837.64 J301.72@5618.78,837.8 5618.78,971.34 C309.1@5627.44,980 ; R318.1@5630,1020 5631.38,1018.62 C309.1@5631.38,980
NetC318_1: C318.1 J301.57 R334.2 R337.2 | length 261.6
  Top Layer w20: R334.2@5340,543.62 C318.1@5388.62,543.62 ; C318.1@5390,543.62 5438.62,543.62 R337.2@5440,545 ; C318.1@5390,545 5390,547.56 5398.31,555.87 J301.57@5398.31,703.94
NetD106_1: D106.1 D106.3 L100.1 Q104.2
NetD109_2: D109.2 R132.1 | length 79.6
  Bottom Layer w29.53: D109.2@2782.13,2527.87 2782.13,2475.61 2790,2467.74 R132.1@2790,2451.5
NetF150_1: F150.1 J102.1 Line.1 | length 562.7
  Top Layer w100: Line.1@1880,960 2010,1090 2010,1120 ; F150.1@1970.61,1221.03 1970.61,1159.39 2010,1120 ; J102.1@2213.58,1052.48 2212.63,1053.44 2076.56,1053.44 2010,1120
NetF150_2: F150.2 L150.2 RV150.1 | length 442.1
  Top Layer w100: L150.2@2263.46,1542.83 2268.44,1537.86 2268.44,1331.56 F150.2@2270,1330 2440,1330 RV150.1@2480,1370
NetHS_FLT_1: HS_FLT.1 J100.6 | length 351.1
  Signal Layer 2 w20: v1(5440,4030) 5540,4130 5580,4130 HS_FLT.1@5700,4250
NetHS_TMP_1: HS_TMP.1 J100.2 | length 224.1
  Signal Layer 2 w20: v1(5240,4030) 5240,4240 HS_TMP.1@5250,4250
NetJ102_2: J102.2 L150.1 Neutral.1 RV150.2 | length 836.5
  Top Layer w100: L150.1@2696.54,1542.83 2709.53,1529.84 2709.53,1340.47 RV150.2@2770,1280 ; L150.1@2700,1540 L150.1@2709.53,1530.47 ; RV150.2@2767.64,1276.69 3003.31,1276.69 Neutral.1@3040,1240 3030,1240 3030,1161.59 2922.24,1053.83 J102.2@2922.24,1052.48
NetJ301_64: J301.64 R317.2 | length 203.6
  Top Layer w20: J301.64@5492.8,837.8 5492.8,998.02 5517.97,1023.19 5523.19,1023.19 R317.2@5525,1025
NetQ100_1: Q100.1 R108.2 R112.2 | length 185
  Bottom Layer w25: Q100.1@3295.35,3699.37 3295.35,3725.35 3330,3760 R108.2@3440,3760
NetQ103_1: Q103.1 R116.2 R124.2 | length 165.4
  Bottom Layer w20: Q103.1@3400.63,3525.35 3465.35,3525.35 3480,3540 R116.2@3560,3540
NetR101_2: R101.2 R102.1 | length 77.9
  Top Layer w25: R102.1@4162.09,1025 R101.2@4240,1025
NetR102_2: R102.2 R103.1 | length 90
  Top Layer w25: R103.1@3962.09,1025 4045,1025 R102.2@4050,1020
NetR105_2: R105.2 R106.1 | length 90
  Bottom Layer w20: R106.1@4265,420 4347.91,420 R105.2@4352.91,415
NetR106_2: R106.2 R107.1 | length 77.9
  Bottom Layer w20: R107.1@4075,415 R106.2@4152.91,415
NetR122_1: R122.1 R123.2 U107.7 | length 125.3
  Top Layer w12: R122.1@6240,260 R122.1@6243.62,260 R123.2@6300,260 6299.84,260.16 6299.84,325.04 U107.7@6299.69,325.2
NetR145_2: R145.2 U106.2 | length 62
  Bottom Layer w25: R145.2@6301.57,2637.56 U106.2@6363.58,2637.56
NetR147_1: R147.1 U106.3 | length 62.3
  Bottom Layer w25: R147.1@6309.45,2694.65 6343.9,2694.65 U106.3@6363.58,2674.96
NetR150_1: R150.1 R153.2 | length 72.9
  Bottom Layer w50: R150.1@2337.09,1760 R153.2@2410,1760
NetR151_1: R151.1 R154.2 | length 72.9
  Bottom Layer w50: R151.1@2337.09,2130 R154.2@2410,2130
NetR152_1: R152.1 R155.2 | length 72.9
  Bottom Layer w50: R152.1@2337.09,2030 R155.2@2410,2030
NetR153_1: R153.1 R156.2 | length 62.9
  Bottom Layer w50: R153.1@2537.09,1760 R156.2@2600,1760
NetR154_1: R154.1 R157.2 | length 82.9
  Bottom Layer w50: R154.1@2537.09,2130 R157.2@2620,2130
NetR155_1: R155.1 R158.2 | length 72.9
  Bottom Layer w50: R155.1@2537.09,2030 R158.2@2610,2030
NetR302_1: R302.1 R305.2 U300.2 | length 268.2
  Top Layer w12: R302.1@4835,1295 4840.98,1289.02 4905.89,1289.02 4932.8,1315.93 U300.2@4932.8,1347.6 4933.89,1348.69 4933.89,1379.08 4950,1395.19 4984.81,1395.19 R305.2@5010,1370
NetR303_2: R303.2 R304.2 U300.3 | length 182.6
  Top Layer w12: R303.2@4785,1310 4785,1312.56 4818.87,1346.43 4818.87,1349.19 4824.69,1355 R304.2@4828.62,1355 R304.2@4829.76,1355 ; R304.2@4835,1345 4871.98,1308.02 4898.02,1308.02 4905,1315 U300.3@4905,1340 ; U300.3@4906.11,1348.69 U300.3@4907.2,1347.6
  Top Layer w20: R303.2@4780,1303.62 R303.2@4780,1305
NetR308_1: R308.1 R311.2 U302.1 | length 245.7
  Top Layer w20: v1(4650,960) 4655.22,960 4678.81,983.59 4678.81,1036.19 R308.1@4660,1055
  Bottom Layer w20: U302.1@4580,930 4580,929.25 4581.67,927.57 4582.3,927.57 4595,914.88 R311.2@4595,873.62 ; U302.1@4585,960 v1(4650,960)
NetR311_1: R311.1 R312.1 U302.2 | length 150.4
  Bottom Layer w20: R312.1@4530,875 U302.2@4530,945 ; R312.1@4535,870 4537.98,870 4575.85,832.13 4593.19,832.13 4595,830.32 R311.1@4595,826.38
NetR341_1: R341.1 R353.2 U300.6 | length 202.2
  Top Layer w12: R341.1@4900,1110 4900.32,1110 4907.2,1116.89 U300.6@4907.2,1172.4 4908.3,1173.5 4908.3,1203.3 4921.38,1216.38 5004.19,1216.38 5005,1217.19 R353.2@5005,1220
NetR347_2: R347.2 R348.1 U300.5 | length 108.2
  Top Layer w20: R347.2@4780,1156.38 4828.19,1156.38 4830,1158.19 R348.1@4830,1160 ; R348.1@4830,1156.38 4866.38,1156.38 U300.5@4880,1170
NetR350_1: R350.1 R351.2 | length 80.7
  Bottom Layer w50: R351.2@5940.39,981.26 R350.1@6021.1,981.26
NetR351_1: R351.1 R352.2 | length 70.9
  Bottom Layer w50: R352.2@5743.54,981.26 R351.1@5814.41,981.26
NetR354_1: R354.1 R356.2 | length 61
  Bottom Layer w50: R356.2@5940.39,819.29 R354.1@6001.42,819.29
NetR356_1: R356.1 R357.2 | length 70.9
  Bottom Layer w50: R357.2@5743.54,819.29 R356.1@5814.41,819.29
NetR359_1: R359.1 R360.2 U302.5 | length 121.9
  Bottom Layer w20: R360.2@4365,1105 R359.1@4365,1161.38 4365.91,1160.47 4429.53,1160.47 U302.5@4430,1160
NetU302_6: U302.6 U302.7 | length 50.2
  Bottom Layer w20: U302.6@4480,1159.57 4529.57,1159.57 U302.7@4530,1160
PE: C102.2 C103.2 C108.1 C109.1 J102.3 pad.1@2000,4200 pad.1@3650,600 | length 6782.9
  Top Layer w50: 1650,2130 C108.1@1822.36,2130 ; 1657.64,3737.64 C109.1@2290,3737.64 ; 2570,730 2620,680 3127.78,680 3310,862.22 C102.2@3310,972.36
  Top Layer w100: pad.1@1990,4200 1640,3850 1640,670 1730,580 2430,580 2567.91,717.91 J102.3@2567.91,1052.48
PGND: C104.1 C107.1 C111.2 C112.2 C114.1 C120.1 C124.2 C125.2 C126.1 C127.2 C128.2 C132.2 C133.2 C136.2 C137.2 C138.2 C139.2 C144.2 C145.2 C146.2 C147.2 C148.2 C149.2 C150.2 C300.1 C301.2 C302.1 C303.1 C304.2 C305.2 C306.2 C307.2 C308.2 C309.2 C313.2 C314.2 C315.2 C318.2 C322.2 C324.2 C328.2 C329.2 C336.1 C337.1 C338.1 J100.11 J100.12 J301.7 J301.10 J301.19 J301.22 J301.35 J301.38 J301.46 J301.47 J301.65 J301.83 J301.97 J301.111 J303.3 J303.6 PGND.1 PGND.2 Q104.3 R113.1 R123.1 R125.1 R126.1 R143.1 R305.1 R307.1 R310.1 R328.1 R329.1 R337.1 R353.1 R355.1 R358.1 R360.1 RT301.1 U100.3 U100.4 U100.5 U100.7 U102.4 U104.5 U105.2 U106.4 U106.5 U107.4 U300.4 U301.1 U301.3 U302.4 U303.1 U303.3 U307.2 | length 23033.1
  Top Layer w12: R328.1@4680,520 4680,522.44 R328.1@4684.76,527.2
  Top Layer w15: R328.1@4684.76,527.2 RT301.1@4740,527.2
  Top Layer w20: C304.2@4400,496.38 4401.38,495 C305.2@4450,495 ; J301.7@4484.92,703.94 4484.92,754.92 v1(4500,770) 4516.42,786.42 J301.10@4516.42,837.8 ; R355.1@4530,520 4531.38,521.38 C328.2@4531.38,565 ; R328.1@4670,520 4671.81,520 4673.62,521.81 C313.2@4673.62,570 ; C313.2@4670,570 4672.09,570 4673.9,571.81 J301.19@4673.9,703.94 J301.19@4673.9,733.9 ; J301.19@4675,735 4705,775 ; 4705.39,774.61 J301.22@4705.39,837.8 ; C300.1@4873.62,516.38 C300.1@4875,515 ; J301.35@4925,755 J301.35@4925.87,755.87 ; J301.35@4925.87,703.94 J301.35@4925.87,755.87 ; v1(4950,950) 4957.36,942.64 J301.38@4957.36,837.8 4957.52,837.64 4957.52,787.52 J301.35@4925.87,755.87 ; R353.1@5010,1263.62 5010,1315 5045,1315 5080,1350 v1(5960,1350) ; 5073,765 5082.01,765 5083.5,766.5 ; v1(5080,570) 5114.84,604.84 J301.47@5114.84,703.94 5114.69,704.09 5114.69,735.32 5083.5,766.5 ; J301.46@5083.35,837.8 5083.5,837.64 5083.5,766.5 ; v1@5524.29,594.29 J301.65@5524.29,703.94 ; J301.83@5807.76,703.94 5807.76,587.24 v1(5810,585) ; PGND.1@5958.52,298.41 5958.52,276.48 PGND.1@5965,270 ; v1(6015,590) 6028.07,603.07 6028.07,703.78 J301.97@6028.23,703.94 ; v1(6140,1770) C124.2@6140,1810 ; v1(6190,570) 6200.77,570 6248.54,617.77 6248.54,703.78 J301.111@6248.7,703.94
  Top Layer w25: v1(4460,1055) 4500.01,1054.61 4550,1054.11 4570.04,1053.92 C308.2@4600,1053.62 ; 4535,1785 4520,1770 4520,1730 4540,1710 U301.3@4570,1710 ; 4535,1786.71 U301.1@4565.18,1786.71 ; U301.1@4570,1790 4570,1807.48 C303.1@4641.26,1878.74 ; R328.1@4680,520 4700,500 v1(4700,490) 4700,350 4750,300 4820,300 PGND.1@4825,305 ; U303.1@4742.97,1790 4720,1767.03 4720,1732.97 4739.68,1713.29 4760.18,1713.29 U303.3@4760.87,1712.6 ; U303.1@4754.37,1787.4 U303.1@4760.87,1787.4 4760.87,1834.13 v1(4760,1835) ; C301.2@4810,1053.62 4810,1051.06 4810.69,1050.37 4813.25,1050.37 4813.62,1050 v1(4840,1050) C306.2@4870,1050 ; PGND.1@4830,300 C322.2@4830,510 ; C322.2@4830,516.38 C300.1@4873.62,516.38 ; v1(4865,1370) 4868.85,1370 U300.4@4878.85,1360 ; C329.2@4980,516.38 R358.1@5026.38,516.38 ; R358.1@5035,515 5154.31,395.69 5183.8,395.69 5190,389.49 R310.1@5190,388.5 5190,305 PGND.1@5185,300 ; R358.1@5035,516.38 5065.36,516.38 5080,531.02 v1(5080,570) ; C324.2@5053.62,1170 v1(5100,1170) ; R310.1@5191.5,388.5 R307.1@5260,388.5 ; C318.2@5390,496.38 5431.38,496.38 R337.1@5435,500 ; v1(5525,955) C307.2@5525,980 ; v1(5680,970) C309.2@5680,975 ; C128.2@6115,350 6139.69,350 C149.2@6160,370.31 ; C124.2@6143.46,1814.8 C133.2@6237.95,1814.8 ; C133.2@6237.95,1812.83 6281.26,1812.83 ; U102.4@6246.42,1934.88 6246.42,1915.61 6281.26,1880.77 v1(6281.26,1877.8) 6281.26,1812.83 ; v1(6345,230) R123.1@6345,260 ; C132.2@6388.54,1812.83 6281.26,1812.83 ; v1(6430,2460) v1(6430,2630) ; C126.1@6557.09,487.09 C126.1@6560,490
  Top Layer w50: C127.2@6450,470 6505,470 C126.1@6525,490 ; 6510,1295 6510.35,1294.65 6815.35,1294.65 6950,1160 J303.6@6950,1110 ; C126.1@6572.91,487.09 C148.2@6690,487.09
  Signal Layer 1 w20: 6125,610 6165,570 v1(6190,570)
  Signal Layer 2 w20: 5511.13,970 5511.13,1449.76 5777.37,1716 6102.37,1716 6140,1753.63 v1(6140,1770)
  Signal Layer 2 w25: 5513.63,966.37 v1(5525,955) ; PGND.1@5970,270 5580,660 5460,660 5375,745 5375,1065 5286.5,1153.5 5286.5,1355.12 5058,1583.62 5058,2973.12 5189.5,3104.62 5189.5,3504.5 5375,3690 5620,3690 v1(5730,3800) 5735,3805 5764.84,3805 5850,3890.16 5850,3950 PGND.1@6150,4250 ; PGND.1@5970,275 PGND.1@5970,284.88 ; v1(6075,1095) 6275,1095 6520,1340 6520,2241.31 6331,2430.31 6331,2554.44 6366.06,2589.5 6409.5,2589.5 6430,2610 v1(6430,2630) ; v1(6255,555) 6255,585 6215,625 5985,625 5760,850 5727.5,850 5572.63,1004.87 5572.63,1422.37 5804.75,1654.5 6128.53,1654.5 6176.43,1606.59 6253.57,1606.59 6301.04,1654.07 6301.04,1858.96 ; v1(6281.26,1877.8) 6282.2,1877.8 6300,1860 ; v1(6420,550) 6362,608 6362,1053.31 6611,1302.31 6611,2279 v1(6430,2460)
  Bottom Layer w20: 4112.24,1402.24 4130,1420 ; 4490,760 v1(4500,770) ; U105.2@4550,1404.13 U105.2@4550,1420 ; C336.1@4770,950 4740,920 4740,890 4770,860 4885,860 ; v1(4950,950) 4940.82,940.82 4940.82,879.73 4929,867.9 4892.9,867.9 4885,860 ; C337.1@4960,890 4930,860 4885,860 ; 5960,1320 v1(5960,1350) ; 6439.37,2637.56 U106.5@6471.85,2637.56 ; U106.5@6471.85,2639.53 U106.4@6471.85,2670.04 ; U106.5@6482.68,2639.53 C136.2@6525.98,2639.53
  Bottom Layer w25: R360.1@4365,1056.38 4458.62,1056.38 v1(4460,1055) ; C145.2@4420,1490 4423.8,1490 4425,1491.2 v1(4425,1515) 4445,1535 ; C138.2@4450,1380 4450,1425 4468.32,1443.32 4531.31,1443.32 4550,1424.63 U105.2@4550,1420 ; C144.2@4470,1535 4445,1535 ; U104.5@4493.88,1719.31 4444.64,1719.31 4430,1704.67 4430,1550 4445,1535 ; v1(4530,1720) 4530,1780 4613.98,1780 4628.62,1765.36 C147.2@4628.62,1720 ; v1@4565,1050 v1(4570,1050) 4630.36,1050 4645,1064.64 C315.2@4645,1108.5 ; v1(4630,1550) C146.2@4630,1565 ; PGND.1@5970,270 6055,340 ; 6070,350 6250,350
  Bottom Layer w39.37: Q104.3@5950,2630 6141.26,2438.74 6260.24,2438.74 ; R125.1@6260.24,2505.67 6260.24,2438.74 ; C137.2@6455.12,2517.48 6455.12,2485.98 6407.87,2438.74 6260.24,2438.74
  Bottom Layer w50: J100.12@5740,4037.09 5782.91,4037.09 5811.09,4008.91 ; J100.11@5750,3820 5762.22,3820 5791.09,3848.87 5791.09,3851.09 5810,3870 5810,4008.91 ; v1(6420,550) 6680,550 6720,590 6720,800 6750,830 ; 6775,805 6777.48,802.52 7109.4,802.52 7147.48,840.6 7147.48,959.4 7109.4,997.48 7052.52,997.48 J303.3@7050,1000
  other v1: 6065,275 6090,275 6115,275 6065,300 6090,300 6115,300 6390,435 6495,450 6625,455 6390,460 6625,485 4425,495 5415,495 4855,515 5005,515 6255,525 6285,525 6315,525 4530,540 6285,555 6315,555 5525,600 4675,605 4945,775 4710,900 4310,925 4730,965 6720,1190 5800,1250 5830,1250 5860,1250 5890,1250 5920,1250 5950,1250 5980,1250 6010,1250 6040,1250 6070,1250 6100,1250 6130,1250 4130,1255 4095,1280 4420,1385 4075,1405 4445,1430 4075,1455 4525,1775 6500,2760 6470,2790 7190,2940 7190,2980 5740,4030
RELAY_CTRL: J301.58 R137.1 | length 1590.1
  Top Layer w20: J301.58@5398.31,837.8 5398.46,837.64 5398.46,811.63 5430.09,780 v1(5440,780) ; R137.1@6094.25,1814.8 6110,1799.06 v1(6110,1770)
  Signal Layer 2 w20: v1(5440,780) 5440,851.18 5484.13,895.31 5484.13,1460.94 5766.18,1743 6091.18,1743 6110,1761.82 v1(6110,1770)
SCI_RX0: J301.76
SCI_TX0: J301.78
SWNODE: L103.2 TP103.1 TP104.1 | length 261.2
  Bottom Layer w80: 3950,3680 3950,3790 4020,3860 ; 4600,3485.43 L103.2@4636.93,3448.5
  other v1: 3975,3965 4010,3965 4045,3965 4080,3965 4110,3965 3975,3990 4010,3990 4045,3990 4080,3990 4110,3990
TMP_PRI: C322.1 J301.25 R340.2 RT301.2 | length 234.6
  Top Layer w12: RT301.2@4740,552.8 4773.11,552.8 4780,559.68 R340.2@4780,560
  Top Layer w20: J301.25@4768.39,703.94 4768.39,581.61 R340.2@4780,570 ; R340.2@4780,563.62 4823.62,563.62 C322.1@4830,570
VBB: C104.2 C107.2 D106.2 Q102.9 R354.2 Vout.1 Vout.2 | length 3193.2
  Top Layer w50: Q102.9@6236.69,3424.02 Q102.9@6236.69,3470.83
  Bottom Layer w20: R354.2@6150,820 6250,820 7250,1820 7250,3100 7100,3250 Vout.1@7100,3390
  other v1: 6100,3240 6160,3240 6220,3240 6100,3270 6160,3270 6220,3270 6100,3300 6160,3300 6220,3300 6100,3330 6160,3330 6220,3330 6100,3360 6160,3360 6220,3360 6100,3390 6160,3390 6220,3390 6100,3420 6160,3420 6220,3420 6100,3450 6160,3450 6220,3450
VBB_FB: C329.1 J301.33 R357.1 R358.2 | length 1009.5
  Top Layer w20: J301.33@4894.37,703.94 4894.53,703.78 4894.53,617.77 4915.93,596.37 v1@4950,596.37 ; v1@4953.63,596.37 C329.1@4980,570 ; C329.1@4980,563.62 5028.19,563.62 5030,561.81 R358.2@5030,560
  Bottom Layer w20: v1(4950,595) 4971.42,616.42 5379.6,616.42 5543.18,780 5570,780 5600,780 R357.1@5630,810
Vbulk: C100.2 C101.1 C114.2 C120.2 C122.1 C131.2 J303.2 J303.5 L100.2 Q101.2 Q101.3-4-5-6-7-8 Q102.2 Q102.3-4-5-6-7-8 R100.1 R111.2 R350.2 RT100.1 U102.9 U102.14 | length 7696.7
  Top Layer w25: Q101.2@5521.89,2019.37 5521.89,1968.11 5540,1950 v1(5560,1950) ; Q102.2@5912.87,3522.44 5977.56,3522.44 5990,3534.88 C100.2@5990,3690 ; R100.1@5991.5,3640 C100.2@5991.5,3688.5 ; U102.14@6196.42,2151.42 6196.42,2285.08 6232.05,2320.71 6281.26,2320.71 6330.47,2271.5 6389.53,2271.5 6446.42,2214.61 U102.9@6446.42,2151.42 ; U102.9@6450,2140 6460,2130 6475.25,2130 7222,1383.25 7222,872 7185,835 6965,835 6950,850 J303.2@6950,900 J303.2@6950,910
  Top Layer w29.53: 6370,1620 6375.35,1620 6370,1625.35
  Top Layer w50: 6390,1540 6480,1540 6635.35,1384.65 6853.21,1384.65 7050,1187.86 J303.5@7050,1100
  Bottom Layer w20: C101.1@5670,1960 5670,2010 5704.2,2044.2 5844.2,2044.2 6041.97,2241.97 6170.04,2241.97 v1@6194.65,2217.36
  Bottom Layer w25: RT100.1@5359.21,2094.76 RT100.1@5359.21,2101 ; v1(5560,1950) C101.1@5670,1950 ; v1(5980,3520) 5946.48,3486.48 5791.74,3486.48 5592,3286.75 5592,2978 5860,2710 5860,2570.69 6097.66,2333.02 6326.98,2333.02 v1(6450,2210) ; R350.2@6160,990 6360,990 6602.5,1232.5 6602.5,1562.5 6485,1680 6435,1680 C114.2@6425,1690
  other v1: 5530,2100 5560,2100 5590,2100 5620,2100 5650,2100 5680,2100 5710,2100 5740,2100 6192.68,2212.44 5840,3240 5840,3270 5840,3300 5840,3330 5840,3360 5840,3390 5840,3420 5840,3450
Vbulk1: C121.2 D103.4 Q100.9 Q101.9 RT100.2 TP101.1 TP102.1 | length 1063.2
  Top Layer w100: 3490,3900 3650,3740 ; 3788.23,3411.77 D103.4@4010,3411.77 ; 4825,2695 RT100.2@5260,2260
  other v1: 5280,2310 5280,2340 5280,2370 5280,2400 5280,2430 4380,3625 4415,3625 4445,3625 4475,3625 4505,3625 4380,3650 4415,3650 4445,3650 4475,3650 4505,3650 4380,3680 4415,3680 4445,3680 4475,3680 4505,3680 3010,3960 3050,3960 3090,3960 3130,3960 3170,3960 3210,3960 3250,3960 3010,4000 3050,4000 3090,4000 3130,4000 3170,4000 3210,4000 3250,4000 3010,4040 3050,4040 3090,4040 3130,4040 3170,4040 3210,4040 3250,4040 3010,4080 3050,4080 3090,4080 3130,4080 3170,4080 3210,4080 3250,4080
Vbulk_SNS: C328.1 J301.15 R352.1 R355.2 | length 1565.8
  Top Layer w20: R355.2@4578.62,526.38 C328.1@4578.62,565 ; v1(4580,485) 4580,515 R355.2@4585,520 ; C328.1@4584.37,566.81 4584.37,591.39 4610.75,617.77 4610.75,703.78 J301.15@4610.91,703.94
  Bottom Layer w12: R352.1@5611.03,1007.47 R352.1@5627.4,991.1
  Bottom Layer w20: v1(4580,485) 4580,585 4638.42,643.42 5094.91,643.42 5371.5,920 5578.94,920 5630,971.06 R352.1@5630,980
VMON: J302.1
ZCD: C117.2 C118.2 C119.2 C121.1 D107.1 D107.3 Q103.2 Q103.3-4-5-6-7-8 R113.2 R124.1 R303.1 R347.1 TP105.1 TP106.1 U101.4 | length 6741.6
  Top Layer w20: 4730,1330 4730,1290 4757.87,1262.13 4778.19,1262.13 4780,1260.32 R303.1@4780,1260 ; 4730,1335 4730,1360 4820,1450 5030,1450 5100,1380 v1(5960,1380) ; R347.1@4780,1203.62 R303.1@4780,1256.38
  Signal Layer 2 w20: v1@3440,2360 3440,2487 ; 3440,2477 3387,2530 3387,3407 3420,3440 v1(3490,3440)
  Signal Layer 3 w20: v1@3730,2480 3830,2380 3830,2115 3910,2035 4795,2035
  Bottom Layer w20: Q103.2@3400.63,3478.11 R124.1@3490,3478.11 ; v1(3437.99,2353.82) 3437.99,2379.41 3446.85,2388.27 3525.59,2388.27 C117.2@3564.96,2427.64 ; v1(3490,3440) R124.1@3490,3478.11 ; R124.1@3500,3470 3491.89,3478.11 R124.1@3490,3478.11 ; 3683.07,2486.69 3692.91,2486.69 ; 3712.6,2476.85 v1(3732.28,2476.85) ; v1(5950,1440) 5960,1430 v1(5960,1380)
  Bottom Layer w50: 4575,3285 5110,2750 ; 5110,2060 5114.54,2055.46 5114.54,2035.55 5150,2000.09 5169.91,2000.09 5740,1430 5960,1430 5980,1430 ; 5819.88,1424.65 5950,1424.65 ; 5980,1424.65 6107.28,1424.65 ; 6008.86,1430 6110,1430
  other v1: 5800,1440 5830,1440 5860,1440 5890,1440 5920,1440 5980,1440 3665,2470 4220,2920 4250,2920 4280,2920 4220,2950 4250,2950 4280,2950 4220,2980 4250,2980 4280,2980 3470,3230 3470,3260 3470,3290 3470,3320 3470,3350 3470,3380 3470,3410 4460,4100 4500,4100 4535,4100 4570,4100 4605,4100 4460,4135 4500,4135 4535,4135 4570,4135 4605,4135
ZCD_SNS: R309.1 R341.2 U300.7 | length 120.4
  Top Layer w12: R341.2@4932.8,1116.89 U300.7@4932.8,1172.4
  Top Layer w20: R309.1@4920,1053.62 4920,1057.56 4937.87,1075.43 4937.87,1108.19 4939.69,1110 R341.2@4940,1110
pads on no net: J100. J100.4 J100.5 J102.MH1 J102.MH2 J301.1 J301.2 J301.3 J301.4 J301.5 J301.6 J301.8 J301.13 J301.16 J301.18 J301.20 J301.23 J301.24 J301.26 J301.29 J301.30 J301.31 J301.32 J301.34 J301.36 J301.37 J301.39 J301.41 J301.42 J301.43 J301.44 J301.45 J301.48 J301.50 J301.52 J301.56 J301.59 J301.61 J301.63 J301.66 J301.67 J301.69 J301.71 J301.73 J301.75 J301.77 J301.79 J301.80 J301.81 J301.82 J301.85 J301.86 J301.87 J301.88 J301.89 J301.90 J301.91 J301.92 J301.93 J301.94 J301.95 J301.96 J301.99 J301.100 J301.101 J301.102 J301.103 J301.104 J301.105 J301.106 J301.107 J301.108 J301.109 J301.110 J301.113 J301.114 J301.115 J301.116 J301.117 J301.118 J301.119 J301.120 J301.181 J301.182 J301.185 J301.186 RT301.1S RT301.2S U102.6 U102.7 U102.12 U102.13 U105.4 U107.2 U107.5
copper on no net:
  other v2: 6305.59,406.5 6344.96,406.5 6305.59,426.18 6344.96,426.18 6305.59,445.87 6344.96,445.87

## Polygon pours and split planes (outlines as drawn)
PGND on Bottom Layer "PGND" (solid, remove dead copper, pour order 301): 17 vertices, not listed, extent 5930,210 6810,1240
PGND on Bottom Layer "PGND" (solid, remove dead copper, pour order 305): 7220,3000 6460,3000 6420,2960 6420,2780 6460,2740 6540,2740 6590,2690 6590,2430 6780,2240 7190,2240 7260,2310 7260,2960
PGND on Bottom Layer "PGND" (solid, remove dead copper, pour order 401): 6430,2710 6400,2680 6400,2530 6380,2510 6150,2510 5980,2680 5950,2680 5930,2660 5930,2590 6130,2390 6440,2390 6540,2490 6540,2690 6520,2710
Vbulk1 on Bottom Layer "BOTTOM_LAYER_VBULK1_P405" (solid, remove dead copper, pour order 405): 5060,3830 5050,3840 4390,3840 4340,3790 4340,3590 4360,3570 4640,3570 4800,3730 5060,3730
NetF150_1 on Bottom Layer "BOTTOM_LAYER_NETF150_1_P422" (solid, pour order 422): 1923.09,1279.48 2073.09,1279.48 2273.09,1079.48 2273.09,989.48 2193.09,909.48 1873.09,909.48 1823.09,959.48 1823.09,1179.48 1913.09,1269.48
NetF150_2 on Bottom Layer "BOTTOM_LAYER_NETF150_2_P424" (solid, pour order 424): 2379.11,1611.39 2529.11,1461.39 2529.11,1341.39 2459.11,1271.39 2239.11,1271.39 2199.11,1311.39 2199.11,1581.39 2229.11,1611.39
NetJ102_2 on Bottom Layer "BOTTOM_LAYER_NETJ102_2_P431" (solid, pour order 431): 2632.74,1272.94 2902.74,1002.94 3012.74,1002.94 3102.74,1092.94 3102.74,1282.94 3032.74,1352.94 2912.74,1352.94 2762.74,1502.94 2642.74,1502.94 2632.74,1492.94
SWNODE on Bottom Layer "SWNODE" (solid, remove dead copper, pour order 155): 4245,4035 4245,3585 4290,3540 4670,3540 4685,3535 4720,3500 4720,3420 4690,3390 4600,3390 4030,3390 3870,3550 3870,4070 3920,4120 4160,4120
PGND on Bottom Layer "PGND" (solid, remove dead copper, pour order 175): 6530,1310 6530,1390 6485,1435 6180,1435 6170,1425 6170,1400 6160,1390 6100,1330 5770,1330 5760,1320 5760,1140 5785,1115 6410,1115 6530,1235
Line on Bottom Layer "Neutral" (solid, remove dead copper, pour order 167): 3260,3680 3260,3740 3230,3770 2960,3770 2920,3730 2920,3370 2860,3310 2860,2880 3120,2620 3250,2620 3280,2650 3280,3590 3260,3610
Line on Bottom Layer "Neutral" (solid, remove dead copper, pour order 159): 2970.47,2461.1 2970.47,2417.8 2974.41,2413.86 3159.45,2413.86 3171.26,2425.67 3277.56,2425.67 3285.43,2433.54 3285.43,2444.57 3261.02,2468.98 3190.94,2468.98 3175.2,2484.72 2994.09,2484.72
ZCD on Bottom Layer "ZCD" (solid, remove dead copper, pour order 161): 21 vertices, not listed, extent 3420,2290 3780,2510
VBB on Bottom Layer "VBB" (solid, remove dead copper, pour order 233): 21 vertices, not listed, extent 6020,3030 7260,3840
NetC105_2 on Bottom Layer "C105_2" (solid, remove dead copper, pour order 281): 2100,2170 2090,2160 2090,1830 2200,1720 2240,1720 2250,1730 2250,1810 2310,1870 2310,1920 2250,1980 2250,2140 2220,2170
AINN on Bottom Layer "BOTTOM_LAYER_AINN_P463" (solid, pour order 463): 3550,2285 3670,2285 4010,1945 4010,1760 3985,1735 3825,1735 3795,1705 3555,1705 3520,1740 3520,2255
NetC103_1 on Bottom Layer "BOTTOM_LAYER_NETC103_1_P466" (solid, pour order 466): 3525.44,2961.77 3745.44,3181.77 3810.44,3181.77 4345.44,2646.77 4640.44,2646.77 4730.44,2556.77 4730.44,2436.77 4645.44,2351.77 3965.44,2351.77 3670.44,2646.77 3550.44,2646.77 3525.44,2671.77
ZCD on Bottom Layer "ZCD" (solid, remove dead copper, pour order 223): 4370,4210 5015,4210 5060,4165 5060,4010 5050,4000 4375,4000 4310,4065 4310,4150
Vbulk1 on Bottom Layer "Vbulk1" (solid, remove dead copper, pour order 169): 3610,4180 3715,4180 3765,4130 3765,3905 3710,3850 2950,3850 2900,3900 2900,4150 2930,4180
ZCD on Bottom Layer "Bottom Layer-ZCD" (solid, remove dead copper, pour order 485): 25 vertices, not listed, extent 3350,1400 6160,3720
ZCD on Bottom Layer "BOTTOM_LAYER_ZCD_P488" (solid, pour order 488): 5035,4235 6105,4235 6170,4170 6170,4100 5660,3590 5390,3590 5305,3505 5105,3505 5035,3575 5035,3880 4905,4010 4905,4205 5005,4205 5020,4220
NetC102_1 on Bottom Layer "C102_1" (solid, remove dead copper, pour order 237): 25 vertices, not listed, extent 2650,1100 3725,2170
AINP on Bottom Layer "C105_1" (solid, remove dead copper, pour order 489): 3530,1315 3490.29,1354.71 3490.29,1538.14 3525.29,1573.14 3711.86,1573.14 3730,1555 3730,1345 3700,1315
PGND on Bottom Layer "PGND" (solid, remove dead copper, pour order 283): 32 vertices, not listed, extent 4035,190.44 6050.33,1490
Vbulk on Top Layer "Vbulk" (solid, remove dead copper, pour order 171): 5260,2140 5240,2120 5240,1570 5330,1480 6480,1480 6510,1510 6510,1690 6480,1720 5990,1720 5930,1780 5930,2040 5830,2140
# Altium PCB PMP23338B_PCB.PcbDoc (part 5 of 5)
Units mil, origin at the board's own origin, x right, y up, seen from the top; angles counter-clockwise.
Board outline 5708.66 x 4330.71 mil, 6 copper layers (Top Layer, Signal Layer 1, Signal Layer 2, Signal Layer 3, Signal Layer 4, Bottom Layer), stack 65.8 mil thick; 209 components, 108 nets, 629 pads, 390 vias.

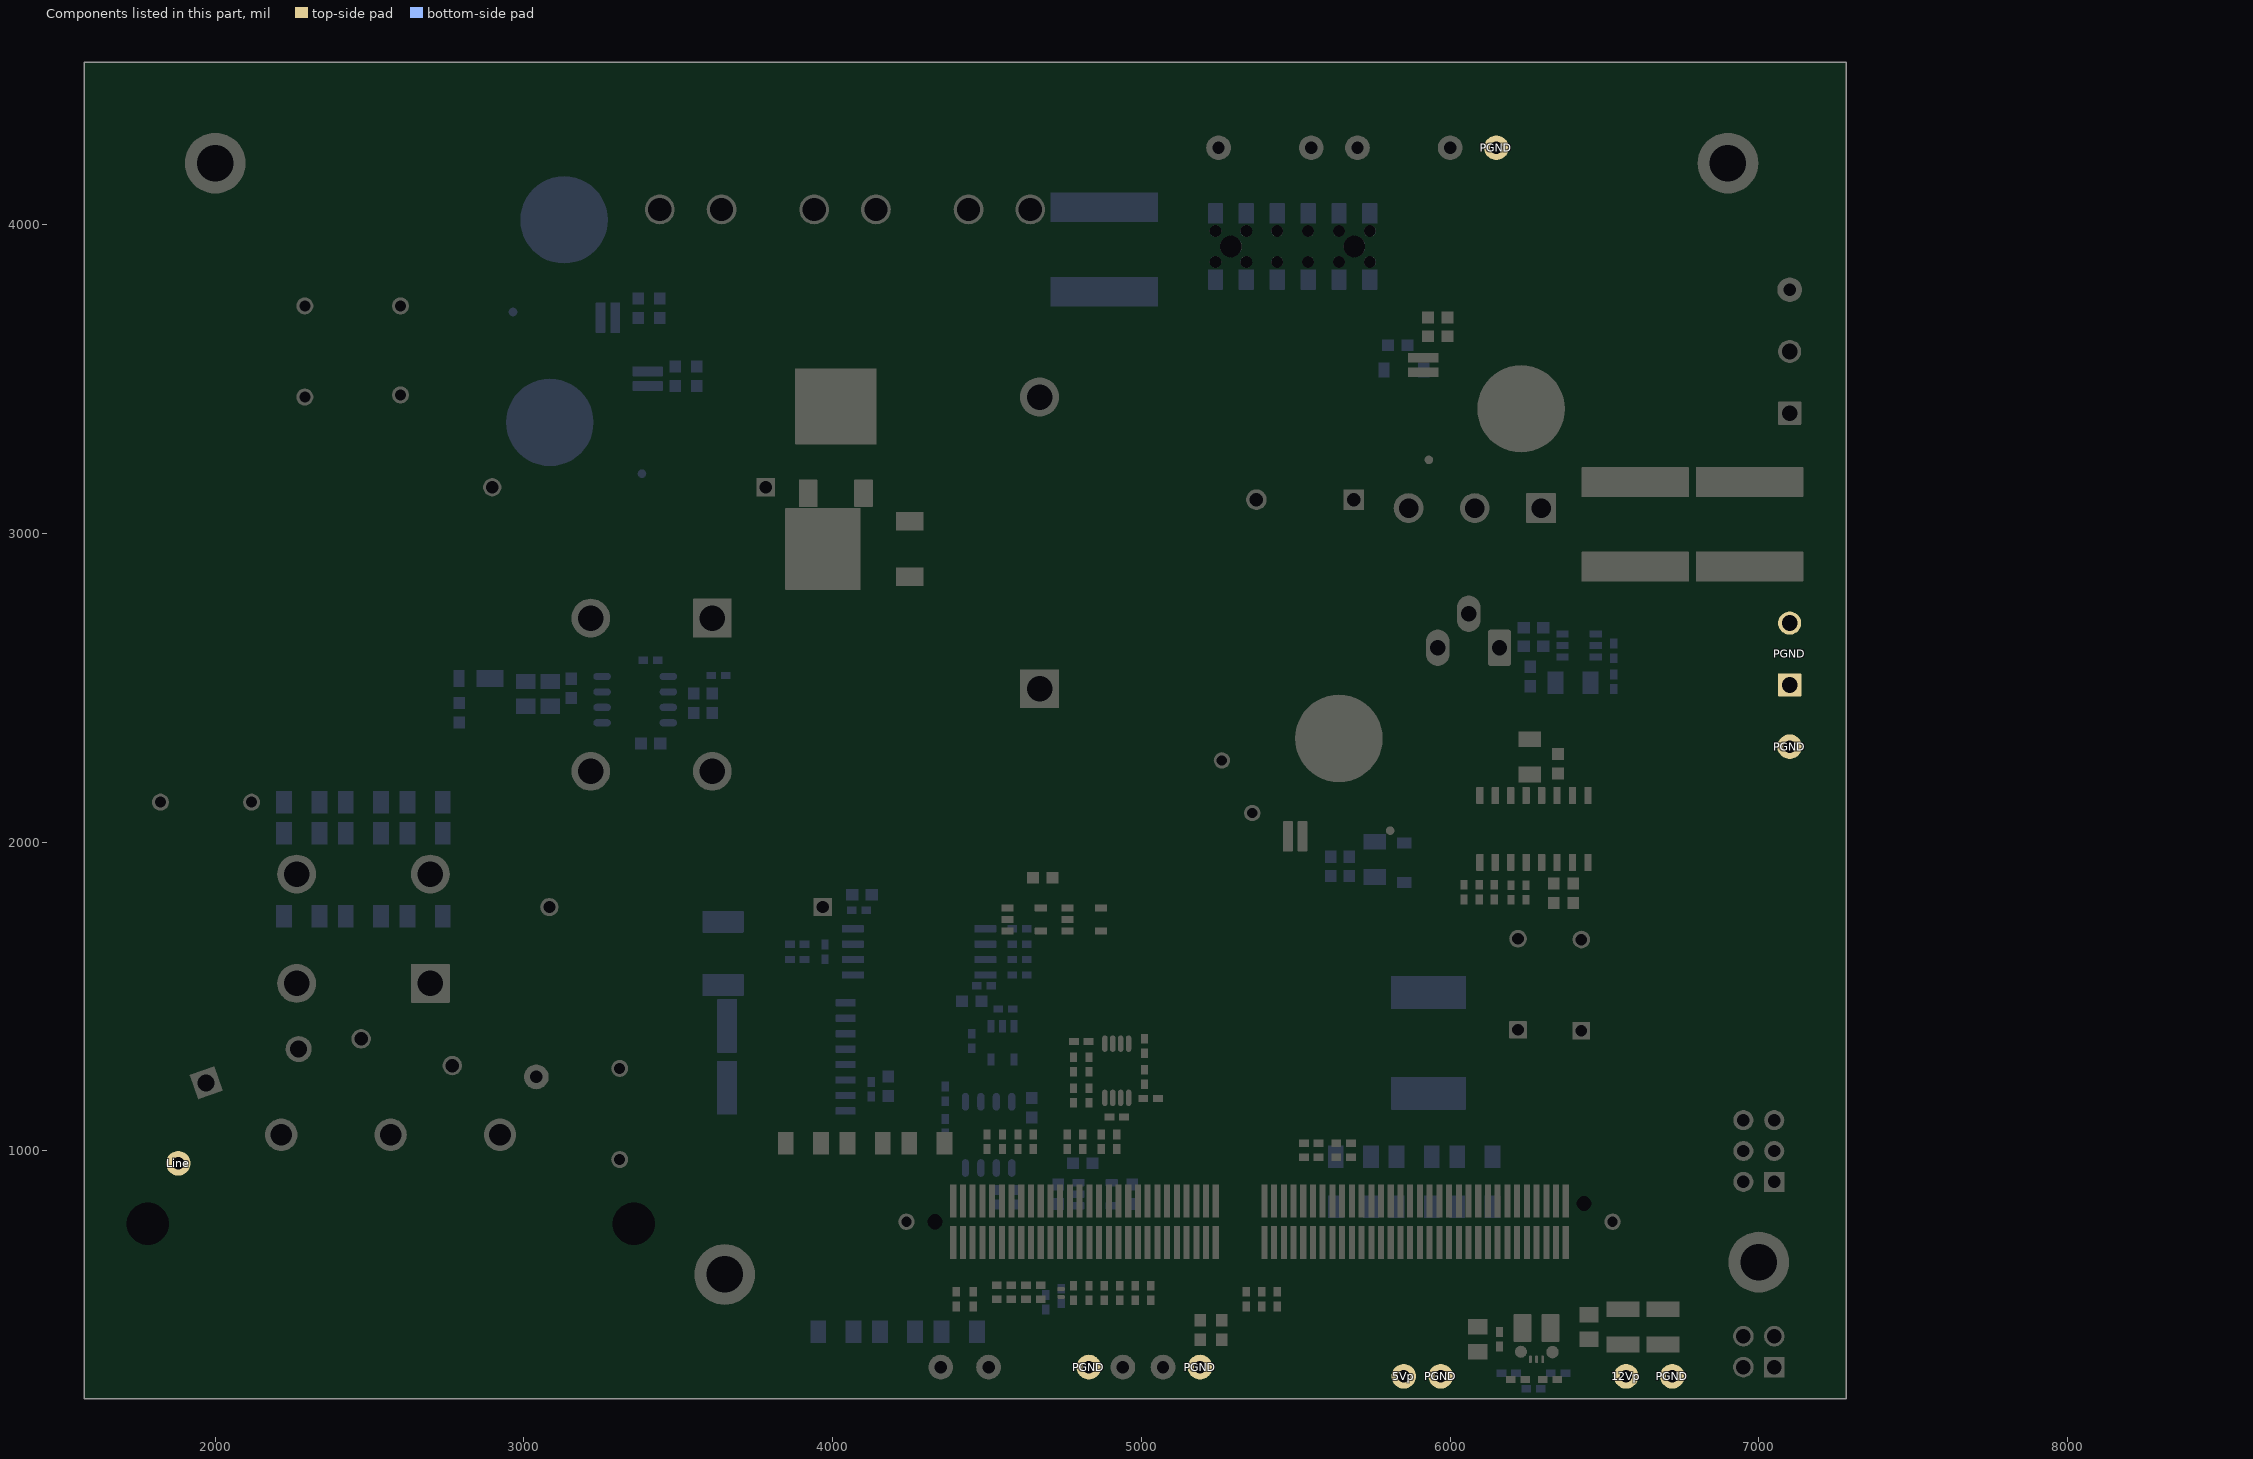
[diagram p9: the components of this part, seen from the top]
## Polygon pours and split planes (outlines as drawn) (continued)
NetJ102_2 on Top Layer "TOP_LAYER_NETJ102_2_P415" (solid, pour order 415): 2630,1270 2900,1000 3010,1000 3100,1090 3100,1280 3030,1350 2910,1350 2760,1500 2640,1500 2630,1490
NetF150_2 on Top Layer "TOP_LAYER_NETF150_2_P414" (solid, pour order 414): 2380,1610 2530,1460 2530,1340 2460,1270 2240,1270 2200,1310 2200,1580 2230,1610
NetF150_1 on Top Layer "TOP_LAYER_NETF150_1_P413" (solid, pour order 413): 1920,1280 2070,1280 2270,1080 2270,990 2190,910 1870,910 1820,960 1820,1180 1910,1270
Line on Top Layer "Neutral" (solid, remove dead copper, pour order 163): 3120,2620 2860,2880 2860,3350 2920,3410 2920,3480 2960,3520 3240,3520 3300,3460 3300,2670 3250,2620
ZCD on Top Layer "ZCD" (solid, remove dead copper, pour order 173): 4210,3080 4200,3070 4200,2830 4210,2820 4290,2820 4300,2830 4300,3070 4290,3080
PGND on Top Layer "PGND" (solid, remove dead copper, pour order 187): 6000,1330 6105,1435 6485,1435 6530,1390 6530,1180 6500,1150 5810,1150 5760,1200 5760,1290 5800,1330
NetD106_1 on Top Layer "D106_1" (solid, remove dead copper, pour order 201): 19 vertices, not listed, extent 5620,2670 6380,3190
VBB on Top Layer "VBB" (solid, remove dead copper, pour order 203): 21 vertices, not listed, extent 6020,3030 7260,3840
PGND on Top Layer "PGND" (solid, remove dead copper, pour order 207): 7220,3000 6460,3000 6420,2960 6420,2780 6460,2740 6540,2740 6590,2690 6590,2430 6780,2240 7190,2240 7260,2310 7260,2960
NetC105_2 on Top Layer "C105_2" (solid, remove dead copper, pour order 251): 17 vertices, not listed, extent 2090,1720 3300,2300
PE on Top Layer "PE" (solid, remove dead copper, pour order 263): 1640,4520 1590,4470 1590,2010 1620,1980 1720,1980 1850,2110 1850,3410 2150,3710 2620,3710 2640,3730 2640,4280 2400,4520
NetC102_1 on Top Layer "C102_1" (solid, remove dead copper, pour order 387): 20 vertices, not listed, extent 2650,1110 3735,1950
PE on Top Layer "PE" (solid, remove dead copper, pour order 395): 25 vertices, not listed, extent 1590,210 3750,1110
PGND on Top Layer "PGND" (solid, remove dead copper, pour order 397): 17 vertices, not listed, extent 6130,1760 6430,1960
Vbulk on Top Layer "Vbulk" (solid, remove dead copper, pour order 399): 6190,2120 6170,2140 6170,2320 6210,2360 6400,2360 6470,2290 6470,2135 6455,2120
Vbulk on Top Layer "Vbulk" (solid, remove dead copper, pour order 199): 20 vertices, not listed, extent 5250,1930 6050,3480
5Vp on Top Layer "5Vp" (solid, remove dead copper, pour order 450): 6065,495 6055,485 6055,405 6060,400 6175,400 6190,385 6260,385 6265,390 6265,470 6260,475 6110,475 6090,495
PGND on Top Layer "PGND" (solid, remove dead copper, pour order 452): 6020,380 5930,290 5930,230 5950,210 6110,210 6175,275 6230,275 6250,295 6250,360 6240,370 6190,370 6180,380
PGND on Top Layer "PGND" (solid, remove dead copper, pour order 454): 6245,575 6235,565 6235,505 6250,490 6350,490 6370,470 6370,430 6380,420 6410,420 6420,430 6735,430 6750,445 6750,535 6710,575
12Vp on Top Layer "12Vp" (solid, remove dead copper, pour order 456): 6315,305 6335,285 6385,285 6455,215 6590,215 6695,320 6735,320 6750,335 6750,405 6735,420 6430,420 6385,375 6320,375 6315,370
NetC103_1 on Top Layer "TOP_LAYER_NETC103_1_P469" (solid, pour order 469): 17 vertices, not listed, extent 3520,2350 4735,3185
SWNODE on Top Layer "SWNODE" (solid, remove dead copper, pour order 475): 4237.86,3982.86 4195,3940 3900,3940 3867.86,3972.14 3867.86,4087.33 3910.54,4130 4185.19,4130 4237.86,4077.33
ZCD on Top Layer "TOP_LAYER_ZCD_P476" (solid, pour order 476): 4340,4100 4390,4150 4685,4150 4730,4105 4730,3980 4695,3945 4375,3945 4340,3980
Vbulk1 on Top Layer "Vbulk1" (solid, remove dead copper, pour order 165): 30 vertices, not listed, extent 2900,2170 5850,4140
AINN on Top Layer "C105_1" (solid, remove dead copper, pour order 460): 3790,1745 3820,1715 4000,1715 4010,1725 4010,1945 3670,2285 3550,2285 3520,2255 3520,2015
Vbulk1 on Top Layer "TOP_LAYER_VBULK1_P481" (solid, pour order 481): 4380,3735 4510,3735 4540,3705 4540,3365 4515,3340 4340,3340 4295,3385 4295,3535 4340,3580 4340,3695 4340,3580 4340,3695
5Vp on Signal Layer 2 "5Vp" (solid, remove dead copper, pour order 457): 6066.97,496.27 6056.97,486.27 6056.97,406.27 6061.97,401.27 6176.97,401.27 6191.97,386.27 6261.97,386.27 6266.97,391.27 6266.97,471.27 6261.97,476.27 6111.97,476.27 6091.97,496.27
NetJ102_2 on Signal Layer 2 "SIGNAL_LAYER_2_NETJ102_2_P429" (solid, pour order 429): 2630,1270 2900,1000 3010,1000 3100,1090 3100,1280 3030,1350 2910,1350 2760,1500 2640,1500 2630,1490
NetF150_2 on Signal Layer 2 "SIGNAL_LAYER_2_NETF150_2_P427" (solid, pour order 427): 2380,1610 2530,1460 2530,1340 2460,1270 2240,1270 2200,1310 2200,1580 2230,1610
NetF150_1 on Signal Layer 2 "SIGNAL_LAYER_2_NETF150_1_P418" (solid, pour order 418): 1923.09,1279.48 2073.09,1279.48 2273.09,1079.48 2273.09,989.48 2193.09,909.48 1873.09,909.48 1823.09,959.48 1823.09,1179.48 1913.09,1269.48
Line on Signal Layer 2 "Neutral" (solid, remove dead copper, pour order 317): 3300,2670 3300,3460 3240,3520 2960,3520 2920,3480 2920,3440 2920,3410 2860,3350 2860,2880 3120,2620 3250,2620
ZCD on Signal Layer 2 "SIGNAL_LAYER_2_ZCD_P411" (solid, remove dead copper, pour order 411): 20 vertices, not listed, extent 3450,2820 5030,3720
PGND on Signal Layer 2 "PGND" (solid, remove dead copper, pour order 311): 6000,1330 6105,1435 6440,1435 6450,1425 6450,1300 6420,1270 6330,1180 5790,1180 5760,1210 5760,1320 5770,1330
VBB on Signal Layer 2 "VBB" (solid, remove dead copper, pour order 229): 21 vertices, not listed, extent 6020,3030 7260,3840
ZCD on Signal Layer 2 "ZCD" (solid, remove dead copper, pour order 231): 3415.02,2362.21 3415.02,2482.21 3445.02,2512.21 3735.02,2512.21 3755.02,2492.21 3755.02,2362.21 3735.02,2342.21 3435.02,2342.21 3425.02,2352.21
Vbulk on Signal Layer 2 "Vbulk" (solid, remove dead copper, pour order 291): 20 vertices, not listed, extent 5270,2060 5860,3500
ZCD on Signal Layer 2 "ZCD" (solid, remove dead copper, pour order 339): 4860,4155 5140,3875 5140,3670 4990,3520 4810,3520 4360,3970 4360,4120 4395,4155
NetC105_2 on Signal Layer 2 "C105_2" (solid, remove dead copper, pour order 361): 17 vertices, not listed, extent 2090,1720 3300,2300
NetC102_1 on Signal Layer 2 "C102_1" (solid, remove dead copper, pour order 391): 20 vertices, not listed, extent 2650,1110 3740,1950
AINN on Signal Layer 2 "C105_1" (solid, remove dead copper, pour order 462): 3790,1745 3820,1715 4000,1715 4010,1725 4010,1945 3670,2285 3550,2285 3520,2255 3520,2015
NetC103_1 on Signal Layer 2 "SIGNAL_LAYER_2_NETC103_1_P465" (solid, pour order 465): 3525,2960 3745,3180 3810,3180 4345,2645 4640,2645 4730,2555 4730,2435 4645,2350 3965,2350 3670,2645 3550,2645 3525,2670
AINP on Signal Layer 2 "C105_1" (solid, remove dead copper, pour order 491): 3530,1315 3490.29,1354.71 3490.29,1538.14 3525.29,1573.14 3711.86,1573.14 3730,1555 3730,1345 3700,1315
PGND on Signal Layer 4 "PGND" (solid, remove dead copper, pour order 185): 18 vertices, not listed, extent 6370,970 7280,1460
NetJ102_2 on Signal Layer 4 "SIGNAL_LAYER_4_NETJ102_2_P432" (solid, pour order 432): 2632.74,1274.62 2902.74,1004.62 3012.74,1004.62 3102.74,1094.62 3102.74,1284.62 3032.74,1354.62 2912.74,1354.62 2762.74,1504.62 2642.74,1504.62 2632.74,1494.62
NetF150_2 on Signal Layer 4 "SIGNAL_LAYER_4_NETF150_2_P425" (solid, pour order 425): 2380,1610 2530,1460 2530,1340 2460,1270 2240,1270 2200,1310 2200,1580 2230,1610
NetF150_1 on Signal Layer 4 "SIGNAL_LAYER_4_NETF150_1_P416" (solid, pour order 416): 1920,1280 2070,1280 2270,1080 2270,990 2190,910 1870,910 1820,960 1820,1180 1910,1270
Vbulk1 on Signal Layer 4 "Vbulk1" (solid, remove dead copper, pour order 299): 24 vertices, not listed, extent 2900,2170 5310,4140
PGND on Signal Layer 4 "PGND" (solid, remove dead copper, pour order 191): 17 vertices, not listed, extent 5930,210 6810,1240
PGND on Signal Layer 4 "PGND" (solid, remove dead copper, pour order 409): 22 vertices, not listed, extent 5760,2240 7260,3000
PGND on Signal Layer 4 "PGND" (solid, remove dead copper, pour order 287): 25 vertices, not listed, extent 5650,1340 6470,2690
VBB on Signal Layer 4 "VBB" (solid, remove dead copper, pour order 265): 21 vertices, not listed, extent 6020,3030 7260,3840
Vbulk on Signal Layer 4 "Vbulk" (solid, remove dead copper, pour order 321): 19 vertices, not listed, extent 5320,2060 5860,3500
Line on Signal Layer 4 "Neutral" (solid, remove dead copper, pour order 333): 3135,2640 2860,2915 2860,3345 2920,3405 2920,3475 2960,3515 3240,3515 3300,3455 3300,2670 3270,2640
NetC105_2 on Signal Layer 4 "C105_2" (solid, remove dead copper, pour order 357): 17 vertices, not listed, extent 2090,1720 3300,2300
PGND on Signal Layer 4 "SIGNAL_LAYER_4_PGND_P459" (solid, pour order 459): 6201.43,666.64 6201.43,561.64 6186.43,546.64 6071.43,546.64 6071.43,621.64 6116.43,666.64
AINN on Signal Layer 4 "C105_1" (solid, remove dead copper, pour order 461): 3790,1745 3820,1715 3980,1715 4010,1745 4010,1945 3670,2285 3550,2285 3520,2255 3520,2015
NetC103_1 on Signal Layer 4 "SIGNAL_LAYER_4_NETC103_1_P464" (solid, pour order 464): 3530,2960 3750,3180 3815,3180 4350,2645 4645,2645 4735,2555 4735,2435 4650,2350 3970,2350 3675,2645 3555,2645 3530,2670
NetC102_1 on Signal Layer 4 "C102_1" (solid, remove dead copper, pour order 377): 20 vertices, not listed, extent 2650,1110 3735,1950
AINP on Signal Layer 4 "C105_1" (solid, remove dead copper, pour order 493): 3530,1315 3490.29,1354.71 3490.29,1538.14 3525.29,1573.14 3711.86,1573.14 3730,1555 3730,1345 3700,1315
PGND on Signal Layer 4 "PGND" (solid, remove dead copper, pour order 279): 33 vertices, not listed, extent 3815,210 6420,1935
NetJ102_2 on Signal Layer 3 "SIGNAL_LAYER_3_NETJ102_2_P430" (solid, pour order 430): 2632.74,1271.26 2902.74,1001.26 3012.74,1001.26 3102.74,1091.26 3102.74,1281.26 3032.74,1351.26 2912.74,1351.26 2762.74,1501.26 2642.74,1501.26 2632.74,1491.26
NetF150_2 on Signal Layer 3 "SIGNAL_LAYER_3_NETF150_2_P426" (solid, pour order 426): 2380,1610 2530,1460 2530,1340 2460,1270 2240,1270 2200,1310 2200,1580 2230,1610
NetF150_1 on Signal Layer 3 "SIGNAL_LAYER_3_NETF150_1_P419" (solid, pour order 419): 1923.09,1279.48 2073.09,1279.48 2273.09,1079.48 2273.09,989.48 2193.09,909.48 1873.09,909.48 1823.09,959.48 1823.09,1179.48 1913.09,1269.48
SWNODE on Signal Layer 3 "SWNODE" (solid, remove dead copper, pour order 225): 4240,4100 4240,3680 4380,3540 4680,3540 4720,3500 4720,3420 4690,3390 4030,3390 3880,3540 3880,3620 3880,4000 3880,4110 3910,4140 4200,4140
PGND on Signal Layer 3 "PGND" (solid, remove dead copper, pour order 209): 22 vertices, not listed, extent 5760,2240 7260,3000
VBB on Signal Layer 3 "VBB" (solid, remove dead copper, pour order 227): 21 vertices, not listed, extent 6020,3030 7260,3840
PGND on Signal Layer 3 "PGND" (solid, remove dead copper, pour order 273): 5770,1330 5760,1320 5760,1210 5800,1170 6330,1170 6420,1260 6420,1320 6410,1330
PGND on Signal Layer 3 "PGND" (solid, remove dead copper, pour order 289): 24 vertices, not listed, extent 5650,1320 6470,2690
Vbulk on Signal Layer 3 "Vbulk" (solid, remove dead copper, pour order 293): 20 vertices, not listed, extent 5250,2060 5860,3500
Line on Signal Layer 3 "Neutral" (solid, remove dead copper, pour order 315): 3247.5,3507.5 3300,3455 3300,2670 3250,2620 3120,2620 2860,2880 2860,3345 2920,3405 2920,3475 2960,3515 3240,3515
NetC105_2 on Signal Layer 3 "C105_2" (solid, remove dead copper, pour order 359): 17 vertices, not listed, extent 2090,1730 3300,2300
NetC102_1 on Signal Layer 3 "C102_1" (solid, remove dead copper, pour order 393): 20 vertices, not listed, extent 2650,1110 3735,1950
NetC103_1 on Signal Layer 3 "SIGNAL_LAYER_3_NETC103_1_P467" (solid, pour order 467): 3522.84,2961.77 3742.84,3181.77 3807.84,3181.77 4342.84,2646.77 4637.84,2646.77 4727.84,2556.77 4727.84,2436.77 4642.84,2351.77 3962.84,2351.77 3667.84,2646.77 3547.84,2646.77 3522.84,2671.77
ZCD on Signal Layer 3 "ZCD" (solid, remove dead copper, pour order 219): 31 vertices, not listed, extent 3450,1400 6000,4150
AINP on Signal Layer 3 "C105_1" (solid, remove dead copper, pour order 490): 3530,1315 3490.29,1354.71 3490.29,1538.14 3525.29,1573.14 3711.86,1573.14 3730,1555 3730,1345 3700,1315
Vbulk on Signal Layer 1 "Vbulk" (solid, remove dead copper, pour order 243): 19 vertices, not listed, extent 5250,1550 6455,3190
PGND on Signal Layer 1 "PGND" (solid, remove dead copper, pour order 307): 20 vertices, not listed, extent 5970,970 7280,1460
NetJ102_2 on Signal Layer 1 "SIGNAL_LAYER_1_NETJ102_2_P428" (solid, pour order 428): 2630,1270 2900,1000 3010,1000 3100,1090 3100,1280 3030,1350 2910,1350 2760,1500 2640,1500 2630,1490
NetF150_2 on Signal Layer 1 "SIGNAL_LAYER_1_NETF150_2_P423" (solid, pour order 423): 2380,1610 2530,1460 2530,1340 2460,1270 2240,1270 2200,1310 2200,1580 2230,1610
NetF150_1 on Signal Layer 1 "SIGNAL_LAYER_1_NETF150_1_P417" (solid, pour order 417): 1923.09,1277.82 2073.09,1277.82 2273.09,1077.82 2273.09,987.82 2193.09,907.82 1873.09,907.82 1823.09,957.82 1823.09,1177.82 1913.09,1267.82
Line on Signal Layer 1 "Neutral" (solid, remove dead copper, pour order 323): 3120,2620 2860,2880 2860,3350 2920,3410 2920,3480 2960,3520 3240,3520 3300,3460 3300,2670 3250,2620
ZCD on Signal Layer 1 "ZCD" (solid, remove dead copper, pour order 277): 31 vertices, not listed, extent 3450,1400 6000,4150
PGND on Signal Layer 1 "PGND" (solid, remove dead copper, pour order 295): 17 vertices, not listed, extent 5930,210 6810,1240
VBB on Signal Layer 1 "VBB" (solid, remove dead copper, pour order 217): 21 vertices, not listed, extent 6020,3030 7260,3840
Vbulk on Signal Layer 1 "Vbulk" (solid, remove dead copper, pour order 249): 17 vertices, not listed, extent 5290,2060 5860,3500
SWNODE on Signal Layer 1 "SWNODE" (solid, remove dead copper, pour order 213): 4740,3500 4740,3390 4720,3370 4020,3370 3870,3520 3870,4100 3890,4120 4210,4120 4260,4070 4260,3570 4310,3520 4720,3520
NetC105_2 on Signal Layer 1 "C105_2" (solid, remove dead copper, pour order 363): 19 vertices, not listed, extent 2090,1720 3300,2300
PGND on Signal Layer 1 "SIGNAL_LAYER_1_PGND_P458" (solid, pour order 458): 6200,665 6200,560 6185,545 6070,545 6070,620 6115,665
NetC103_1 on Signal Layer 1 "SIGNAL_LAYER_1_NETC103_1_P468" (solid, pour order 468): 3520.23,2961.77 3740.23,3181.77 3805.23,3181.77 4340.23,2646.77 4635.23,2646.77 4725.23,2556.77 4725.23,2436.77 4640.23,2351.77 3960.23,2351.77 3665.23,2646.77 3545.23,2646.77 3520.23,2671.77
AINN on Signal Layer 1 "C105_1" (solid, remove dead copper, pour order 477): 3790,1750 3820,1720 3960,1720 4010,1770 4010,1950 3670,2290 3550,2290 3520,2260 3520,2020
PGND on Signal Layer 1 "PGND" (solid, remove dead copper, pour order 482): 33 vertices, not listed, extent 3880,210 6420,1935
ZCD on Signal Layer 1 "SIGNAL_LAYER_1_ZCD_P486" (solid, pour order 486): 4905,4150 4990,4235 6150,4235 6195,4190 6195,4065 5690,3560 5300,3560 4805,4055 4900,4150
AINP on Signal Layer 1 "C105_1" (solid, remove dead copper, pour order 492): 3530,1315 3490.29,1354.71 3490.29,1538.14 3525.29,1573.14 3711.86,1573.14 3730,1555 3730,1345 3700,1315
NetC102_1 on Signal Layer 1 "C102_1" (solid, remove dead copper, pour order 389): 19 vertices, not listed, extent 2650,1110 3735,1950

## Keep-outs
Keep-Out Layer:
  text ".Layer_Name" at 577,-858.49 h60

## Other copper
Top Layer:
  text ".Layer_Name" at 1650,-10 h60
Bottom Layer:
  text ".Layer_Name" at 577,-858.49 h60

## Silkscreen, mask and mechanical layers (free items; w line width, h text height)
Top Overlay:
  region: 1720,2140 1720,2440 1620,2440 1620,2140
  lines w7.01: 3900,3530 3900,3766.22 ; 3904.65,3529.53 5479.45,3529.53 ; 5480,3530 5480,3766.22 ; 2816.93,1246.06 6281.5,1246.06 6281.5,3765.75 2816.93,3765.75 2816.93,1246.06
  lines w10: 4152.76,1205 6200,1205 ; 4152.76,1870 6200,1870 ; 4155,1205 4155,1870 ; 4380,450 4690,450 4720,420 4980,420 5040,360 ; 4450,390 4880,390 4910,360 ; 4820,240 4800,220 4790,220 5140,220 5160,240 ; 5230,4410 5390,4410 5500,4300 ; 5740,4310 5860,4430 6230,4430 ; 6050,4300 6080,4330 6190,4330 6210,4310 6220,4310 6230,4310 ; 6200,1202.72 6200,1872.01 ; 6405,1210 6405,1875 ; 6407.76,1210 8455,1210 ; 6407.76,1875 8455,1875 ; 8455,1207.72 8455,1877.01
  text "PMP23338 RevB" at 1640,3200 h108.27 r270
  text "+" at 6300,1655 h60
  text "Reserved for Bulk Cap" at 4935,1640 h108.27
  text "-" at 6300,1355.01 h60
  text ".Layer_Name" at 577,-858.49 h60
Bottom Overlay:
  text ".Layer_Name" at 577,-858.49 h60
Top Paste:
  text ".Layer_Name" at 577,-858.49 h60
Bottom Paste:
  text ".Layer_Name" at 577,-858.49 h60
Top Solder:
  text ".Layer_Name" at 577,-858.49 h60
  text ".Layer_Name" at 577,-858.49 h60
Bottom Solder:
  rectangle: 3505,1340 3615,1500
  rectangle: 3345,1120 3610,1290
  text ".Layer_Name" at 577,-858.49 h60
Drill Guide:
  text ".Layer_Name" at 577,-858.49 h60
M1 Board Outline:
  the board outline again, w7.01
  text ".Layer_Name" at 577,-858.49 h60
M2 Board Dimensions:
  rectangle: 125,-400 500,-275
  rectangle: 0,-275 125,-150
  lines w7: 0,-275 1000,-275 ; 125,-400 125,-150 ; 250,-400 250,-150 ; 500,-400 500,-150 ; 750,-400 750,-150 ; 0,-400 0,-150 1000,-150 1000,-400 0,-400
  text ".Layer_Name" at 577,-858.49 h60
M3 3D STEP Top:
  text ".Layer_Name" at 577,-858.49 h60
M4 3D STEP Bottom:
  text ".Layer_Name" at 577,-858.49 h60
M5 Assembly Top:
  lines w10: -292,-930.17 6308,-930.17 ; -292,-726.83 6310,-726.83 ; -292,-523.5 -292,-1133.5 3713,-1133.5 6310,-1133.5 6310,-523.5 -291.5,-523.5 -291.5,-1133.5 1284,-1133.5 ; 2173,-1133.5 2173,-523.5 ; 3440,-726.83 3440,-523.5 ; 4280,-726.83 4280,-523.5 ; 4902,-1140 4902,-937.17
  text "COMPONENTS MARKED 'DNP' SHOULD NOT BE POPULATED." at 1153.5,-318.5 h60
  text "ASSEMBLY VARIANT:" at 1153,-434 h60
  text ".VariantName" at 2189,-434 h60
  text "PCB VIEWED FROM TOP SIDE" at -228.5,-655.67 h60
  text "BOARD #:" at 2248,-655.67 h60
  text ".PRJ_Number" at 2793.5,-655.67 h60
  text "REV:" at 3638,-655.67 h60
  text ".PCB_Rev" at 3929.5,-655.67 h60
  text "SVN REV:" at 4476,-655.67 h60
  text ".VersionControl_RevNumber" at 4982,-655.67 h60
  text "TID #:" at 2248,-859 h60
  text ".TID" at 2793.5,-859 h60
  text "PLOT NAME =" at -228.5,-1064.34 h60
  text ".plot_File_Name" at 577,-1064.34 h60
  text "GENERATED    :" at 2250,-1064.34 h60
  text ".Print_Date" at 3119.5,-1064.34 h60
  text ".Print_Time" at 3848.5,-1064.34 h60
  text "TEXAS INSTRUMENTS" at 5113,-1064.34 h60
M6 Assembly Bottom:
  lines w10: -292.5,-727.33 6309.5,-727.33 ; -290.5,-930.67 6309.5,-930.67 ; 1115.5,-1140.5 1115.5,-937.67 ; 1737.5,-727.33 1737.5,-524 ; 2577.5,-727.33 2577.5,-524 ; 3844.5,-1134 3844.5,-524 ; 4733.5,-1134 6309,-1134 6309,-524 -292.5,-524 -292.5,-1134 2304.5,-1134 6309.5,-1134 6309.5,-524
  text "COMPONENTS MARKED 'DNP' SHOULD NOT BE POPULATED." at 6853.97,-314.06 h60
  text ".VariantName" at 5058,-434 h60
  text "ASSEMBLY VARIANT:" at 6097,-434 h60
  text ".VersionControl_RevNumber" at 1035.5,-656.17 h60
  text "SVN REV:" at 1541.5,-656.17 h60
  text ".PCB_Rev" at 2088,-656.17 h60
  text "REV:" at 2379.5,-656.17 h60
  text ".PRJ_Number" at 3224,-656.17 h60
  text "BOARD #:" at 3769.5,-656.17 h60
  text "PCB VIEWED FROM BOTTOM SIDE" at 6246,-656.17 h60
  text ".TID" at 3224,-859.5 h60
  text "TID #:" at 3769.5,-859.5 h60
  text "TEXAS INSTRUMENTS" at 904.5,-1064.84 h60
  text ".Print_Time" at 2169,-1064.84 h60
  text ".Print_Date" at 2898,-1064.84 h60
  text "GENERATED    :" at 3767.5,-1064.84 h60
  text ".plot_File_Name" at 5440.5,-1064.84 h60
  text "PLOT NAME =" at 6246,-1064.84 h60
M9 Title Sheet:
  drawing of 57 lines, arcs and shapes, not listed
  text "1" at 739.84,8036.5 h70
  text "2" at 3235.5,8036.5 h70
  text "3" at 5724.84,8036.5 h70
  text "4" at 8231.51,8036.5 h70
  text "5" at 10730.5,8036.5 h70
  text "6" at 13235.5,8036.5 h70
  text "A" at -416.5,6893.5 h70
  text "A" at 14383.5,6893.5 h70
  text "B" at -416.5,4513.5 h70
  text "B" at 14383.5,4513.5 h70
  text "C" at -416.5,2138.5 h70
  text "C" at 14383.5,2138.5 h70
  text "PROJECT TITLE:" at 11343.5,277.5 h45
  text ".PRJ_Title" at 11393.5,144.17 h70
  text "DESIGNED FOR:" at 11343.5,-23.5 h45
  text ".PRJ_Customer" at 11393.5,-163.5 h70
  text "D" at -416.5,-231.5 h70
  text "D" at 14383.5,-231.5 h70
  text "FILE NAME:" at 11343.5,-323.5 h45
  text ".PCB_File_Name_No_Path" at 11393.5,-443.5 h70
  text "Texas Instruments (TI) and/or its licensors do not warrant the accuracy or completeness of this specification" at 6374,-605.34 h45
  text "ENGINEER:" at 11343.5,-613.5 h45
  text "LAYOUT BY:" at 12848.5,-613.5 h45
  text "or any information contained therein. TI and/or its licensors do not warrant that this design will meet" at 6329.01,-718 h45
  text ".PRJ_Engineer" at 11393.5,-768.49 h70
  text ".PCB_Layout" at 12899,-768.49 h70
  text "the specifications, will be suitable for your application or fit for any particular purpose, or will operate in" at 6329.01,-830.67 h45
  text ".Layer_Name" at 577,-858.49 h60
  text "ALTIUM DESIGNER VERSION:" at 12848.5,-923.5 h45
  text "an implementation. TI and/or its licensors do not warrant that the design is production worthy. You should" at 6329.01,-943.33 h45
  text "completely validate and test your design implementation to confirm the system functionality for your application." at 6374,-1056 h45
  text ".print_Scale" at 11393.5,-1056.83 h70
  text ".Application_BuildNumber" at 12899,-1056.83 h70
  text "1" at 739.84,-1263.5 h70
  text "2" at 3235.5,-1263.5 h70
  text "3" at 5724.84,-1263.5 h70
  text "4" at 8231.51,-1263.5 h70
  text "5" at 10730.5,-1263.5 h70
  text "6" at 13235.5,-1263.5 h70
M10 Fab Notes:
  drawing of 189 lines, arcs and shapes, not listed
  text "DESIGN INFORMATION" at 12382.02,6356.17 h60
  text "MIN. TRACK WIDTH:" at 11737.46,6224.05 h60
  text "8" at 12833.7,6224.05 h60
  text "MIL" at 12988.46,6224.05 h60
  text "MIN. CLEARANCE:" at 11737.46,6099.92 h60
  text "0.2" at 12773.7,6099.93 h60
  text "mm" at 12988.46,6099.92 h60
  text "MIN. VIA PAD SIZE:" at 11737.46,5975.8 h60
  text "20" at 12803.71,5975.8 h60
  text "MIL" at 12988.46,5975.8 h60
  text "0.05mm (2MIL)" at 12432.46,5845.9 h60
  text "MINIMUM ANNULAR RING" at 11408.23,5837.67 h60
  text "EXTERNAL" at 13140.46,5837.67 h60
  text "PER" at 11608.23,5727.55 h60
  text "IPC-D-275 CLASS 2 LEVEL C" at 11828.23,5727.54 h60
  text "MIL, HOLES" at 13316.46,5627.07 h60
  text "+/-" at 12924,5618.48 h60
  text "+/-" at 13778,5618.48 h60
  text "REGISTRATION TOLERANCES:" at 11408.23,5617.42 h60
  text "METAL" at 12608,5617.42 h60
  text "5" at 13184.2,5617.42 h60
  text "3" at 14017.2,5617.42 h60
  text "MIL" at 14133.46,5617.42 h60
  text "HOLE SIZE TOLERANCE (UNLESS OTHERWISE SPECIFIED):" at 11408.23,5519.1 h60
  text "+/-" at 13778,5516.23 h60
  text "3" at 14017.2,5515.17 h60
  text "MIL" at 14133.46,5515.17 h60
  text "MATERIAL:" at 11333.46,5377.52 h60
  text "FR-4 High Tg" at 12319.9,5249 h60
  text "X" at 12175.46,5241.01 h60
  text "FR-408" at 11754.46,5236.49 h60
  text "OTHER" at 13242.46,5236.49 h60
  text "62 MIL (1.6mm) +/-10%" at 12074.56,5093.46 h60
  text "X" at 11954.46,5091.01 h60
  text "THICKNESS:" at 11408.23,5085.24 h60
  text "OTHER" at 13359.46,5085.24 h60
  text "TOLERANCE:" at 11408.23,4946.92 h60
  text "X" at 12256.46,4946.92 h60
  text "ANSI IPC-6012 TYPE 3 CLASS 2" at 12434.48,4946.92 h60
  text "OTHER +/-" at 12434.46,4802.73 h60
  text "BOW & TWIST:" at 11408.23,4657.54 h60
  text "X" at 12256.46,4657.54 h60
  text "ANSI IPC-6012 TYPE 3 CLASS 2" at 12434.48,4657.54 h60
  text "OTHER +/-" at 12434.46,4510.85 h60
  text "DRILLING:" at 11333.46,4380.23 h60
  text "NC_DRILL FILES" at 13094.46,4275.04 h60
  text "REFERENCE:" at 11408.23,4271.1 h60
  text "X" at 12065.46,4271.01 h60
  text "AS SHOWN" at 12243.46,4271.1 h60
  text "X" at 12966.46,4271.1 h60
  text "OTHER" at 13392.46,4128.85 h60
  text "PTH COPPER THICKNESS:" at 11407.91,4125.32 h60
  text "X" at 12547.14,4125.32 h60
  text "20-30 um" at 12675.14,4125.32 h60
  text "BOARD FINISH:" at 11333.46,3977.73 h60
  text "SILKSCREEN:" at 11488.68,3867.6 h60
  text "X" at 12446.46,3867.6 h60
  text "TOP" at 12563.46,3867.6 h60
  text "X" at 12956.46,3867.6 h60
  text "BOTTOM" at 13074.46,3867.6 h60
  text "SILKSCREEN COLOR:" at 11488.68,3712.41 h60
  text "X" at 12445.46,3712.41 h60
  text "WHITE" at 12563.46,3712.41 h60
  text "OTHER" at 13074.46,3712.41 h60
  text "X" at 12576.46,3568.96 h60
  text "GREEN" at 12694.46,3568.96 h60
  text "OTHER" at 13312.46,3568.96 h60
  text "SOLDER RESIST COLOR:" at 11488.68,3562.1 h60
  text "X" at 12576.46,3414.71 h60
  text "MATTE" at 12694.46,3414.71 h60
  text "SEMI-GLOSS" at 13312,3414.07 h60
  text "IMMERSION GOLD (ENIG)" at 12394.46,3241.94 h60
  text "ENEPIG" at 13732,3234.72 h60
  text "SURFACE FINISH:" at 11333.46,3233.72 h60
  text "X" at 12216.46,3233.72 h60
  text "IMM. TIN/SILVER OR EQUIV" at 11663,3096.4 h60
  text "OTHER" at 13094.46,3092.47 h60
  text "ARRAY/PANEL:" at 11333.46,2937.09 h60
  text "CUT AND TRIM PER M1 BOARD OUTLINE" at 12394.46,2928.87 h60
  text "N.C. ROUTE" at 12394.46,2792.9 h60
  text "X" at 13082.46,2792.9 h60
  text "V. SCORE" at 13260.46,2792.9 h60
  text "CERTIFICATION:" at 11333.46,2663.77 h60
  text "MATERIALS AND WORKMANSHIP FOR ALL PCBS" at 12058.46,2663.77 h60
  text "TO MEET OR EXCEED THE REQUIREMENTS OF:" at 12058.46,2569.71 h60
  text "X" at 11695.97,2441.08 h60
  text "ANSI IPC-A-600F CLASS ->" at 11823.96,2441.08 h60
  text "X" at 13471.97,2441.08 h60
  text "2" at 13581.96,2441.08 h60
  text "1" at 13266.96,2439.58 h60
  text "3" at 13935.96,2439.58 h60
  text "X" at 12507.97,2293.39 h60
  text "RoHS" at 12635.96,2293.39 h60
  text "OTHER" at 13280.36,2293.39 h60
  text "PER ORDER" at 13677.42,2293.39 h60
  text "ALL BOARDS MUST MEET OR EXCEED UL94-V0 REQUIREMENTS." at 11361,2139.57 h60
  text "PCB MUST BEAR THE UL94V-0 UL REGISTERED MATERIAL ID NUMBER" at 11361,2023.5 h60
  text "ADDITIONAL REQUIREMENTS:" at 11333.46,1854.08 h60
  text "MICROSECTION:" at 11408.23,1746.95 h60
  text "YES" at 12313.96,1746.95 h60
  text "REQUIRED" at 13175.46,1602.62 h60
  text "BARE BOARD ELEC. TEST:" at 11408.23,1599.76 h60
  text "NONE" at 12713.96,1599.76 h60
  text "X" at 13057.46,1599.76 h60
  text "PER ORDER" at 13767.46,1599.76 h60
  text "XX MIL VIAS REQUIRE NON-CONDUCTIVE FILL AND PLANARIZE" at 11576.38,1394.82 h59
  text "XX MIL VIAS REQUIRE CONDUCTIVE FILL AND PLANARIZE" at 11584.38,1290.84 h60
  text "OUTER XX MIL TRACES REQUIRE 50 OHM SINGLE-ENDED IMPEDANCE" at 11583.39,1127.46 h58
  text "LAYER 2 & 3 (INNER LAYERS) XX MIL WIDE, XX MIL SPACE / TRACES REQUIRE 100 OHM DIFFERENTIAL IMPEDANCE" at 11575.39,891.74 h60
  text ".Layer_Name" at 577,-858.49 h60
M11 Gerber Information:
  lines w10: -292,-930.17 6308,-930.17 ; -292,-726.83 6310,-726.83 ; -292,-523.5 -292,-1133.5 3713,-1133.5 6310,-1133.5 6310,-523.5 -291.5,-523.5 -291.5,-1133.5 1284,-1133.5 ; 2173,-1133.5 2173,-523.5 ; 3440,-726.83 3440,-523.5 ; 4280,-726.83 4280,-523.5 ; 4902,-1140 4902,-937.17
  text "ALL ARTWORK VIEWED FROM TOP SIDE" at -228.5,-655.67 h60
  text "BOARD #:" at 2248,-655.67 h60
  text ".PRJ_Number" at 2793.5,-655.67 h60
  text "REV:" at 3638,-655.67 h60
  text ".PCB_Rev" at 3929.5,-655.67 h60
  text "SVN REV:" at 4476,-655.67 h60
  text ".VersionControl_RevNumber" at 4982,-655.67 h60
  text "LAYER NAME =" at -228.5,-858.49 h60
  text "TID #:" at 2248,-859 h60
  text ".TID" at 2793.5,-859 h60
  text "PLOT NAME =" at -228.5,-1064.34 h60
  text ".plot_File_Name" at 577,-1064.34 h60
  text "GENERATED    :" at 2250,-1064.34 h60
  text ".Print_Date" at 3119.5,-1064.34 h60
  text ".Print_Time" at 3848.5,-1064.34 h60
  text "TEXAS INSTRUMENTS" at 5113,-1064.34 h60
M12 Stackup:
  drawing of 399 lines, arcs and shapes, not listed
  text "Layer" at 6667.2,7476.14 h60
  text "Name" at 7077.11,7476.14 h60
  text "Material" at 8016.85,7476.14 h60
  text "Thickness" at 8876.62,7476.14 h60
  text "Constant" at 9526.45,7476.14 h60
  text "Board Layer Stack" at 10096.31,7476.14 h60
  text "Top Overlay" at 7077.11,7356.14 h60
  text "Top Solder" at 7077.11,7236.14 h60
  text "Solder Resist" at 8016.85,7236.14 h60
  text "0.40mil" at 8876.62,7236.14 h60
  text "3.5" at 9526.45,7236.14 h60
  text "1" at 6667.2,7116.14 h60
  text "Top Layer" at 7077.11,7116.14 h60
  text "2.80mil" at 8876.62,7116.14 h60
  text "Dielectric 2" at 7077.11,6996.14 h60
  text "7.00mil" at 8876.62,6996.14 h60
  text "4.2" at 9526.45,6996.14 h60
  text "2" at 6667.2,6876.14 h60
  text "Signal Layer 1" at 7077.11,6876.14 h60
  text "2.80mil" at 8876.62,6876.14 h60
  text "Dielectric 3" at 7077.11,6756.14 h60
  text "14.00mil" at 8876.62,6756.14 h60
  text "4.2" at 9526.45,6756.14 h60
  text "3" at 6667.2,6636.14 h60
  text "Signal Layer 2" at 7077.11,6636.14 h60
  text "2.80mil" at 8876.62,6636.14 h60
  text "Dielectric1" at 7077.11,6516.14 h60
  text "FR-4" at 8016.85,6516.14 h60
  text "7.00mil" at 8876.62,6516.14 h60
  text "4.2" at 9526.45,6516.14 h60
  text "4" at 6667.2,6396.14 h60
  text "Signal Layer 3" at 7077.11,6396.14 h60
  text "2.80mil" at 8876.62,6396.14 h60
  text "Dielectric 4" at 7077.11,6276.14 h60
  text "14.00mil" at 8876.62,6276.14 h60
  text "4.2" at 9526.45,6276.14 h60
  text "5" at 6667.2,6156.14 h60
  text "Signal Layer 4" at 7077.11,6156.14 h60
  text "2.80mil" at 8876.62,6156.14 h60
  text "Dielectric 5" at 7077.11,6036.14 h60
  text "7.00mil" at 8876.62,6036.14 h60
  text "4.2" at 9526.45,6036.14 h60
  text "6" at 6667.2,5916.14 h60
  text "Bottom Layer" at 7077.11,5916.14 h60
  text "2.80mil" at 8876.62,5916.14 h60
  text "Bottom Solder" at 7077.11,5796.14 h60
  text "Solder Resist" at 8016.85,5796.14 h60
  text "0.40mil" at 8876.62,5796.14 h60
  text "3.5" at 9526.45,5796.14 h60
  text "Bottom Overlay" at 7077.11,5676.14 h60
  text ".Layer_Name" at 577,-858.49 h60
M13 Component Bodies Top:
  text ".Layer_Name" at 577,-858.49 h60
M14 Component Bodies Bottom:
  text ".Layer_Name" at 577,-858.49 h60
M15 Courtyards Top:
  text ".Layer_Name" at 577,-858.49 h60
M16 Courtyards Bottom:
  text ".Layer_Name" at 577,-858.49 h60
Drill Drawing:
  text ".Layer_Name" at 577,-858.49 h60
M17 Embedded Cavity:
  text ".Layer_Name" at 577,-858.49 h60
M18 Embedded Assembly:
  text ".Layer_Name" at 577,-858.49 h60
M19 Embedded Keepout:
  text ".Layer_Name" at 577,-858.49 h60

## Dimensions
0,-400 to 1000,-400 on M2 Board Dimensions
1574.8,196.85 to 1574.8,4527.56 on M2 Board Dimensions
1574.8,196.85 to 7283.46,196.85 on M2 Board Dimensions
